VERSION 5.8 ;
BUSBITCHARS "[]" ;
DIVIDERCHAR "/" ;
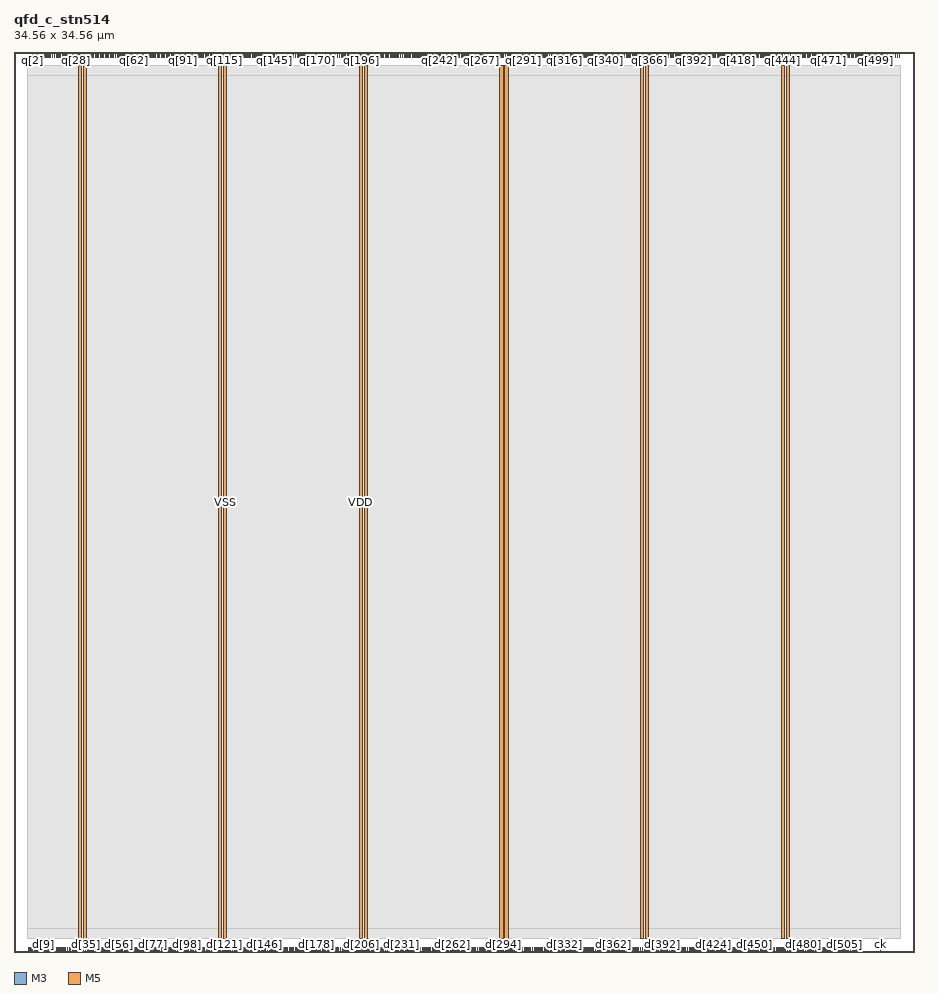
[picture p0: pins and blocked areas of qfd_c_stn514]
MACRO qfd_c_stn514
  CLASS BLOCK ;
  ORIGIN 0 0 ;
  FOREIGN qfd_c_stn514 0 0 ;
  SIZE 34.56 BY 34.56 ;
  SYMMETRY X Y ;
  PIN d[0]
    DIRECTION INPUT ;
    USE SIGNAL ;
    PORT
      LAYER M3 ;
        RECT 0.573 0.000 0.597 0.192 ;
    END
  END d[0]
  PIN d[1]
    DIRECTION INPUT ;
    USE SIGNAL ;
    PORT
      LAYER M5 ;
        RECT 0.624 0.000 0.648 0.192 ;
    END
  END d[1]
  PIN d[2]
    DIRECTION INPUT ;
    USE SIGNAL ;
    PORT
      LAYER M3 ;
        RECT 0.681 0.000 0.705 0.192 ;
    END
  END d[2]
  PIN d[3]
    DIRECTION INPUT ;
    USE SIGNAL ;
    PORT
      LAYER M5 ;
        RECT 0.768 0.000 0.792 0.192 ;
    END
  END d[3]
  PIN d[4]
    DIRECTION INPUT ;
    USE SIGNAL ;
    PORT
      LAYER M3 ;
        RECT 0.789 0.000 0.813 0.192 ;
    END
  END d[4]
  PIN d[5]
    DIRECTION INPUT ;
    USE SIGNAL ;
    PORT
      LAYER M5 ;
        RECT 0.864 0.000 0.888 0.192 ;
    END
  END d[5]
  PIN d[6]
    DIRECTION INPUT ;
    USE SIGNAL ;
    PORT
      LAYER M3 ;
        RECT 0.933 0.000 0.957 0.192 ;
    END
  END d[6]
  PIN d[7]
    DIRECTION INPUT ;
    USE SIGNAL ;
    PORT
      LAYER M5 ;
        RECT 1.008 0.000 1.032 0.192 ;
    END
  END d[7]
  PIN d[8]
    DIRECTION INPUT ;
    USE SIGNAL ;
    PORT
      LAYER M3 ;
        RECT 1.041 0.000 1.065 0.192 ;
    END
  END d[8]
  PIN d[9]
    DIRECTION INPUT ;
    USE SIGNAL ;
    PORT
      LAYER M5 ;
        RECT 1.104 0.000 1.128 0.192 ;
    END
  END d[9]
  PIN d[10]
    DIRECTION INPUT ;
    USE SIGNAL ;
    PORT
      LAYER M3 ;
        RECT 1.185 0.000 1.209 0.192 ;
    END
  END d[10]
  PIN d[11]
    DIRECTION INPUT ;
    USE SIGNAL ;
    PORT
      LAYER M5 ;
        RECT 1.248 0.000 1.272 0.192 ;
    END
  END d[11]
  PIN d[12]
    DIRECTION INPUT ;
    USE SIGNAL ;
    PORT
      LAYER M3 ;
        RECT 1.293 0.000 1.317 0.192 ;
    END
  END d[12]
  PIN d[13]
    DIRECTION INPUT ;
    USE SIGNAL ;
    PORT
      LAYER M5 ;
        RECT 1.344 0.000 1.368 0.192 ;
    END
  END d[13]
  PIN d[14]
    DIRECTION INPUT ;
    USE SIGNAL ;
    PORT
      LAYER M3 ;
        RECT 1.437 0.000 1.461 0.192 ;
    END
  END d[14]
  PIN d[15]
    DIRECTION INPUT ;
    USE SIGNAL ;
    PORT
      LAYER M5 ;
        RECT 1.488 0.000 1.512 0.192 ;
    END
  END d[15]
  PIN d[16]
    DIRECTION INPUT ;
    USE SIGNAL ;
    PORT
      LAYER M3 ;
        RECT 1.545 0.000 1.569 0.192 ;
    END
  END d[16]
  PIN d[17]
    DIRECTION INPUT ;
    USE SIGNAL ;
    PORT
      LAYER M5 ;
        RECT 1.632 0.000 1.656 0.192 ;
    END
  END d[17]
  PIN d[18]
    DIRECTION INPUT ;
    USE SIGNAL ;
    PORT
      LAYER M3 ;
        RECT 1.689 0.000 1.713 0.192 ;
    END
  END d[18]
  PIN d[19]
    DIRECTION INPUT ;
    USE SIGNAL ;
    PORT
      LAYER M5 ;
        RECT 1.728 0.000 1.752 0.192 ;
    END
  END d[19]
  PIN d[20]
    DIRECTION INPUT ;
    USE SIGNAL ;
    PORT
      LAYER M3 ;
        RECT 1.797 0.000 1.821 0.192 ;
    END
  END d[20]
  PIN d[21]
    DIRECTION INPUT ;
    USE SIGNAL ;
    PORT
      LAYER M5 ;
        RECT 1.872 0.000 1.896 0.192 ;
    END
  END d[21]
  PIN d[22]
    DIRECTION INPUT ;
    USE SIGNAL ;
    PORT
      LAYER M3 ;
        RECT 1.905 0.000 1.929 0.192 ;
    END
  END d[22]
  PIN d[23]
    DIRECTION INPUT ;
    USE SIGNAL ;
    PORT
      LAYER M5 ;
        RECT 1.968 0.000 1.992 0.192 ;
    END
  END d[23]
  PIN d[24]
    DIRECTION INPUT ;
    USE SIGNAL ;
    PORT
      LAYER M3 ;
        RECT 2.049 0.000 2.073 0.192 ;
    END
  END d[24]
  PIN d[25]
    DIRECTION INPUT ;
    USE SIGNAL ;
    PORT
      LAYER M5 ;
        RECT 2.112 0.000 2.136 0.192 ;
    END
  END d[25]
  PIN d[26]
    DIRECTION INPUT ;
    USE SIGNAL ;
    PORT
      LAYER M3 ;
        RECT 2.157 0.000 2.181 0.192 ;
    END
  END d[26]
  PIN d[27]
    DIRECTION INPUT ;
    USE SIGNAL ;
    PORT
      LAYER M5 ;
        RECT 2.256 0.000 2.280 0.192 ;
    END
  END d[27]
  PIN d[28]
    DIRECTION INPUT ;
    USE SIGNAL ;
    PORT
      LAYER M3 ;
        RECT 2.301 0.000 2.325 0.192 ;
    END
  END d[28]
  PIN d[29]
    DIRECTION INPUT ;
    USE SIGNAL ;
    PORT
      LAYER M5 ;
        RECT 2.352 0.000 2.376 0.192 ;
    END
  END d[29]
  PIN d[30]
    DIRECTION INPUT ;
    USE SIGNAL ;
    PORT
      LAYER M3 ;
        RECT 2.409 0.000 2.433 0.192 ;
    END
  END d[30]
  PIN d[31]
    DIRECTION INPUT ;
    USE SIGNAL ;
    PORT
      LAYER M5 ;
        RECT 2.496 0.000 2.520 0.192 ;
    END
  END d[31]
  PIN d[32]
    DIRECTION INPUT ;
    USE SIGNAL ;
    PORT
      LAYER M3 ;
        RECT 2.553 0.000 2.577 0.192 ;
    END
  END d[32]
  PIN d[33]
    DIRECTION INPUT ;
    USE SIGNAL ;
    PORT
      LAYER M5 ;
        RECT 2.592 0.000 2.616 0.192 ;
    END
  END d[33]
  PIN d[34]
    DIRECTION INPUT ;
    USE SIGNAL ;
    PORT
      LAYER M3 ;
        RECT 2.661 0.000 2.685 0.192 ;
    END
  END d[34]
  PIN d[35]
    DIRECTION INPUT ;
    USE SIGNAL ;
    PORT
      LAYER M5 ;
        RECT 2.736 0.000 2.760 0.192 ;
    END
  END d[35]
  PIN d[36]
    DIRECTION INPUT ;
    USE SIGNAL ;
    PORT
      LAYER M3 ;
        RECT 2.805 0.000 2.829 0.192 ;
    END
  END d[36]
  PIN d[37]
    DIRECTION INPUT ;
    USE SIGNAL ;
    PORT
      LAYER M5 ;
        RECT 2.832 0.000 2.856 0.192 ;
    END
  END d[37]
  PIN d[38]
    DIRECTION INPUT ;
    USE SIGNAL ;
    PORT
      LAYER M3 ;
        RECT 2.913 0.000 2.937 0.192 ;
    END
  END d[38]
  PIN d[39]
    DIRECTION INPUT ;
    USE SIGNAL ;
    PORT
      LAYER M5 ;
        RECT 2.976 0.000 3.000 0.192 ;
    END
  END d[39]
  PIN d[40]
    DIRECTION INPUT ;
    USE SIGNAL ;
    PORT
      LAYER M3 ;
        RECT 3.021 0.000 3.045 0.192 ;
    END
  END d[40]
  PIN d[41]
    DIRECTION INPUT ;
    USE SIGNAL ;
    PORT
      LAYER M5 ;
        RECT 3.120 0.000 3.144 0.192 ;
    END
  END d[41]
  PIN d[42]
    DIRECTION INPUT ;
    USE SIGNAL ;
    PORT
      LAYER M3 ;
        RECT 3.165 0.000 3.189 0.192 ;
    END
  END d[42]
  PIN d[43]
    DIRECTION INPUT ;
    USE SIGNAL ;
    PORT
      LAYER M5 ;
        RECT 3.216 0.000 3.240 0.192 ;
    END
  END d[43]
  PIN d[44]
    DIRECTION INPUT ;
    USE SIGNAL ;
    PORT
      LAYER M3 ;
        RECT 3.273 0.000 3.297 0.192 ;
    END
  END d[44]
  PIN d[45]
    DIRECTION INPUT ;
    USE SIGNAL ;
    PORT
      LAYER M5 ;
        RECT 3.360 0.000 3.384 0.192 ;
    END
  END d[45]
  PIN d[46]
    DIRECTION INPUT ;
    USE SIGNAL ;
    PORT
      LAYER M3 ;
        RECT 3.417 0.000 3.441 0.192 ;
    END
  END d[46]
  PIN d[47]
    DIRECTION INPUT ;
    USE SIGNAL ;
    PORT
      LAYER M5 ;
        RECT 3.456 0.000 3.480 0.192 ;
    END
  END d[47]
  PIN d[48]
    DIRECTION INPUT ;
    USE SIGNAL ;
    PORT
      LAYER M3 ;
        RECT 3.525 0.000 3.549 0.192 ;
    END
  END d[48]
  PIN d[49]
    DIRECTION INPUT ;
    USE SIGNAL ;
    PORT
      LAYER M5 ;
        RECT 3.600 0.000 3.624 0.192 ;
    END
  END d[49]
  PIN d[50]
    DIRECTION INPUT ;
    USE SIGNAL ;
    PORT
      LAYER M3 ;
        RECT 3.669 0.000 3.693 0.192 ;
    END
  END d[50]
  PIN d[51]
    DIRECTION INPUT ;
    USE SIGNAL ;
    PORT
      LAYER M5 ;
        RECT 3.744 0.000 3.768 0.192 ;
    END
  END d[51]
  PIN d[52]
    DIRECTION INPUT ;
    USE SIGNAL ;
    PORT
      LAYER M3 ;
        RECT 3.777 0.000 3.801 0.192 ;
    END
  END d[52]
  PIN d[53]
    DIRECTION INPUT ;
    USE SIGNAL ;
    PORT
      LAYER M5 ;
        RECT 3.840 0.000 3.864 0.192 ;
    END
  END d[53]
  PIN d[54]
    DIRECTION INPUT ;
    USE SIGNAL ;
    PORT
      LAYER M3 ;
        RECT 3.921 0.000 3.945 0.192 ;
    END
  END d[54]
  PIN d[55]
    DIRECTION INPUT ;
    USE SIGNAL ;
    PORT
      LAYER M5 ;
        RECT 3.984 0.000 4.008 0.192 ;
    END
  END d[55]
  PIN d[56]
    DIRECTION INPUT ;
    USE SIGNAL ;
    PORT
      LAYER M3 ;
        RECT 4.029 0.000 4.053 0.192 ;
    END
  END d[56]
  PIN d[57]
    DIRECTION INPUT ;
    USE SIGNAL ;
    PORT
      LAYER M5 ;
        RECT 4.080 0.000 4.104 0.192 ;
    END
  END d[57]
  PIN d[58]
    DIRECTION INPUT ;
    USE SIGNAL ;
    PORT
      LAYER M3 ;
        RECT 4.137 0.000 4.161 0.192 ;
    END
  END d[58]
  PIN d[59]
    DIRECTION INPUT ;
    USE SIGNAL ;
    PORT
      LAYER M5 ;
        RECT 4.224 0.000 4.248 0.192 ;
    END
  END d[59]
  PIN d[60]
    DIRECTION INPUT ;
    USE SIGNAL ;
    PORT
      LAYER M3 ;
        RECT 4.281 0.000 4.305 0.192 ;
    END
  END d[60]
  PIN d[61]
    DIRECTION INPUT ;
    USE SIGNAL ;
    PORT
      LAYER M5 ;
        RECT 4.320 0.000 4.344 0.192 ;
    END
  END d[61]
  PIN d[62]
    DIRECTION INPUT ;
    USE SIGNAL ;
    PORT
      LAYER M3 ;
        RECT 4.389 0.000 4.413 0.192 ;
    END
  END d[62]
  PIN d[63]
    DIRECTION INPUT ;
    USE SIGNAL ;
    PORT
      LAYER M5 ;
        RECT 4.464 0.000 4.488 0.192 ;
    END
  END d[63]
  PIN d[64]
    DIRECTION INPUT ;
    USE SIGNAL ;
    PORT
      LAYER M3 ;
        RECT 4.533 0.000 4.557 0.192 ;
    END
  END d[64]
  PIN d[65]
    DIRECTION INPUT ;
    USE SIGNAL ;
    PORT
      LAYER M5 ;
        RECT 4.608 0.000 4.632 0.192 ;
    END
  END d[65]
  PIN d[66]
    DIRECTION INPUT ;
    USE SIGNAL ;
    PORT
      LAYER M3 ;
        RECT 4.641 0.000 4.665 0.192 ;
    END
  END d[66]
  PIN d[67]
    DIRECTION INPUT ;
    USE SIGNAL ;
    PORT
      LAYER M5 ;
        RECT 4.704 0.000 4.728 0.192 ;
    END
  END d[67]
  PIN d[68]
    DIRECTION INPUT ;
    USE SIGNAL ;
    PORT
      LAYER M3 ;
        RECT 4.785 0.000 4.809 0.192 ;
    END
  END d[68]
  PIN d[69]
    DIRECTION INPUT ;
    USE SIGNAL ;
    PORT
      LAYER M5 ;
        RECT 4.848 0.000 4.872 0.192 ;
    END
  END d[69]
  PIN d[70]
    DIRECTION INPUT ;
    USE SIGNAL ;
    PORT
      LAYER M3 ;
        RECT 4.893 0.000 4.917 0.192 ;
    END
  END d[70]
  PIN d[71]
    DIRECTION INPUT ;
    USE SIGNAL ;
    PORT
      LAYER M5 ;
        RECT 4.944 0.000 4.968 0.192 ;
    END
  END d[71]
  PIN d[72]
    DIRECTION INPUT ;
    USE SIGNAL ;
    PORT
      LAYER M3 ;
        RECT 5.037 0.000 5.061 0.192 ;
    END
  END d[72]
  PIN d[73]
    DIRECTION INPUT ;
    USE SIGNAL ;
    PORT
      LAYER M5 ;
        RECT 5.088 0.000 5.112 0.192 ;
    END
  END d[73]
  PIN d[74]
    DIRECTION INPUT ;
    USE SIGNAL ;
    PORT
      LAYER M3 ;
        RECT 5.145 0.000 5.169 0.192 ;
    END
  END d[74]
  PIN d[75]
    DIRECTION INPUT ;
    USE SIGNAL ;
    PORT
      LAYER M5 ;
        RECT 5.184 0.000 5.208 0.192 ;
    END
  END d[75]
  PIN d[76]
    DIRECTION INPUT ;
    USE SIGNAL ;
    PORT
      LAYER M3 ;
        RECT 5.253 0.000 5.277 0.192 ;
    END
  END d[76]
  PIN d[77]
    DIRECTION INPUT ;
    USE SIGNAL ;
    PORT
      LAYER M5 ;
        RECT 5.328 0.000 5.352 0.192 ;
    END
  END d[77]
  PIN d[78]
    DIRECTION INPUT ;
    USE SIGNAL ;
    PORT
      LAYER M3 ;
        RECT 5.397 0.000 5.421 0.192 ;
    END
  END d[78]
  PIN d[79]
    DIRECTION INPUT ;
    USE SIGNAL ;
    PORT
      LAYER M5 ;
        RECT 5.472 0.000 5.496 0.192 ;
    END
  END d[79]
  PIN d[80]
    DIRECTION INPUT ;
    USE SIGNAL ;
    PORT
      LAYER M3 ;
        RECT 5.505 0.000 5.529 0.192 ;
    END
  END d[80]
  PIN d[81]
    DIRECTION INPUT ;
    USE SIGNAL ;
    PORT
      LAYER M5 ;
        RECT 5.568 0.000 5.592 0.192 ;
    END
  END d[81]
  PIN d[82]
    DIRECTION INPUT ;
    USE SIGNAL ;
    PORT
      LAYER M3 ;
        RECT 5.649 0.000 5.673 0.192 ;
    END
  END d[82]
  PIN d[83]
    DIRECTION INPUT ;
    USE SIGNAL ;
    PORT
      LAYER M5 ;
        RECT 5.712 0.000 5.736 0.192 ;
    END
  END d[83]
  PIN d[84]
    DIRECTION INPUT ;
    USE SIGNAL ;
    PORT
      LAYER M3 ;
        RECT 5.757 0.000 5.781 0.192 ;
    END
  END d[84]
  PIN d[85]
    DIRECTION INPUT ;
    USE SIGNAL ;
    PORT
      LAYER M5 ;
        RECT 5.808 0.000 5.832 0.192 ;
    END
  END d[85]
  PIN d[86]
    DIRECTION INPUT ;
    USE SIGNAL ;
    PORT
      LAYER M3 ;
        RECT 5.901 0.000 5.925 0.192 ;
    END
  END d[86]
  PIN d[87]
    DIRECTION INPUT ;
    USE SIGNAL ;
    PORT
      LAYER M5 ;
        RECT 5.952 0.000 5.976 0.192 ;
    END
  END d[87]
  PIN d[88]
    DIRECTION INPUT ;
    USE SIGNAL ;
    PORT
      LAYER M3 ;
        RECT 6.009 0.000 6.033 0.192 ;
    END
  END d[88]
  PIN d[89]
    DIRECTION INPUT ;
    USE SIGNAL ;
    PORT
      LAYER M5 ;
        RECT 6.096 0.000 6.120 0.192 ;
    END
  END d[89]
  PIN d[90]
    DIRECTION INPUT ;
    USE SIGNAL ;
    PORT
      LAYER M3 ;
        RECT 6.153 0.000 6.177 0.192 ;
    END
  END d[90]
  PIN d[91]
    DIRECTION INPUT ;
    USE SIGNAL ;
    PORT
      LAYER M5 ;
        RECT 6.192 0.000 6.216 0.192 ;
    END
  END d[91]
  PIN d[92]
    DIRECTION INPUT ;
    USE SIGNAL ;
    PORT
      LAYER M3 ;
        RECT 6.261 0.000 6.285 0.192 ;
    END
  END d[92]
  PIN d[93]
    DIRECTION INPUT ;
    USE SIGNAL ;
    PORT
      LAYER M5 ;
        RECT 6.336 0.000 6.360 0.192 ;
    END
  END d[93]
  PIN d[94]
    DIRECTION INPUT ;
    USE SIGNAL ;
    PORT
      LAYER M3 ;
        RECT 6.369 0.000 6.393 0.192 ;
    END
  END d[94]
  PIN d[95]
    DIRECTION INPUT ;
    USE SIGNAL ;
    PORT
      LAYER M5 ;
        RECT 6.432 0.000 6.456 0.192 ;
    END
  END d[95]
  PIN d[96]
    DIRECTION INPUT ;
    USE SIGNAL ;
    PORT
      LAYER M3 ;
        RECT 6.513 0.000 6.537 0.192 ;
    END
  END d[96]
  PIN d[97]
    DIRECTION INPUT ;
    USE SIGNAL ;
    PORT
      LAYER M5 ;
        RECT 6.576 0.000 6.600 0.192 ;
    END
  END d[97]
  PIN d[98]
    DIRECTION INPUT ;
    USE SIGNAL ;
    PORT
      LAYER M3 ;
        RECT 6.621 0.000 6.645 0.192 ;
    END
  END d[98]
  PIN d[99]
    DIRECTION INPUT ;
    USE SIGNAL ;
    PORT
      LAYER M5 ;
        RECT 6.672 0.000 6.696 0.192 ;
    END
  END d[99]
  PIN d[100]
    DIRECTION INPUT ;
    USE SIGNAL ;
    PORT
      LAYER M3 ;
        RECT 6.765 0.000 6.789 0.192 ;
    END
  END d[100]
  PIN d[101]
    DIRECTION INPUT ;
    USE SIGNAL ;
    PORT
      LAYER M5 ;
        RECT 6.816 0.000 6.840 0.192 ;
    END
  END d[101]
  PIN d[102]
    DIRECTION INPUT ;
    USE SIGNAL ;
    PORT
      LAYER M3 ;
        RECT 6.873 0.000 6.897 0.192 ;
    END
  END d[102]
  PIN d[103]
    DIRECTION INPUT ;
    USE SIGNAL ;
    PORT
      LAYER M5 ;
        RECT 6.960 0.000 6.984 0.192 ;
    END
  END d[103]
  PIN d[104]
    DIRECTION INPUT ;
    USE SIGNAL ;
    PORT
      LAYER M3 ;
        RECT 7.017 0.000 7.041 0.192 ;
    END
  END d[104]
  PIN d[105]
    DIRECTION INPUT ;
    USE SIGNAL ;
    PORT
      LAYER M5 ;
        RECT 7.056 0.000 7.080 0.192 ;
    END
  END d[105]
  PIN d[106]
    DIRECTION INPUT ;
    USE SIGNAL ;
    PORT
      LAYER M3 ;
        RECT 7.125 0.000 7.149 0.192 ;
    END
  END d[106]
  PIN d[107]
    DIRECTION INPUT ;
    USE SIGNAL ;
    PORT
      LAYER M5 ;
        RECT 7.200 0.000 7.224 0.192 ;
    END
  END d[107]
  PIN d[108]
    DIRECTION INPUT ;
    USE SIGNAL ;
    PORT
      LAYER M3 ;
        RECT 7.269 0.000 7.293 0.192 ;
    END
  END d[108]
  PIN d[109]
    DIRECTION INPUT ;
    USE SIGNAL ;
    PORT
      LAYER M5 ;
        RECT 7.296 0.000 7.320 0.192 ;
    END
  END d[109]
  PIN d[110]
    DIRECTION INPUT ;
    USE SIGNAL ;
    PORT
      LAYER M3 ;
        RECT 7.377 0.000 7.401 0.192 ;
    END
  END d[110]
  PIN d[111]
    DIRECTION INPUT ;
    USE SIGNAL ;
    PORT
      LAYER M5 ;
        RECT 7.440 0.000 7.464 0.192 ;
    END
  END d[111]
  PIN d[112]
    DIRECTION INPUT ;
    USE SIGNAL ;
    PORT
      LAYER M3 ;
        RECT 7.485 0.000 7.509 0.192 ;
    END
  END d[112]
  PIN d[113]
    DIRECTION INPUT ;
    USE SIGNAL ;
    PORT
      LAYER M5 ;
        RECT 7.584 0.000 7.608 0.192 ;
    END
  END d[113]
  PIN d[114]
    DIRECTION INPUT ;
    USE SIGNAL ;
    PORT
      LAYER M3 ;
        RECT 7.629 0.000 7.653 0.192 ;
    END
  END d[114]
  PIN d[115]
    DIRECTION INPUT ;
    USE SIGNAL ;
    PORT
      LAYER M5 ;
        RECT 7.680 0.000 7.704 0.192 ;
    END
  END d[115]
  PIN d[116]
    DIRECTION INPUT ;
    USE SIGNAL ;
    PORT
      LAYER M3 ;
        RECT 7.737 0.000 7.761 0.192 ;
    END
  END d[116]
  PIN d[117]
    DIRECTION INPUT ;
    USE SIGNAL ;
    PORT
      LAYER M5 ;
        RECT 7.824 0.000 7.848 0.192 ;
    END
  END d[117]
  PIN d[118]
    DIRECTION INPUT ;
    USE SIGNAL ;
    PORT
      LAYER M3 ;
        RECT 7.881 0.000 7.905 0.192 ;
    END
  END d[118]
  PIN d[119]
    DIRECTION INPUT ;
    USE SIGNAL ;
    PORT
      LAYER M5 ;
        RECT 7.920 0.000 7.944 0.192 ;
    END
  END d[119]
  PIN d[120]
    DIRECTION INPUT ;
    USE SIGNAL ;
    PORT
      LAYER M3 ;
        RECT 7.989 0.000 8.013 0.192 ;
    END
  END d[120]
  PIN d[121]
    DIRECTION INPUT ;
    USE SIGNAL ;
    PORT
      LAYER M5 ;
        RECT 8.064 0.000 8.088 0.192 ;
    END
  END d[121]
  PIN d[122]
    DIRECTION INPUT ;
    USE SIGNAL ;
    PORT
      LAYER M3 ;
        RECT 8.133 0.000 8.157 0.192 ;
    END
  END d[122]
  PIN d[123]
    DIRECTION INPUT ;
    USE SIGNAL ;
    PORT
      LAYER M5 ;
        RECT 8.160 0.000 8.184 0.192 ;
    END
  END d[123]
  PIN d[124]
    DIRECTION INPUT ;
    USE SIGNAL ;
    PORT
      LAYER M3 ;
        RECT 8.241 0.000 8.265 0.192 ;
    END
  END d[124]
  PIN d[125]
    DIRECTION INPUT ;
    USE SIGNAL ;
    PORT
      LAYER M5 ;
        RECT 8.304 0.000 8.328 0.192 ;
    END
  END d[125]
  PIN d[126]
    DIRECTION INPUT ;
    USE SIGNAL ;
    PORT
      LAYER M3 ;
        RECT 8.385 0.000 8.409 0.192 ;
    END
  END d[126]
  PIN d[127]
    DIRECTION INPUT ;
    USE SIGNAL ;
    PORT
      LAYER M5 ;
        RECT 8.448 0.000 8.472 0.192 ;
    END
  END d[127]
  PIN d[128]
    DIRECTION INPUT ;
    USE SIGNAL ;
    PORT
      LAYER M3 ;
        RECT 8.493 0.000 8.517 0.192 ;
    END
  END d[128]
  PIN d[129]
    DIRECTION INPUT ;
    USE SIGNAL ;
    PORT
      LAYER M5 ;
        RECT 8.544 0.000 8.568 0.192 ;
    END
  END d[129]
  PIN d[130]
    DIRECTION INPUT ;
    USE SIGNAL ;
    PORT
      LAYER M3 ;
        RECT 8.601 0.000 8.625 0.192 ;
    END
  END d[130]
  PIN d[131]
    DIRECTION INPUT ;
    USE SIGNAL ;
    PORT
      LAYER M5 ;
        RECT 8.688 0.000 8.712 0.192 ;
    END
  END d[131]
  PIN d[132]
    DIRECTION INPUT ;
    USE SIGNAL ;
    PORT
      LAYER M3 ;
        RECT 8.745 0.000 8.769 0.192 ;
    END
  END d[132]
  PIN d[133]
    DIRECTION INPUT ;
    USE SIGNAL ;
    PORT
      LAYER M5 ;
        RECT 8.784 0.000 8.808 0.192 ;
    END
  END d[133]
  PIN d[134]
    DIRECTION INPUT ;
    USE SIGNAL ;
    PORT
      LAYER M3 ;
        RECT 8.853 0.000 8.877 0.192 ;
    END
  END d[134]
  PIN d[135]
    DIRECTION INPUT ;
    USE SIGNAL ;
    PORT
      LAYER M5 ;
        RECT 8.928 0.000 8.952 0.192 ;
    END
  END d[135]
  PIN d[136]
    DIRECTION INPUT ;
    USE SIGNAL ;
    PORT
      LAYER M3 ;
        RECT 8.997 0.000 9.021 0.192 ;
    END
  END d[136]
  PIN d[137]
    DIRECTION INPUT ;
    USE SIGNAL ;
    PORT
      LAYER M5 ;
        RECT 9.072 0.000 9.096 0.192 ;
    END
  END d[137]
  PIN d[138]
    DIRECTION INPUT ;
    USE SIGNAL ;
    PORT
      LAYER M3 ;
        RECT 9.105 0.000 9.129 0.192 ;
    END
  END d[138]
  PIN d[139]
    DIRECTION INPUT ;
    USE SIGNAL ;
    PORT
      LAYER M5 ;
        RECT 9.168 0.000 9.192 0.192 ;
    END
  END d[139]
  PIN d[140]
    DIRECTION INPUT ;
    USE SIGNAL ;
    PORT
      LAYER M3 ;
        RECT 9.249 0.000 9.273 0.192 ;
    END
  END d[140]
  PIN d[141]
    DIRECTION INPUT ;
    USE SIGNAL ;
    PORT
      LAYER M5 ;
        RECT 9.312 0.000 9.336 0.192 ;
    END
  END d[141]
  PIN d[142]
    DIRECTION INPUT ;
    USE SIGNAL ;
    PORT
      LAYER M3 ;
        RECT 9.357 0.000 9.381 0.192 ;
    END
  END d[142]
  PIN d[143]
    DIRECTION INPUT ;
    USE SIGNAL ;
    PORT
      LAYER M5 ;
        RECT 9.408 0.000 9.432 0.192 ;
    END
  END d[143]
  PIN d[144]
    DIRECTION INPUT ;
    USE SIGNAL ;
    PORT
      LAYER M3 ;
        RECT 9.501 0.000 9.525 0.192 ;
    END
  END d[144]
  PIN d[145]
    DIRECTION INPUT ;
    USE SIGNAL ;
    PORT
      LAYER M5 ;
        RECT 9.552 0.000 9.576 0.192 ;
    END
  END d[145]
  PIN d[146]
    DIRECTION INPUT ;
    USE SIGNAL ;
    PORT
      LAYER M3 ;
        RECT 9.609 0.000 9.633 0.192 ;
    END
  END d[146]
  PIN d[147]
    DIRECTION INPUT ;
    USE SIGNAL ;
    PORT
      LAYER M5 ;
        RECT 9.648 0.000 9.672 0.192 ;
    END
  END d[147]
  PIN d[148]
    DIRECTION INPUT ;
    USE SIGNAL ;
    PORT
      LAYER M3 ;
        RECT 9.717 0.000 9.741 0.192 ;
    END
  END d[148]
  PIN d[149]
    DIRECTION INPUT ;
    USE SIGNAL ;
    PORT
      LAYER M5 ;
        RECT 9.792 0.000 9.816 0.192 ;
    END
  END d[149]
  PIN d[150]
    DIRECTION INPUT ;
    USE SIGNAL ;
    PORT
      LAYER M3 ;
        RECT 9.861 0.000 9.885 0.192 ;
    END
  END d[150]
  PIN d[151]
    DIRECTION INPUT ;
    USE SIGNAL ;
    PORT
      LAYER M5 ;
        RECT 9.936 0.000 9.960 0.192 ;
    END
  END d[151]
  PIN d[152]
    DIRECTION INPUT ;
    USE SIGNAL ;
    PORT
      LAYER M3 ;
        RECT 9.969 0.000 9.993 0.192 ;
    END
  END d[152]
  PIN d[153]
    DIRECTION INPUT ;
    USE SIGNAL ;
    PORT
      LAYER M5 ;
        RECT 10.032 0.000 10.056 0.192 ;
    END
  END d[153]
  PIN d[154]
    DIRECTION INPUT ;
    USE SIGNAL ;
    PORT
      LAYER M3 ;
        RECT 10.113 0.000 10.137 0.192 ;
    END
  END d[154]
  PIN d[155]
    DIRECTION INPUT ;
    USE SIGNAL ;
    PORT
      LAYER M5 ;
        RECT 10.176 0.000 10.200 0.192 ;
    END
  END d[155]
  PIN d[156]
    DIRECTION INPUT ;
    USE SIGNAL ;
    PORT
      LAYER M3 ;
        RECT 10.221 0.000 10.245 0.192 ;
    END
  END d[156]
  PIN d[157]
    DIRECTION INPUT ;
    USE SIGNAL ;
    PORT
      LAYER M5 ;
        RECT 10.272 0.000 10.296 0.192 ;
    END
  END d[157]
  PIN d[158]
    DIRECTION INPUT ;
    USE SIGNAL ;
    PORT
      LAYER M3 ;
        RECT 10.365 0.000 10.389 0.192 ;
    END
  END d[158]
  PIN d[159]
    DIRECTION INPUT ;
    USE SIGNAL ;
    PORT
      LAYER M5 ;
        RECT 10.416 0.000 10.440 0.192 ;
    END
  END d[159]
  PIN d[160]
    DIRECTION INPUT ;
    USE SIGNAL ;
    PORT
      LAYER M3 ;
        RECT 10.473 0.000 10.497 0.192 ;
    END
  END d[160]
  PIN d[161]
    DIRECTION INPUT ;
    USE SIGNAL ;
    PORT
      LAYER M5 ;
        RECT 10.560 0.000 10.584 0.192 ;
    END
  END d[161]
  PIN d[162]
    DIRECTION INPUT ;
    USE SIGNAL ;
    PORT
      LAYER M3 ;
        RECT 10.617 0.000 10.641 0.192 ;
    END
  END d[162]
  PIN d[163]
    DIRECTION INPUT ;
    USE SIGNAL ;
    PORT
      LAYER M5 ;
        RECT 10.656 0.000 10.680 0.192 ;
    END
  END d[163]
  PIN d[164]
    DIRECTION INPUT ;
    USE SIGNAL ;
    PORT
      LAYER M3 ;
        RECT 10.725 0.000 10.749 0.192 ;
    END
  END d[164]
  PIN d[165]
    DIRECTION INPUT ;
    USE SIGNAL ;
    PORT
      LAYER M5 ;
        RECT 10.800 0.000 10.824 0.192 ;
    END
  END d[165]
  PIN d[166]
    DIRECTION INPUT ;
    USE SIGNAL ;
    PORT
      LAYER M3 ;
        RECT 10.833 0.000 10.857 0.192 ;
    END
  END d[166]
  PIN d[167]
    DIRECTION INPUT ;
    USE SIGNAL ;
    PORT
      LAYER M5 ;
        RECT 10.896 0.000 10.920 0.192 ;
    END
  END d[167]
  PIN d[168]
    DIRECTION INPUT ;
    USE SIGNAL ;
    PORT
      LAYER M3 ;
        RECT 10.977 0.000 11.001 0.192 ;
    END
  END d[168]
  PIN d[169]
    DIRECTION INPUT ;
    USE SIGNAL ;
    PORT
      LAYER M5 ;
        RECT 11.040 0.000 11.064 0.192 ;
    END
  END d[169]
  PIN d[170]
    DIRECTION INPUT ;
    USE SIGNAL ;
    PORT
      LAYER M3 ;
        RECT 11.085 0.000 11.109 0.192 ;
    END
  END d[170]
  PIN d[171]
    DIRECTION INPUT ;
    USE SIGNAL ;
    PORT
      LAYER M5 ;
        RECT 11.136 0.000 11.160 0.192 ;
    END
  END d[171]
  PIN d[172]
    DIRECTION INPUT ;
    USE SIGNAL ;
    PORT
      LAYER M3 ;
        RECT 11.229 0.000 11.253 0.192 ;
    END
  END d[172]
  PIN d[173]
    DIRECTION INPUT ;
    USE SIGNAL ;
    PORT
      LAYER M5 ;
        RECT 11.280 0.000 11.304 0.192 ;
    END
  END d[173]
  PIN d[174]
    DIRECTION INPUT ;
    USE SIGNAL ;
    PORT
      LAYER M3 ;
        RECT 11.337 0.000 11.361 0.192 ;
    END
  END d[174]
  PIN d[175]
    DIRECTION INPUT ;
    USE SIGNAL ;
    PORT
      LAYER M5 ;
        RECT 11.424 0.000 11.448 0.192 ;
    END
  END d[175]
  PIN d[176]
    DIRECTION INPUT ;
    USE SIGNAL ;
    PORT
      LAYER M3 ;
        RECT 11.481 0.000 11.505 0.192 ;
    END
  END d[176]
  PIN d[177]
    DIRECTION INPUT ;
    USE SIGNAL ;
    PORT
      LAYER M5 ;
        RECT 11.520 0.000 11.544 0.192 ;
    END
  END d[177]
  PIN d[178]
    DIRECTION INPUT ;
    USE SIGNAL ;
    PORT
      LAYER M3 ;
        RECT 11.589 0.000 11.613 0.192 ;
    END
  END d[178]
  PIN d[179]
    DIRECTION INPUT ;
    USE SIGNAL ;
    PORT
      LAYER M5 ;
        RECT 11.664 0.000 11.688 0.192 ;
    END
  END d[179]
  PIN d[180]
    DIRECTION INPUT ;
    USE SIGNAL ;
    PORT
      LAYER M3 ;
        RECT 11.733 0.000 11.757 0.192 ;
    END
  END d[180]
  PIN d[181]
    DIRECTION INPUT ;
    USE SIGNAL ;
    PORT
      LAYER M5 ;
        RECT 11.760 0.000 11.784 0.192 ;
    END
  END d[181]
  PIN d[182]
    DIRECTION INPUT ;
    USE SIGNAL ;
    PORT
      LAYER M3 ;
        RECT 11.841 0.000 11.865 0.192 ;
    END
  END d[182]
  PIN d[183]
    DIRECTION INPUT ;
    USE SIGNAL ;
    PORT
      LAYER M5 ;
        RECT 11.904 0.000 11.928 0.192 ;
    END
  END d[183]
  PIN d[184]
    DIRECTION INPUT ;
    USE SIGNAL ;
    PORT
      LAYER M3 ;
        RECT 11.949 0.000 11.973 0.192 ;
    END
  END d[184]
  PIN d[185]
    DIRECTION INPUT ;
    USE SIGNAL ;
    PORT
      LAYER M5 ;
        RECT 12.048 0.000 12.072 0.192 ;
    END
  END d[185]
  PIN d[186]
    DIRECTION INPUT ;
    USE SIGNAL ;
    PORT
      LAYER M3 ;
        RECT 12.093 0.000 12.117 0.192 ;
    END
  END d[186]
  PIN d[187]
    DIRECTION INPUT ;
    USE SIGNAL ;
    PORT
      LAYER M5 ;
        RECT 12.144 0.000 12.168 0.192 ;
    END
  END d[187]
  PIN d[188]
    DIRECTION INPUT ;
    USE SIGNAL ;
    PORT
      LAYER M3 ;
        RECT 12.201 0.000 12.225 0.192 ;
    END
  END d[188]
  PIN d[189]
    DIRECTION INPUT ;
    USE SIGNAL ;
    PORT
      LAYER M5 ;
        RECT 12.288 0.000 12.312 0.192 ;
    END
  END d[189]
  PIN d[190]
    DIRECTION INPUT ;
    USE SIGNAL ;
    PORT
      LAYER M3 ;
        RECT 12.345 0.000 12.369 0.192 ;
    END
  END d[190]
  PIN d[191]
    DIRECTION INPUT ;
    USE SIGNAL ;
    PORT
      LAYER M5 ;
        RECT 12.384 0.000 12.408 0.192 ;
    END
  END d[191]
  PIN d[192]
    DIRECTION INPUT ;
    USE SIGNAL ;
    PORT
      LAYER M3 ;
        RECT 12.453 0.000 12.477 0.192 ;
    END
  END d[192]
  PIN d[193]
    DIRECTION INPUT ;
    USE SIGNAL ;
    PORT
      LAYER M5 ;
        RECT 12.528 0.000 12.552 0.192 ;
    END
  END d[193]
  PIN d[194]
    DIRECTION INPUT ;
    USE SIGNAL ;
    PORT
      LAYER M3 ;
        RECT 12.597 0.000 12.621 0.192 ;
    END
  END d[194]
  PIN d[195]
    DIRECTION INPUT ;
    USE SIGNAL ;
    PORT
      LAYER M5 ;
        RECT 12.624 0.000 12.648 0.192 ;
    END
  END d[195]
  PIN d[196]
    DIRECTION INPUT ;
    USE SIGNAL ;
    PORT
      LAYER M3 ;
        RECT 12.705 0.000 12.729 0.192 ;
    END
  END d[196]
  PIN d[197]
    DIRECTION INPUT ;
    USE SIGNAL ;
    PORT
      LAYER M5 ;
        RECT 12.768 0.000 12.792 0.192 ;
    END
  END d[197]
  PIN d[198]
    DIRECTION INPUT ;
    USE SIGNAL ;
    PORT
      LAYER M3 ;
        RECT 12.849 0.000 12.873 0.192 ;
    END
  END d[198]
  PIN d[199]
    DIRECTION INPUT ;
    USE SIGNAL ;
    PORT
      LAYER M5 ;
        RECT 12.912 0.000 12.936 0.192 ;
    END
  END d[199]
  PIN d[200]
    DIRECTION INPUT ;
    USE SIGNAL ;
    PORT
      LAYER M3 ;
        RECT 12.957 0.000 12.981 0.192 ;
    END
  END d[200]
  PIN d[201]
    DIRECTION INPUT ;
    USE SIGNAL ;
    PORT
      LAYER M5 ;
        RECT 13.008 0.000 13.032 0.192 ;
    END
  END d[201]
  PIN d[202]
    DIRECTION INPUT ;
    USE SIGNAL ;
    PORT
      LAYER M3 ;
        RECT 13.065 0.000 13.089 0.192 ;
    END
  END d[202]
  PIN d[203]
    DIRECTION INPUT ;
    USE SIGNAL ;
    PORT
      LAYER M5 ;
        RECT 13.152 0.000 13.176 0.192 ;
    END
  END d[203]
  PIN d[204]
    DIRECTION INPUT ;
    USE SIGNAL ;
    PORT
      LAYER M3 ;
        RECT 13.209 0.000 13.233 0.192 ;
    END
  END d[204]
  PIN d[205]
    DIRECTION INPUT ;
    USE SIGNAL ;
    PORT
      LAYER M5 ;
        RECT 13.248 0.000 13.272 0.192 ;
    END
  END d[205]
  PIN d[206]
    DIRECTION INPUT ;
    USE SIGNAL ;
    PORT
      LAYER M3 ;
        RECT 13.317 0.000 13.341 0.192 ;
    END
  END d[206]
  PIN d[207]
    DIRECTION INPUT ;
    USE SIGNAL ;
    PORT
      LAYER M5 ;
        RECT 13.392 0.000 13.416 0.192 ;
    END
  END d[207]
  PIN d[208]
    DIRECTION INPUT ;
    USE SIGNAL ;
    PORT
      LAYER M3 ;
        RECT 13.461 0.000 13.485 0.192 ;
    END
  END d[208]
  PIN d[209]
    DIRECTION INPUT ;
    USE SIGNAL ;
    PORT
      LAYER M5 ;
        RECT 13.536 0.000 13.560 0.192 ;
    END
  END d[209]
  PIN d[210]
    DIRECTION INPUT ;
    USE SIGNAL ;
    PORT
      LAYER M3 ;
        RECT 13.569 0.000 13.593 0.192 ;
    END
  END d[210]
  PIN d[211]
    DIRECTION INPUT ;
    USE SIGNAL ;
    PORT
      LAYER M5 ;
        RECT 13.632 0.000 13.656 0.192 ;
    END
  END d[211]
  PIN d[212]
    DIRECTION INPUT ;
    USE SIGNAL ;
    PORT
      LAYER M3 ;
        RECT 13.713 0.000 13.737 0.192 ;
    END
  END d[212]
  PIN d[213]
    DIRECTION INPUT ;
    USE SIGNAL ;
    PORT
      LAYER M5 ;
        RECT 13.776 0.000 13.800 0.192 ;
    END
  END d[213]
  PIN d[214]
    DIRECTION INPUT ;
    USE SIGNAL ;
    PORT
      LAYER M3 ;
        RECT 13.821 0.000 13.845 0.192 ;
    END
  END d[214]
  PIN d[215]
    DIRECTION INPUT ;
    USE SIGNAL ;
    PORT
      LAYER M5 ;
        RECT 13.872 0.000 13.896 0.192 ;
    END
  END d[215]
  PIN d[216]
    DIRECTION INPUT ;
    USE SIGNAL ;
    PORT
      LAYER M3 ;
        RECT 13.965 0.000 13.989 0.192 ;
    END
  END d[216]
  PIN d[217]
    DIRECTION INPUT ;
    USE SIGNAL ;
    PORT
      LAYER M5 ;
        RECT 14.016 0.000 14.040 0.192 ;
    END
  END d[217]
  PIN d[218]
    DIRECTION INPUT ;
    USE SIGNAL ;
    PORT
      LAYER M3 ;
        RECT 14.073 0.000 14.097 0.192 ;
    END
  END d[218]
  PIN d[219]
    DIRECTION INPUT ;
    USE SIGNAL ;
    PORT
      LAYER M5 ;
        RECT 14.112 0.000 14.136 0.192 ;
    END
  END d[219]
  PIN d[220]
    DIRECTION INPUT ;
    USE SIGNAL ;
    PORT
      LAYER M3 ;
        RECT 14.181 0.000 14.205 0.192 ;
    END
  END d[220]
  PIN d[221]
    DIRECTION INPUT ;
    USE SIGNAL ;
    PORT
      LAYER M5 ;
        RECT 14.256 0.000 14.280 0.192 ;
    END
  END d[221]
  PIN d[222]
    DIRECTION INPUT ;
    USE SIGNAL ;
    PORT
      LAYER M3 ;
        RECT 14.325 0.000 14.349 0.192 ;
    END
  END d[222]
  PIN d[223]
    DIRECTION INPUT ;
    USE SIGNAL ;
    PORT
      LAYER M5 ;
        RECT 14.400 0.000 14.424 0.192 ;
    END
  END d[223]
  PIN d[224]
    DIRECTION INPUT ;
    USE SIGNAL ;
    PORT
      LAYER M3 ;
        RECT 14.433 0.000 14.457 0.192 ;
    END
  END d[224]
  PIN d[225]
    DIRECTION INPUT ;
    USE SIGNAL ;
    PORT
      LAYER M5 ;
        RECT 14.496 0.000 14.520 0.192 ;
    END
  END d[225]
  PIN d[226]
    DIRECTION INPUT ;
    USE SIGNAL ;
    PORT
      LAYER M3 ;
        RECT 14.577 0.000 14.601 0.192 ;
    END
  END d[226]
  PIN d[227]
    DIRECTION INPUT ;
    USE SIGNAL ;
    PORT
      LAYER M5 ;
        RECT 14.640 0.000 14.664 0.192 ;
    END
  END d[227]
  PIN d[228]
    DIRECTION INPUT ;
    USE SIGNAL ;
    PORT
      LAYER M3 ;
        RECT 14.685 0.000 14.709 0.192 ;
    END
  END d[228]
  PIN d[229]
    DIRECTION INPUT ;
    USE SIGNAL ;
    PORT
      LAYER M5 ;
        RECT 14.736 0.000 14.760 0.192 ;
    END
  END d[229]
  PIN d[230]
    DIRECTION INPUT ;
    USE SIGNAL ;
    PORT
      LAYER M3 ;
        RECT 14.829 0.000 14.853 0.192 ;
    END
  END d[230]
  PIN d[231]
    DIRECTION INPUT ;
    USE SIGNAL ;
    PORT
      LAYER M5 ;
        RECT 14.880 0.000 14.904 0.192 ;
    END
  END d[231]
  PIN d[232]
    DIRECTION INPUT ;
    USE SIGNAL ;
    PORT
      LAYER M3 ;
        RECT 14.937 0.000 14.961 0.192 ;
    END
  END d[232]
  PIN d[233]
    DIRECTION INPUT ;
    USE SIGNAL ;
    PORT
      LAYER M5 ;
        RECT 15.024 0.000 15.048 0.192 ;
    END
  END d[233]
  PIN d[234]
    DIRECTION INPUT ;
    USE SIGNAL ;
    PORT
      LAYER M3 ;
        RECT 15.081 0.000 15.105 0.192 ;
    END
  END d[234]
  PIN d[235]
    DIRECTION INPUT ;
    USE SIGNAL ;
    PORT
      LAYER M5 ;
        RECT 15.120 0.000 15.144 0.192 ;
    END
  END d[235]
  PIN d[236]
    DIRECTION INPUT ;
    USE SIGNAL ;
    PORT
      LAYER M3 ;
        RECT 15.189 0.000 15.213 0.192 ;
    END
  END d[236]
  PIN d[237]
    DIRECTION INPUT ;
    USE SIGNAL ;
    PORT
      LAYER M5 ;
        RECT 15.264 0.000 15.288 0.192 ;
    END
  END d[237]
  PIN d[238]
    DIRECTION INPUT ;
    USE SIGNAL ;
    PORT
      LAYER M3 ;
        RECT 15.297 0.000 15.321 0.192 ;
    END
  END d[238]
  PIN d[239]
    DIRECTION INPUT ;
    USE SIGNAL ;
    PORT
      LAYER M5 ;
        RECT 15.360 0.000 15.384 0.192 ;
    END
  END d[239]
  PIN d[240]
    DIRECTION INPUT ;
    USE SIGNAL ;
    PORT
      LAYER M3 ;
        RECT 15.441 0.000 15.465 0.192 ;
    END
  END d[240]
  PIN d[241]
    DIRECTION INPUT ;
    USE SIGNAL ;
    PORT
      LAYER M5 ;
        RECT 15.504 0.000 15.528 0.192 ;
    END
  END d[241]
  PIN d[242]
    DIRECTION INPUT ;
    USE SIGNAL ;
    PORT
      LAYER M3 ;
        RECT 15.549 0.000 15.573 0.192 ;
    END
  END d[242]
  PIN d[243]
    DIRECTION INPUT ;
    USE SIGNAL ;
    PORT
      LAYER M5 ;
        RECT 15.600 0.000 15.624 0.192 ;
    END
  END d[243]
  PIN d[244]
    DIRECTION INPUT ;
    USE SIGNAL ;
    PORT
      LAYER M3 ;
        RECT 15.693 0.000 15.717 0.192 ;
    END
  END d[244]
  PIN d[245]
    DIRECTION INPUT ;
    USE SIGNAL ;
    PORT
      LAYER M5 ;
        RECT 15.744 0.000 15.768 0.192 ;
    END
  END d[245]
  PIN d[246]
    DIRECTION INPUT ;
    USE SIGNAL ;
    PORT
      LAYER M3 ;
        RECT 15.801 0.000 15.825 0.192 ;
    END
  END d[246]
  PIN d[247]
    DIRECTION INPUT ;
    USE SIGNAL ;
    PORT
      LAYER M5 ;
        RECT 15.888 0.000 15.912 0.192 ;
    END
  END d[247]
  PIN d[248]
    DIRECTION INPUT ;
    USE SIGNAL ;
    PORT
      LAYER M3 ;
        RECT 15.945 0.000 15.969 0.192 ;
    END
  END d[248]
  PIN d[249]
    DIRECTION INPUT ;
    USE SIGNAL ;
    PORT
      LAYER M5 ;
        RECT 15.984 0.000 16.008 0.192 ;
    END
  END d[249]
  PIN d[250]
    DIRECTION INPUT ;
    USE SIGNAL ;
    PORT
      LAYER M3 ;
        RECT 16.053 0.000 16.077 0.192 ;
    END
  END d[250]
  PIN d[251]
    DIRECTION INPUT ;
    USE SIGNAL ;
    PORT
      LAYER M5 ;
        RECT 16.128 0.000 16.152 0.192 ;
    END
  END d[251]
  PIN d[252]
    DIRECTION INPUT ;
    USE SIGNAL ;
    PORT
      LAYER M3 ;
        RECT 16.197 0.000 16.221 0.192 ;
    END
  END d[252]
  PIN d[253]
    DIRECTION INPUT ;
    USE SIGNAL ;
    PORT
      LAYER M5 ;
        RECT 16.224 0.000 16.248 0.192 ;
    END
  END d[253]
  PIN d[254]
    DIRECTION INPUT ;
    USE SIGNAL ;
    PORT
      LAYER M3 ;
        RECT 16.305 0.000 16.329 0.192 ;
    END
  END d[254]
  PIN d[255]
    DIRECTION INPUT ;
    USE SIGNAL ;
    PORT
      LAYER M5 ;
        RECT 16.368 0.000 16.392 0.192 ;
    END
  END d[255]
  PIN d[256]
    DIRECTION INPUT ;
    USE SIGNAL ;
    PORT
      LAYER M3 ;
        RECT 16.413 0.000 16.437 0.192 ;
    END
  END d[256]
  PIN d[257]
    DIRECTION INPUT ;
    USE SIGNAL ;
    PORT
      LAYER M5 ;
        RECT 16.512 0.000 16.536 0.192 ;
    END
  END d[257]
  PIN d[258]
    DIRECTION INPUT ;
    USE SIGNAL ;
    PORT
      LAYER M3 ;
        RECT 16.557 0.000 16.581 0.192 ;
    END
  END d[258]
  PIN d[259]
    DIRECTION INPUT ;
    USE SIGNAL ;
    PORT
      LAYER M5 ;
        RECT 16.608 0.000 16.632 0.192 ;
    END
  END d[259]
  PIN d[260]
    DIRECTION INPUT ;
    USE SIGNAL ;
    PORT
      LAYER M3 ;
        RECT 16.665 0.000 16.689 0.192 ;
    END
  END d[260]
  PIN d[261]
    DIRECTION INPUT ;
    USE SIGNAL ;
    PORT
      LAYER M5 ;
        RECT 16.752 0.000 16.776 0.192 ;
    END
  END d[261]
  PIN d[262]
    DIRECTION INPUT ;
    USE SIGNAL ;
    PORT
      LAYER M3 ;
        RECT 16.809 0.000 16.833 0.192 ;
    END
  END d[262]
  PIN d[263]
    DIRECTION INPUT ;
    USE SIGNAL ;
    PORT
      LAYER M5 ;
        RECT 16.848 0.000 16.872 0.192 ;
    END
  END d[263]
  PIN d[264]
    DIRECTION INPUT ;
    USE SIGNAL ;
    PORT
      LAYER M3 ;
        RECT 16.917 0.000 16.941 0.192 ;
    END
  END d[264]
  PIN d[265]
    DIRECTION INPUT ;
    USE SIGNAL ;
    PORT
      LAYER M5 ;
        RECT 16.992 0.000 17.016 0.192 ;
    END
  END d[265]
  PIN d[266]
    DIRECTION INPUT ;
    USE SIGNAL ;
    PORT
      LAYER M3 ;
        RECT 17.061 0.000 17.085 0.192 ;
    END
  END d[266]
  PIN d[267]
    DIRECTION INPUT ;
    USE SIGNAL ;
    PORT
      LAYER M5 ;
        RECT 17.088 0.000 17.112 0.192 ;
    END
  END d[267]
  PIN d[268]
    DIRECTION INPUT ;
    USE SIGNAL ;
    PORT
      LAYER M3 ;
        RECT 17.169 0.000 17.193 0.192 ;
    END
  END d[268]
  PIN d[269]
    DIRECTION INPUT ;
    USE SIGNAL ;
    PORT
      LAYER M5 ;
        RECT 17.232 0.000 17.256 0.192 ;
    END
  END d[269]
  PIN d[270]
    DIRECTION INPUT ;
    USE SIGNAL ;
    PORT
      LAYER M3 ;
        RECT 17.277 0.000 17.301 0.192 ;
    END
  END d[270]
  PIN d[271]
    DIRECTION INPUT ;
    USE SIGNAL ;
    PORT
      LAYER M5 ;
        RECT 17.376 0.000 17.400 0.192 ;
    END
  END d[271]
  PIN d[272]
    DIRECTION INPUT ;
    USE SIGNAL ;
    PORT
      LAYER M3 ;
        RECT 17.421 0.000 17.445 0.192 ;
    END
  END d[272]
  PIN d[273]
    DIRECTION INPUT ;
    USE SIGNAL ;
    PORT
      LAYER M5 ;
        RECT 17.472 0.000 17.496 0.192 ;
    END
  END d[273]
  PIN d[274]
    DIRECTION INPUT ;
    USE SIGNAL ;
    PORT
      LAYER M3 ;
        RECT 17.529 0.000 17.553 0.192 ;
    END
  END d[274]
  PIN d[275]
    DIRECTION INPUT ;
    USE SIGNAL ;
    PORT
      LAYER M5 ;
        RECT 17.616 0.000 17.640 0.192 ;
    END
  END d[275]
  PIN d[276]
    DIRECTION INPUT ;
    USE SIGNAL ;
    PORT
      LAYER M3 ;
        RECT 17.673 0.000 17.697 0.192 ;
    END
  END d[276]
  PIN d[277]
    DIRECTION INPUT ;
    USE SIGNAL ;
    PORT
      LAYER M5 ;
        RECT 17.712 0.000 17.736 0.192 ;
    END
  END d[277]
  PIN d[278]
    DIRECTION INPUT ;
    USE SIGNAL ;
    PORT
      LAYER M3 ;
        RECT 17.781 0.000 17.805 0.192 ;
    END
  END d[278]
  PIN d[279]
    DIRECTION INPUT ;
    USE SIGNAL ;
    PORT
      LAYER M5 ;
        RECT 17.856 0.000 17.880 0.192 ;
    END
  END d[279]
  PIN d[280]
    DIRECTION INPUT ;
    USE SIGNAL ;
    PORT
      LAYER M3 ;
        RECT 17.925 0.000 17.949 0.192 ;
    END
  END d[280]
  PIN d[281]
    DIRECTION INPUT ;
    USE SIGNAL ;
    PORT
      LAYER M5 ;
        RECT 18.000 0.000 18.024 0.192 ;
    END
  END d[281]
  PIN d[282]
    DIRECTION INPUT ;
    USE SIGNAL ;
    PORT
      LAYER M3 ;
        RECT 18.033 0.000 18.057 0.192 ;
    END
  END d[282]
  PIN d[283]
    DIRECTION INPUT ;
    USE SIGNAL ;
    PORT
      LAYER M5 ;
        RECT 18.096 0.000 18.120 0.192 ;
    END
  END d[283]
  PIN d[284]
    DIRECTION INPUT ;
    USE SIGNAL ;
    PORT
      LAYER M3 ;
        RECT 18.177 0.000 18.201 0.192 ;
    END
  END d[284]
  PIN d[285]
    DIRECTION INPUT ;
    USE SIGNAL ;
    PORT
      LAYER M5 ;
        RECT 18.240 0.000 18.264 0.192 ;
    END
  END d[285]
  PIN d[286]
    DIRECTION INPUT ;
    USE SIGNAL ;
    PORT
      LAYER M3 ;
        RECT 18.285 0.000 18.309 0.192 ;
    END
  END d[286]
  PIN d[287]
    DIRECTION INPUT ;
    USE SIGNAL ;
    PORT
      LAYER M5 ;
        RECT 18.336 0.000 18.360 0.192 ;
    END
  END d[287]
  PIN d[288]
    DIRECTION INPUT ;
    USE SIGNAL ;
    PORT
      LAYER M3 ;
        RECT 18.393 0.000 18.417 0.192 ;
    END
  END d[288]
  PIN d[289]
    DIRECTION INPUT ;
    USE SIGNAL ;
    PORT
      LAYER M5 ;
        RECT 18.480 0.000 18.504 0.192 ;
    END
  END d[289]
  PIN d[290]
    DIRECTION INPUT ;
    USE SIGNAL ;
    PORT
      LAYER M3 ;
        RECT 18.537 0.000 18.561 0.192 ;
    END
  END d[290]
  PIN d[291]
    DIRECTION INPUT ;
    USE SIGNAL ;
    PORT
      LAYER M5 ;
        RECT 18.576 0.000 18.600 0.192 ;
    END
  END d[291]
  PIN d[292]
    DIRECTION INPUT ;
    USE SIGNAL ;
    PORT
      LAYER M3 ;
        RECT 18.645 0.000 18.669 0.192 ;
    END
  END d[292]
  PIN d[293]
    DIRECTION INPUT ;
    USE SIGNAL ;
    PORT
      LAYER M5 ;
        RECT 18.720 0.000 18.744 0.192 ;
    END
  END d[293]
  PIN d[294]
    DIRECTION INPUT ;
    USE SIGNAL ;
    PORT
      LAYER M3 ;
        RECT 18.789 0.000 18.813 0.192 ;
    END
  END d[294]
  PIN d[295]
    DIRECTION INPUT ;
    USE SIGNAL ;
    PORT
      LAYER M5 ;
        RECT 18.864 0.000 18.888 0.192 ;
    END
  END d[295]
  PIN d[296]
    DIRECTION INPUT ;
    USE SIGNAL ;
    PORT
      LAYER M3 ;
        RECT 18.897 0.000 18.921 0.192 ;
    END
  END d[296]
  PIN d[297]
    DIRECTION INPUT ;
    USE SIGNAL ;
    PORT
      LAYER M5 ;
        RECT 18.960 0.000 18.984 0.192 ;
    END
  END d[297]
  PIN d[298]
    DIRECTION INPUT ;
    USE SIGNAL ;
    PORT
      LAYER M3 ;
        RECT 19.041 0.000 19.065 0.192 ;
    END
  END d[298]
  PIN d[299]
    DIRECTION INPUT ;
    USE SIGNAL ;
    PORT
      LAYER M5 ;
        RECT 19.104 0.000 19.128 0.192 ;
    END
  END d[299]
  PIN d[300]
    DIRECTION INPUT ;
    USE SIGNAL ;
    PORT
      LAYER M3 ;
        RECT 19.149 0.000 19.173 0.192 ;
    END
  END d[300]
  PIN d[301]
    DIRECTION INPUT ;
    USE SIGNAL ;
    PORT
      LAYER M5 ;
        RECT 19.200 0.000 19.224 0.192 ;
    END
  END d[301]
  PIN d[302]
    DIRECTION INPUT ;
    USE SIGNAL ;
    PORT
      LAYER M3 ;
        RECT 19.293 0.000 19.317 0.192 ;
    END
  END d[302]
  PIN d[303]
    DIRECTION INPUT ;
    USE SIGNAL ;
    PORT
      LAYER M5 ;
        RECT 19.344 0.000 19.368 0.192 ;
    END
  END d[303]
  PIN d[304]
    DIRECTION INPUT ;
    USE SIGNAL ;
    PORT
      LAYER M3 ;
        RECT 19.401 0.000 19.425 0.192 ;
    END
  END d[304]
  PIN d[305]
    DIRECTION INPUT ;
    USE SIGNAL ;
    PORT
      LAYER M5 ;
        RECT 19.488 0.000 19.512 0.192 ;
    END
  END d[305]
  PIN d[306]
    DIRECTION INPUT ;
    USE SIGNAL ;
    PORT
      LAYER M3 ;
        RECT 19.509 0.000 19.533 0.192 ;
    END
  END d[306]
  PIN d[307]
    DIRECTION INPUT ;
    USE SIGNAL ;
    PORT
      LAYER M5 ;
        RECT 19.584 0.000 19.608 0.192 ;
    END
  END d[307]
  PIN d[308]
    DIRECTION INPUT ;
    USE SIGNAL ;
    PORT
      LAYER M3 ;
        RECT 19.653 0.000 19.677 0.192 ;
    END
  END d[308]
  PIN d[309]
    DIRECTION INPUT ;
    USE SIGNAL ;
    PORT
      LAYER M5 ;
        RECT 19.728 0.000 19.752 0.192 ;
    END
  END d[309]
  PIN d[310]
    DIRECTION INPUT ;
    USE SIGNAL ;
    PORT
      LAYER M3 ;
        RECT 19.761 0.000 19.785 0.192 ;
    END
  END d[310]
  PIN d[311]
    DIRECTION INPUT ;
    USE SIGNAL ;
    PORT
      LAYER M5 ;
        RECT 19.824 0.000 19.848 0.192 ;
    END
  END d[311]
  PIN d[312]
    DIRECTION INPUT ;
    USE SIGNAL ;
    PORT
      LAYER M3 ;
        RECT 19.905 0.000 19.929 0.192 ;
    END
  END d[312]
  PIN d[313]
    DIRECTION INPUT ;
    USE SIGNAL ;
    PORT
      LAYER M5 ;
        RECT 19.968 0.000 19.992 0.192 ;
    END
  END d[313]
  PIN d[314]
    DIRECTION INPUT ;
    USE SIGNAL ;
    PORT
      LAYER M3 ;
        RECT 20.013 0.000 20.037 0.192 ;
    END
  END d[314]
  PIN d[315]
    DIRECTION INPUT ;
    USE SIGNAL ;
    PORT
      LAYER M5 ;
        RECT 20.064 0.000 20.088 0.192 ;
    END
  END d[315]
  PIN d[316]
    DIRECTION INPUT ;
    USE SIGNAL ;
    PORT
      LAYER M3 ;
        RECT 20.157 0.000 20.181 0.192 ;
    END
  END d[316]
  PIN d[317]
    DIRECTION INPUT ;
    USE SIGNAL ;
    PORT
      LAYER M5 ;
        RECT 20.208 0.000 20.232 0.192 ;
    END
  END d[317]
  PIN d[318]
    DIRECTION INPUT ;
    USE SIGNAL ;
    PORT
      LAYER M3 ;
        RECT 20.265 0.000 20.289 0.192 ;
    END
  END d[318]
  PIN d[319]
    DIRECTION INPUT ;
    USE SIGNAL ;
    PORT
      LAYER M5 ;
        RECT 20.352 0.000 20.376 0.192 ;
    END
  END d[319]
  PIN d[320]
    DIRECTION INPUT ;
    USE SIGNAL ;
    PORT
      LAYER M3 ;
        RECT 20.409 0.000 20.433 0.192 ;
    END
  END d[320]
  PIN d[321]
    DIRECTION INPUT ;
    USE SIGNAL ;
    PORT
      LAYER M5 ;
        RECT 20.448 0.000 20.472 0.192 ;
    END
  END d[321]
  PIN d[322]
    DIRECTION INPUT ;
    USE SIGNAL ;
    PORT
      LAYER M3 ;
        RECT 20.517 0.000 20.541 0.192 ;
    END
  END d[322]
  PIN d[323]
    DIRECTION INPUT ;
    USE SIGNAL ;
    PORT
      LAYER M5 ;
        RECT 20.592 0.000 20.616 0.192 ;
    END
  END d[323]
  PIN d[324]
    DIRECTION INPUT ;
    USE SIGNAL ;
    PORT
      LAYER M3 ;
        RECT 20.625 0.000 20.649 0.192 ;
    END
  END d[324]
  PIN d[325]
    DIRECTION INPUT ;
    USE SIGNAL ;
    PORT
      LAYER M5 ;
        RECT 20.688 0.000 20.712 0.192 ;
    END
  END d[325]
  PIN d[326]
    DIRECTION INPUT ;
    USE SIGNAL ;
    PORT
      LAYER M3 ;
        RECT 20.769 0.000 20.793 0.192 ;
    END
  END d[326]
  PIN d[327]
    DIRECTION INPUT ;
    USE SIGNAL ;
    PORT
      LAYER M5 ;
        RECT 20.832 0.000 20.856 0.192 ;
    END
  END d[327]
  PIN d[328]
    DIRECTION INPUT ;
    USE SIGNAL ;
    PORT
      LAYER M3 ;
        RECT 20.877 0.000 20.901 0.192 ;
    END
  END d[328]
  PIN d[329]
    DIRECTION INPUT ;
    USE SIGNAL ;
    PORT
      LAYER M5 ;
        RECT 20.928 0.000 20.952 0.192 ;
    END
  END d[329]
  PIN d[330]
    DIRECTION INPUT ;
    USE SIGNAL ;
    PORT
      LAYER M3 ;
        RECT 21.021 0.000 21.045 0.192 ;
    END
  END d[330]
  PIN d[331]
    DIRECTION INPUT ;
    USE SIGNAL ;
    PORT
      LAYER M5 ;
        RECT 21.072 0.000 21.096 0.192 ;
    END
  END d[331]
  PIN d[332]
    DIRECTION INPUT ;
    USE SIGNAL ;
    PORT
      LAYER M3 ;
        RECT 21.129 0.000 21.153 0.192 ;
    END
  END d[332]
  PIN d[333]
    DIRECTION INPUT ;
    USE SIGNAL ;
    PORT
      LAYER M5 ;
        RECT 21.216 0.000 21.240 0.192 ;
    END
  END d[333]
  PIN d[334]
    DIRECTION INPUT ;
    USE SIGNAL ;
    PORT
      LAYER M3 ;
        RECT 21.273 0.000 21.297 0.192 ;
    END
  END d[334]
  PIN d[335]
    DIRECTION INPUT ;
    USE SIGNAL ;
    PORT
      LAYER M5 ;
        RECT 21.312 0.000 21.336 0.192 ;
    END
  END d[335]
  PIN d[336]
    DIRECTION INPUT ;
    USE SIGNAL ;
    PORT
      LAYER M3 ;
        RECT 21.381 0.000 21.405 0.192 ;
    END
  END d[336]
  PIN d[337]
    DIRECTION INPUT ;
    USE SIGNAL ;
    PORT
      LAYER M5 ;
        RECT 21.456 0.000 21.480 0.192 ;
    END
  END d[337]
  PIN d[338]
    DIRECTION INPUT ;
    USE SIGNAL ;
    PORT
      LAYER M3 ;
        RECT 21.525 0.000 21.549 0.192 ;
    END
  END d[338]
  PIN d[339]
    DIRECTION INPUT ;
    USE SIGNAL ;
    PORT
      LAYER M5 ;
        RECT 21.552 0.000 21.576 0.192 ;
    END
  END d[339]
  PIN d[340]
    DIRECTION INPUT ;
    USE SIGNAL ;
    PORT
      LAYER M3 ;
        RECT 21.633 0.000 21.657 0.192 ;
    END
  END d[340]
  PIN d[341]
    DIRECTION INPUT ;
    USE SIGNAL ;
    PORT
      LAYER M5 ;
        RECT 21.696 0.000 21.720 0.192 ;
    END
  END d[341]
  PIN d[342]
    DIRECTION INPUT ;
    USE SIGNAL ;
    PORT
      LAYER M3 ;
        RECT 21.741 0.000 21.765 0.192 ;
    END
  END d[342]
  PIN d[343]
    DIRECTION INPUT ;
    USE SIGNAL ;
    PORT
      LAYER M5 ;
        RECT 21.840 0.000 21.864 0.192 ;
    END
  END d[343]
  PIN d[344]
    DIRECTION INPUT ;
    USE SIGNAL ;
    PORT
      LAYER M3 ;
        RECT 21.885 0.000 21.909 0.192 ;
    END
  END d[344]
  PIN d[345]
    DIRECTION INPUT ;
    USE SIGNAL ;
    PORT
      LAYER M5 ;
        RECT 21.936 0.000 21.960 0.192 ;
    END
  END d[345]
  PIN d[346]
    DIRECTION INPUT ;
    USE SIGNAL ;
    PORT
      LAYER M3 ;
        RECT 21.993 0.000 22.017 0.192 ;
    END
  END d[346]
  PIN d[347]
    DIRECTION INPUT ;
    USE SIGNAL ;
    PORT
      LAYER M5 ;
        RECT 22.080 0.000 22.104 0.192 ;
    END
  END d[347]
  PIN d[348]
    DIRECTION INPUT ;
    USE SIGNAL ;
    PORT
      LAYER M3 ;
        RECT 22.137 0.000 22.161 0.192 ;
    END
  END d[348]
  PIN d[349]
    DIRECTION INPUT ;
    USE SIGNAL ;
    PORT
      LAYER M5 ;
        RECT 22.176 0.000 22.200 0.192 ;
    END
  END d[349]
  PIN d[350]
    DIRECTION INPUT ;
    USE SIGNAL ;
    PORT
      LAYER M3 ;
        RECT 22.245 0.000 22.269 0.192 ;
    END
  END d[350]
  PIN d[351]
    DIRECTION INPUT ;
    USE SIGNAL ;
    PORT
      LAYER M5 ;
        RECT 22.320 0.000 22.344 0.192 ;
    END
  END d[351]
  PIN d[352]
    DIRECTION INPUT ;
    USE SIGNAL ;
    PORT
      LAYER M3 ;
        RECT 22.389 0.000 22.413 0.192 ;
    END
  END d[352]
  PIN d[353]
    DIRECTION INPUT ;
    USE SIGNAL ;
    PORT
      LAYER M5 ;
        RECT 22.416 0.000 22.440 0.192 ;
    END
  END d[353]
  PIN d[354]
    DIRECTION INPUT ;
    USE SIGNAL ;
    PORT
      LAYER M3 ;
        RECT 22.497 0.000 22.521 0.192 ;
    END
  END d[354]
  PIN d[355]
    DIRECTION INPUT ;
    USE SIGNAL ;
    PORT
      LAYER M5 ;
        RECT 22.560 0.000 22.584 0.192 ;
    END
  END d[355]
  PIN d[356]
    DIRECTION INPUT ;
    USE SIGNAL ;
    PORT
      LAYER M3 ;
        RECT 22.641 0.000 22.665 0.192 ;
    END
  END d[356]
  PIN d[357]
    DIRECTION INPUT ;
    USE SIGNAL ;
    PORT
      LAYER M5 ;
        RECT 22.704 0.000 22.728 0.192 ;
    END
  END d[357]
  PIN d[358]
    DIRECTION INPUT ;
    USE SIGNAL ;
    PORT
      LAYER M3 ;
        RECT 22.749 0.000 22.773 0.192 ;
    END
  END d[358]
  PIN d[359]
    DIRECTION INPUT ;
    USE SIGNAL ;
    PORT
      LAYER M5 ;
        RECT 22.800 0.000 22.824 0.192 ;
    END
  END d[359]
  PIN d[360]
    DIRECTION INPUT ;
    USE SIGNAL ;
    PORT
      LAYER M3 ;
        RECT 22.857 0.000 22.881 0.192 ;
    END
  END d[360]
  PIN d[361]
    DIRECTION INPUT ;
    USE SIGNAL ;
    PORT
      LAYER M5 ;
        RECT 22.944 0.000 22.968 0.192 ;
    END
  END d[361]
  PIN d[362]
    DIRECTION INPUT ;
    USE SIGNAL ;
    PORT
      LAYER M3 ;
        RECT 23.001 0.000 23.025 0.192 ;
    END
  END d[362]
  PIN d[363]
    DIRECTION INPUT ;
    USE SIGNAL ;
    PORT
      LAYER M5 ;
        RECT 23.040 0.000 23.064 0.192 ;
    END
  END d[363]
  PIN d[364]
    DIRECTION INPUT ;
    USE SIGNAL ;
    PORT
      LAYER M3 ;
        RECT 23.109 0.000 23.133 0.192 ;
    END
  END d[364]
  PIN d[365]
    DIRECTION INPUT ;
    USE SIGNAL ;
    PORT
      LAYER M5 ;
        RECT 23.184 0.000 23.208 0.192 ;
    END
  END d[365]
  PIN d[366]
    DIRECTION INPUT ;
    USE SIGNAL ;
    PORT
      LAYER M3 ;
        RECT 23.253 0.000 23.277 0.192 ;
    END
  END d[366]
  PIN d[367]
    DIRECTION INPUT ;
    USE SIGNAL ;
    PORT
      LAYER M5 ;
        RECT 23.328 0.000 23.352 0.192 ;
    END
  END d[367]
  PIN d[368]
    DIRECTION INPUT ;
    USE SIGNAL ;
    PORT
      LAYER M3 ;
        RECT 23.361 0.000 23.385 0.192 ;
    END
  END d[368]
  PIN d[369]
    DIRECTION INPUT ;
    USE SIGNAL ;
    PORT
      LAYER M5 ;
        RECT 23.424 0.000 23.448 0.192 ;
    END
  END d[369]
  PIN d[370]
    DIRECTION INPUT ;
    USE SIGNAL ;
    PORT
      LAYER M3 ;
        RECT 23.505 0.000 23.529 0.192 ;
    END
  END d[370]
  PIN d[371]
    DIRECTION INPUT ;
    USE SIGNAL ;
    PORT
      LAYER M5 ;
        RECT 23.568 0.000 23.592 0.192 ;
    END
  END d[371]
  PIN d[372]
    DIRECTION INPUT ;
    USE SIGNAL ;
    PORT
      LAYER M3 ;
        RECT 23.613 0.000 23.637 0.192 ;
    END
  END d[372]
  PIN d[373]
    DIRECTION INPUT ;
    USE SIGNAL ;
    PORT
      LAYER M5 ;
        RECT 23.664 0.000 23.688 0.192 ;
    END
  END d[373]
  PIN d[374]
    DIRECTION INPUT ;
    USE SIGNAL ;
    PORT
      LAYER M3 ;
        RECT 23.757 0.000 23.781 0.192 ;
    END
  END d[374]
  PIN d[375]
    DIRECTION INPUT ;
    USE SIGNAL ;
    PORT
      LAYER M5 ;
        RECT 23.808 0.000 23.832 0.192 ;
    END
  END d[375]
  PIN d[376]
    DIRECTION INPUT ;
    USE SIGNAL ;
    PORT
      LAYER M3 ;
        RECT 23.865 0.000 23.889 0.192 ;
    END
  END d[376]
  PIN d[377]
    DIRECTION INPUT ;
    USE SIGNAL ;
    PORT
      LAYER M5 ;
        RECT 23.904 0.000 23.928 0.192 ;
    END
  END d[377]
  PIN d[378]
    DIRECTION INPUT ;
    USE SIGNAL ;
    PORT
      LAYER M3 ;
        RECT 23.973 0.000 23.997 0.192 ;
    END
  END d[378]
  PIN d[379]
    DIRECTION INPUT ;
    USE SIGNAL ;
    PORT
      LAYER M5 ;
        RECT 24.048 0.000 24.072 0.192 ;
    END
  END d[379]
  PIN d[380]
    DIRECTION INPUT ;
    USE SIGNAL ;
    PORT
      LAYER M3 ;
        RECT 24.117 0.000 24.141 0.192 ;
    END
  END d[380]
  PIN d[381]
    DIRECTION INPUT ;
    USE SIGNAL ;
    PORT
      LAYER M5 ;
        RECT 24.192 0.000 24.216 0.192 ;
    END
  END d[381]
  PIN d[382]
    DIRECTION INPUT ;
    USE SIGNAL ;
    PORT
      LAYER M3 ;
        RECT 24.225 0.000 24.249 0.192 ;
    END
  END d[382]
  PIN d[383]
    DIRECTION INPUT ;
    USE SIGNAL ;
    PORT
      LAYER M5 ;
        RECT 24.288 0.000 24.312 0.192 ;
    END
  END d[383]
  PIN d[384]
    DIRECTION INPUT ;
    USE SIGNAL ;
    PORT
      LAYER M3 ;
        RECT 24.369 0.000 24.393 0.192 ;
    END
  END d[384]
  PIN d[385]
    DIRECTION INPUT ;
    USE SIGNAL ;
    PORT
      LAYER M5 ;
        RECT 24.432 0.000 24.456 0.192 ;
    END
  END d[385]
  PIN d[386]
    DIRECTION INPUT ;
    USE SIGNAL ;
    PORT
      LAYER M3 ;
        RECT 24.477 0.000 24.501 0.192 ;
    END
  END d[386]
  PIN d[387]
    DIRECTION INPUT ;
    USE SIGNAL ;
    PORT
      LAYER M5 ;
        RECT 24.528 0.000 24.552 0.192 ;
    END
  END d[387]
  PIN d[388]
    DIRECTION INPUT ;
    USE SIGNAL ;
    PORT
      LAYER M3 ;
        RECT 24.621 0.000 24.645 0.192 ;
    END
  END d[388]
  PIN d[389]
    DIRECTION INPUT ;
    USE SIGNAL ;
    PORT
      LAYER M5 ;
        RECT 24.672 0.000 24.696 0.192 ;
    END
  END d[389]
  PIN d[390]
    DIRECTION INPUT ;
    USE SIGNAL ;
    PORT
      LAYER M3 ;
        RECT 24.729 0.000 24.753 0.192 ;
    END
  END d[390]
  PIN d[391]
    DIRECTION INPUT ;
    USE SIGNAL ;
    PORT
      LAYER M5 ;
        RECT 24.816 0.000 24.840 0.192 ;
    END
  END d[391]
  PIN d[392]
    DIRECTION INPUT ;
    USE SIGNAL ;
    PORT
      LAYER M3 ;
        RECT 24.873 0.000 24.897 0.192 ;
    END
  END d[392]
  PIN d[393]
    DIRECTION INPUT ;
    USE SIGNAL ;
    PORT
      LAYER M5 ;
        RECT 24.912 0.000 24.936 0.192 ;
    END
  END d[393]
  PIN d[394]
    DIRECTION INPUT ;
    USE SIGNAL ;
    PORT
      LAYER M3 ;
        RECT 24.981 0.000 25.005 0.192 ;
    END
  END d[394]
  PIN d[395]
    DIRECTION INPUT ;
    USE SIGNAL ;
    PORT
      LAYER M5 ;
        RECT 25.056 0.000 25.080 0.192 ;
    END
  END d[395]
  PIN d[396]
    DIRECTION INPUT ;
    USE SIGNAL ;
    PORT
      LAYER M3 ;
        RECT 25.089 0.000 25.113 0.192 ;
    END
  END d[396]
  PIN d[397]
    DIRECTION INPUT ;
    USE SIGNAL ;
    PORT
      LAYER M5 ;
        RECT 25.152 0.000 25.176 0.192 ;
    END
  END d[397]
  PIN d[398]
    DIRECTION INPUT ;
    USE SIGNAL ;
    PORT
      LAYER M3 ;
        RECT 25.233 0.000 25.257 0.192 ;
    END
  END d[398]
  PIN d[399]
    DIRECTION INPUT ;
    USE SIGNAL ;
    PORT
      LAYER M5 ;
        RECT 25.296 0.000 25.320 0.192 ;
    END
  END d[399]
  PIN d[400]
    DIRECTION INPUT ;
    USE SIGNAL ;
    PORT
      LAYER M3 ;
        RECT 25.341 0.000 25.365 0.192 ;
    END
  END d[400]
  PIN d[401]
    DIRECTION INPUT ;
    USE SIGNAL ;
    PORT
      LAYER M5 ;
        RECT 25.392 0.000 25.416 0.192 ;
    END
  END d[401]
  PIN d[402]
    DIRECTION INPUT ;
    USE SIGNAL ;
    PORT
      LAYER M3 ;
        RECT 25.485 0.000 25.509 0.192 ;
    END
  END d[402]
  PIN d[403]
    DIRECTION INPUT ;
    USE SIGNAL ;
    PORT
      LAYER M5 ;
        RECT 25.536 0.000 25.560 0.192 ;
    END
  END d[403]
  PIN d[404]
    DIRECTION INPUT ;
    USE SIGNAL ;
    PORT
      LAYER M3 ;
        RECT 25.593 0.000 25.617 0.192 ;
    END
  END d[404]
  PIN d[405]
    DIRECTION INPUT ;
    USE SIGNAL ;
    PORT
      LAYER M5 ;
        RECT 25.680 0.000 25.704 0.192 ;
    END
  END d[405]
  PIN d[406]
    DIRECTION INPUT ;
    USE SIGNAL ;
    PORT
      LAYER M3 ;
        RECT 25.737 0.000 25.761 0.192 ;
    END
  END d[406]
  PIN d[407]
    DIRECTION INPUT ;
    USE SIGNAL ;
    PORT
      LAYER M5 ;
        RECT 25.776 0.000 25.800 0.192 ;
    END
  END d[407]
  PIN d[408]
    DIRECTION INPUT ;
    USE SIGNAL ;
    PORT
      LAYER M3 ;
        RECT 25.845 0.000 25.869 0.192 ;
    END
  END d[408]
  PIN d[409]
    DIRECTION INPUT ;
    USE SIGNAL ;
    PORT
      LAYER M5 ;
        RECT 25.920 0.000 25.944 0.192 ;
    END
  END d[409]
  PIN d[410]
    DIRECTION INPUT ;
    USE SIGNAL ;
    PORT
      LAYER M3 ;
        RECT 25.989 0.000 26.013 0.192 ;
    END
  END d[410]
  PIN d[411]
    DIRECTION INPUT ;
    USE SIGNAL ;
    PORT
      LAYER M5 ;
        RECT 26.016 0.000 26.040 0.192 ;
    END
  END d[411]
  PIN d[412]
    DIRECTION INPUT ;
    USE SIGNAL ;
    PORT
      LAYER M3 ;
        RECT 26.097 0.000 26.121 0.192 ;
    END
  END d[412]
  PIN d[413]
    DIRECTION INPUT ;
    USE SIGNAL ;
    PORT
      LAYER M5 ;
        RECT 26.160 0.000 26.184 0.192 ;
    END
  END d[413]
  PIN d[414]
    DIRECTION INPUT ;
    USE SIGNAL ;
    PORT
      LAYER M3 ;
        RECT 26.205 0.000 26.229 0.192 ;
    END
  END d[414]
  PIN d[415]
    DIRECTION INPUT ;
    USE SIGNAL ;
    PORT
      LAYER M5 ;
        RECT 26.304 0.000 26.328 0.192 ;
    END
  END d[415]
  PIN d[416]
    DIRECTION INPUT ;
    USE SIGNAL ;
    PORT
      LAYER M3 ;
        RECT 26.349 0.000 26.373 0.192 ;
    END
  END d[416]
  PIN d[417]
    DIRECTION INPUT ;
    USE SIGNAL ;
    PORT
      LAYER M5 ;
        RECT 26.400 0.000 26.424 0.192 ;
    END
  END d[417]
  PIN d[418]
    DIRECTION INPUT ;
    USE SIGNAL ;
    PORT
      LAYER M3 ;
        RECT 26.457 0.000 26.481 0.192 ;
    END
  END d[418]
  PIN d[419]
    DIRECTION INPUT ;
    USE SIGNAL ;
    PORT
      LAYER M5 ;
        RECT 26.544 0.000 26.568 0.192 ;
    END
  END d[419]
  PIN d[420]
    DIRECTION INPUT ;
    USE SIGNAL ;
    PORT
      LAYER M3 ;
        RECT 26.601 0.000 26.625 0.192 ;
    END
  END d[420]
  PIN d[421]
    DIRECTION INPUT ;
    USE SIGNAL ;
    PORT
      LAYER M5 ;
        RECT 26.640 0.000 26.664 0.192 ;
    END
  END d[421]
  PIN d[422]
    DIRECTION INPUT ;
    USE SIGNAL ;
    PORT
      LAYER M3 ;
        RECT 26.709 0.000 26.733 0.192 ;
    END
  END d[422]
  PIN d[423]
    DIRECTION INPUT ;
    USE SIGNAL ;
    PORT
      LAYER M5 ;
        RECT 26.784 0.000 26.808 0.192 ;
    END
  END d[423]
  PIN d[424]
    DIRECTION INPUT ;
    USE SIGNAL ;
    PORT
      LAYER M3 ;
        RECT 26.853 0.000 26.877 0.192 ;
    END
  END d[424]
  PIN d[425]
    DIRECTION INPUT ;
    USE SIGNAL ;
    PORT
      LAYER M5 ;
        RECT 26.880 0.000 26.904 0.192 ;
    END
  END d[425]
  PIN d[426]
    DIRECTION INPUT ;
    USE SIGNAL ;
    PORT
      LAYER M3 ;
        RECT 26.961 0.000 26.985 0.192 ;
    END
  END d[426]
  PIN d[427]
    DIRECTION INPUT ;
    USE SIGNAL ;
    PORT
      LAYER M5 ;
        RECT 27.024 0.000 27.048 0.192 ;
    END
  END d[427]
  PIN d[428]
    DIRECTION INPUT ;
    USE SIGNAL ;
    PORT
      LAYER M3 ;
        RECT 27.105 0.000 27.129 0.192 ;
    END
  END d[428]
  PIN d[429]
    DIRECTION INPUT ;
    USE SIGNAL ;
    PORT
      LAYER M5 ;
        RECT 27.168 0.000 27.192 0.192 ;
    END
  END d[429]
  PIN d[430]
    DIRECTION INPUT ;
    USE SIGNAL ;
    PORT
      LAYER M3 ;
        RECT 27.213 0.000 27.237 0.192 ;
    END
  END d[430]
  PIN d[431]
    DIRECTION INPUT ;
    USE SIGNAL ;
    PORT
      LAYER M5 ;
        RECT 27.264 0.000 27.288 0.192 ;
    END
  END d[431]
  PIN d[432]
    DIRECTION INPUT ;
    USE SIGNAL ;
    PORT
      LAYER M3 ;
        RECT 27.321 0.000 27.345 0.192 ;
    END
  END d[432]
  PIN d[433]
    DIRECTION INPUT ;
    USE SIGNAL ;
    PORT
      LAYER M5 ;
        RECT 27.408 0.000 27.432 0.192 ;
    END
  END d[433]
  PIN d[434]
    DIRECTION INPUT ;
    USE SIGNAL ;
    PORT
      LAYER M3 ;
        RECT 27.465 0.000 27.489 0.192 ;
    END
  END d[434]
  PIN d[435]
    DIRECTION INPUT ;
    USE SIGNAL ;
    PORT
      LAYER M5 ;
        RECT 27.504 0.000 27.528 0.192 ;
    END
  END d[435]
  PIN d[436]
    DIRECTION INPUT ;
    USE SIGNAL ;
    PORT
      LAYER M3 ;
        RECT 27.573 0.000 27.597 0.192 ;
    END
  END d[436]
  PIN d[437]
    DIRECTION INPUT ;
    USE SIGNAL ;
    PORT
      LAYER M5 ;
        RECT 27.648 0.000 27.672 0.192 ;
    END
  END d[437]
  PIN d[438]
    DIRECTION INPUT ;
    USE SIGNAL ;
    PORT
      LAYER M3 ;
        RECT 27.717 0.000 27.741 0.192 ;
    END
  END d[438]
  PIN d[439]
    DIRECTION INPUT ;
    USE SIGNAL ;
    PORT
      LAYER M5 ;
        RECT 27.792 0.000 27.816 0.192 ;
    END
  END d[439]
  PIN d[440]
    DIRECTION INPUT ;
    USE SIGNAL ;
    PORT
      LAYER M3 ;
        RECT 27.825 0.000 27.849 0.192 ;
    END
  END d[440]
  PIN d[441]
    DIRECTION INPUT ;
    USE SIGNAL ;
    PORT
      LAYER M5 ;
        RECT 27.888 0.000 27.912 0.192 ;
    END
  END d[441]
  PIN d[442]
    DIRECTION INPUT ;
    USE SIGNAL ;
    PORT
      LAYER M3 ;
        RECT 27.969 0.000 27.993 0.192 ;
    END
  END d[442]
  PIN d[443]
    DIRECTION INPUT ;
    USE SIGNAL ;
    PORT
      LAYER M5 ;
        RECT 28.032 0.000 28.056 0.192 ;
    END
  END d[443]
  PIN d[444]
    DIRECTION INPUT ;
    USE SIGNAL ;
    PORT
      LAYER M3 ;
        RECT 28.077 0.000 28.101 0.192 ;
    END
  END d[444]
  PIN d[445]
    DIRECTION INPUT ;
    USE SIGNAL ;
    PORT
      LAYER M5 ;
        RECT 28.128 0.000 28.152 0.192 ;
    END
  END d[445]
  PIN d[446]
    DIRECTION INPUT ;
    USE SIGNAL ;
    PORT
      LAYER M3 ;
        RECT 28.221 0.000 28.245 0.192 ;
    END
  END d[446]
  PIN d[447]
    DIRECTION INPUT ;
    USE SIGNAL ;
    PORT
      LAYER M5 ;
        RECT 28.272 0.000 28.296 0.192 ;
    END
  END d[447]
  PIN d[448]
    DIRECTION INPUT ;
    USE SIGNAL ;
    PORT
      LAYER M3 ;
        RECT 28.329 0.000 28.353 0.192 ;
    END
  END d[448]
  PIN d[449]
    DIRECTION INPUT ;
    USE SIGNAL ;
    PORT
      LAYER M5 ;
        RECT 28.368 0.000 28.392 0.192 ;
    END
  END d[449]
  PIN d[450]
    DIRECTION INPUT ;
    USE SIGNAL ;
    PORT
      LAYER M3 ;
        RECT 28.437 0.000 28.461 0.192 ;
    END
  END d[450]
  PIN d[451]
    DIRECTION INPUT ;
    USE SIGNAL ;
    PORT
      LAYER M5 ;
        RECT 28.512 0.000 28.536 0.192 ;
    END
  END d[451]
  PIN d[452]
    DIRECTION INPUT ;
    USE SIGNAL ;
    PORT
      LAYER M3 ;
        RECT 28.581 0.000 28.605 0.192 ;
    END
  END d[452]
  PIN d[453]
    DIRECTION INPUT ;
    USE SIGNAL ;
    PORT
      LAYER M5 ;
        RECT 28.656 0.000 28.680 0.192 ;
    END
  END d[453]
  PIN d[454]
    DIRECTION INPUT ;
    USE SIGNAL ;
    PORT
      LAYER M3 ;
        RECT 28.689 0.000 28.713 0.192 ;
    END
  END d[454]
  PIN d[455]
    DIRECTION INPUT ;
    USE SIGNAL ;
    PORT
      LAYER M5 ;
        RECT 28.752 0.000 28.776 0.192 ;
    END
  END d[455]
  PIN d[456]
    DIRECTION INPUT ;
    USE SIGNAL ;
    PORT
      LAYER M3 ;
        RECT 28.833 0.000 28.857 0.192 ;
    END
  END d[456]
  PIN d[457]
    DIRECTION INPUT ;
    USE SIGNAL ;
    PORT
      LAYER M5 ;
        RECT 28.896 0.000 28.920 0.192 ;
    END
  END d[457]
  PIN d[458]
    DIRECTION INPUT ;
    USE SIGNAL ;
    PORT
      LAYER M3 ;
        RECT 28.941 0.000 28.965 0.192 ;
    END
  END d[458]
  PIN d[459]
    DIRECTION INPUT ;
    USE SIGNAL ;
    PORT
      LAYER M5 ;
        RECT 28.992 0.000 29.016 0.192 ;
    END
  END d[459]
  PIN d[460]
    DIRECTION INPUT ;
    USE SIGNAL ;
    PORT
      LAYER M3 ;
        RECT 29.085 0.000 29.109 0.192 ;
    END
  END d[460]
  PIN d[461]
    DIRECTION INPUT ;
    USE SIGNAL ;
    PORT
      LAYER M5 ;
        RECT 29.136 0.000 29.160 0.192 ;
    END
  END d[461]
  PIN d[462]
    DIRECTION INPUT ;
    USE SIGNAL ;
    PORT
      LAYER M3 ;
        RECT 29.193 0.000 29.217 0.192 ;
    END
  END d[462]
  PIN d[463]
    DIRECTION INPUT ;
    USE SIGNAL ;
    PORT
      LAYER M5 ;
        RECT 29.280 0.000 29.304 0.192 ;
    END
  END d[463]
  PIN d[464]
    DIRECTION INPUT ;
    USE SIGNAL ;
    PORT
      LAYER M3 ;
        RECT 29.337 0.000 29.361 0.192 ;
    END
  END d[464]
  PIN d[465]
    DIRECTION INPUT ;
    USE SIGNAL ;
    PORT
      LAYER M5 ;
        RECT 29.376 0.000 29.400 0.192 ;
    END
  END d[465]
  PIN d[466]
    DIRECTION INPUT ;
    USE SIGNAL ;
    PORT
      LAYER M3 ;
        RECT 29.445 0.000 29.469 0.192 ;
    END
  END d[466]
  PIN d[467]
    DIRECTION INPUT ;
    USE SIGNAL ;
    PORT
      LAYER M5 ;
        RECT 29.520 0.000 29.544 0.192 ;
    END
  END d[467]
  PIN d[468]
    DIRECTION INPUT ;
    USE SIGNAL ;
    PORT
      LAYER M3 ;
        RECT 29.553 0.000 29.577 0.192 ;
    END
  END d[468]
  PIN d[469]
    DIRECTION INPUT ;
    USE SIGNAL ;
    PORT
      LAYER M5 ;
        RECT 29.616 0.000 29.640 0.192 ;
    END
  END d[469]
  PIN d[470]
    DIRECTION INPUT ;
    USE SIGNAL ;
    PORT
      LAYER M3 ;
        RECT 29.697 0.000 29.721 0.192 ;
    END
  END d[470]
  PIN d[471]
    DIRECTION INPUT ;
    USE SIGNAL ;
    PORT
      LAYER M5 ;
        RECT 29.760 0.000 29.784 0.192 ;
    END
  END d[471]
  PIN d[472]
    DIRECTION INPUT ;
    USE SIGNAL ;
    PORT
      LAYER M3 ;
        RECT 29.805 0.000 29.829 0.192 ;
    END
  END d[472]
  PIN d[473]
    DIRECTION INPUT ;
    USE SIGNAL ;
    PORT
      LAYER M5 ;
        RECT 29.856 0.000 29.880 0.192 ;
    END
  END d[473]
  PIN d[474]
    DIRECTION INPUT ;
    USE SIGNAL ;
    PORT
      LAYER M3 ;
        RECT 29.949 0.000 29.973 0.192 ;
    END
  END d[474]
  PIN d[475]
    DIRECTION INPUT ;
    USE SIGNAL ;
    PORT
      LAYER M5 ;
        RECT 30.000 0.000 30.024 0.192 ;
    END
  END d[475]
  PIN d[476]
    DIRECTION INPUT ;
    USE SIGNAL ;
    PORT
      LAYER M3 ;
        RECT 30.057 0.000 30.081 0.192 ;
    END
  END d[476]
  PIN d[477]
    DIRECTION INPUT ;
    USE SIGNAL ;
    PORT
      LAYER M5 ;
        RECT 30.144 0.000 30.168 0.192 ;
    END
  END d[477]
  PIN d[478]
    DIRECTION INPUT ;
    USE SIGNAL ;
    PORT
      LAYER M3 ;
        RECT 30.201 0.000 30.225 0.192 ;
    END
  END d[478]
  PIN d[479]
    DIRECTION INPUT ;
    USE SIGNAL ;
    PORT
      LAYER M5 ;
        RECT 30.240 0.000 30.264 0.192 ;
    END
  END d[479]
  PIN d[480]
    DIRECTION INPUT ;
    USE SIGNAL ;
    PORT
      LAYER M3 ;
        RECT 30.309 0.000 30.333 0.192 ;
    END
  END d[480]
  PIN d[481]
    DIRECTION INPUT ;
    USE SIGNAL ;
    PORT
      LAYER M5 ;
        RECT 30.384 0.000 30.408 0.192 ;
    END
  END d[481]
  PIN d[482]
    DIRECTION INPUT ;
    USE SIGNAL ;
    PORT
      LAYER M3 ;
        RECT 30.453 0.000 30.477 0.192 ;
    END
  END d[482]
  PIN d[483]
    DIRECTION INPUT ;
    USE SIGNAL ;
    PORT
      LAYER M5 ;
        RECT 30.480 0.000 30.504 0.192 ;
    END
  END d[483]
  PIN d[484]
    DIRECTION INPUT ;
    USE SIGNAL ;
    PORT
      LAYER M3 ;
        RECT 30.561 0.000 30.585 0.192 ;
    END
  END d[484]
  PIN d[485]
    DIRECTION INPUT ;
    USE SIGNAL ;
    PORT
      LAYER M5 ;
        RECT 30.624 0.000 30.648 0.192 ;
    END
  END d[485]
  PIN d[486]
    DIRECTION INPUT ;
    USE SIGNAL ;
    PORT
      LAYER M3 ;
        RECT 30.669 0.000 30.693 0.192 ;
    END
  END d[486]
  PIN d[487]
    DIRECTION INPUT ;
    USE SIGNAL ;
    PORT
      LAYER M5 ;
        RECT 30.768 0.000 30.792 0.192 ;
    END
  END d[487]
  PIN d[488]
    DIRECTION INPUT ;
    USE SIGNAL ;
    PORT
      LAYER M3 ;
        RECT 30.813 0.000 30.837 0.192 ;
    END
  END d[488]
  PIN d[489]
    DIRECTION INPUT ;
    USE SIGNAL ;
    PORT
      LAYER M5 ;
        RECT 30.864 0.000 30.888 0.192 ;
    END
  END d[489]
  PIN d[490]
    DIRECTION INPUT ;
    USE SIGNAL ;
    PORT
      LAYER M3 ;
        RECT 30.921 0.000 30.945 0.192 ;
    END
  END d[490]
  PIN d[491]
    DIRECTION INPUT ;
    USE SIGNAL ;
    PORT
      LAYER M5 ;
        RECT 31.008 0.000 31.032 0.192 ;
    END
  END d[491]
  PIN d[492]
    DIRECTION INPUT ;
    USE SIGNAL ;
    PORT
      LAYER M3 ;
        RECT 31.065 0.000 31.089 0.192 ;
    END
  END d[492]
  PIN d[493]
    DIRECTION INPUT ;
    USE SIGNAL ;
    PORT
      LAYER M5 ;
        RECT 31.104 0.000 31.128 0.192 ;
    END
  END d[493]
  PIN d[494]
    DIRECTION INPUT ;
    USE SIGNAL ;
    PORT
      LAYER M3 ;
        RECT 31.173 0.000 31.197 0.192 ;
    END
  END d[494]
  PIN d[495]
    DIRECTION INPUT ;
    USE SIGNAL ;
    PORT
      LAYER M5 ;
        RECT 31.248 0.000 31.272 0.192 ;
    END
  END d[495]
  PIN d[496]
    DIRECTION INPUT ;
    USE SIGNAL ;
    PORT
      LAYER M3 ;
        RECT 31.317 0.000 31.341 0.192 ;
    END
  END d[496]
  PIN d[497]
    DIRECTION INPUT ;
    USE SIGNAL ;
    PORT
      LAYER M5 ;
        RECT 31.344 0.000 31.368 0.192 ;
    END
  END d[497]
  PIN d[498]
    DIRECTION INPUT ;
    USE SIGNAL ;
    PORT
      LAYER M3 ;
        RECT 31.425 0.000 31.449 0.192 ;
    END
  END d[498]
  PIN d[499]
    DIRECTION INPUT ;
    USE SIGNAL ;
    PORT
      LAYER M5 ;
        RECT 31.488 0.000 31.512 0.192 ;
    END
  END d[499]
  PIN d[500]
    DIRECTION INPUT ;
    USE SIGNAL ;
    PORT
      LAYER M3 ;
        RECT 31.569 0.000 31.593 0.192 ;
    END
  END d[500]
  PIN d[501]
    DIRECTION INPUT ;
    USE SIGNAL ;
    PORT
      LAYER M5 ;
        RECT 31.632 0.000 31.656 0.192 ;
    END
  END d[501]
  PIN d[502]
    DIRECTION INPUT ;
    USE SIGNAL ;
    PORT
      LAYER M3 ;
        RECT 31.677 0.000 31.701 0.192 ;
    END
  END d[502]
  PIN d[503]
    DIRECTION INPUT ;
    USE SIGNAL ;
    PORT
      LAYER M5 ;
        RECT 31.728 0.000 31.752 0.192 ;
    END
  END d[503]
  PIN d[504]
    DIRECTION INPUT ;
    USE SIGNAL ;
    PORT
      LAYER M3 ;
        RECT 31.785 0.000 31.809 0.192 ;
    END
  END d[504]
  PIN d[505]
    DIRECTION INPUT ;
    USE SIGNAL ;
    PORT
      LAYER M5 ;
        RECT 31.872 0.000 31.896 0.192 ;
    END
  END d[505]
  PIN d[506]
    DIRECTION INPUT ;
    USE SIGNAL ;
    PORT
      LAYER M3 ;
        RECT 31.929 0.000 31.953 0.192 ;
    END
  END d[506]
  PIN d[507]
    DIRECTION INPUT ;
    USE SIGNAL ;
    PORT
      LAYER M5 ;
        RECT 31.968 0.000 31.992 0.192 ;
    END
  END d[507]
  PIN d[508]
    DIRECTION INPUT ;
    USE SIGNAL ;
    PORT
      LAYER M3 ;
        RECT 32.037 0.000 32.061 0.192 ;
    END
  END d[508]
  PIN d[509]
    DIRECTION INPUT ;
    USE SIGNAL ;
    PORT
      LAYER M5 ;
        RECT 32.112 0.000 32.136 0.192 ;
    END
  END d[509]
  PIN d[510]
    DIRECTION INPUT ;
    USE SIGNAL ;
    PORT
      LAYER M3 ;
        RECT 32.181 0.000 32.205 0.192 ;
    END
  END d[510]
  PIN d[511]
    DIRECTION INPUT ;
    USE SIGNAL ;
    PORT
      LAYER M5 ;
        RECT 32.256 0.000 32.280 0.192 ;
    END
  END d[511]
  PIN d[512]
    DIRECTION INPUT ;
    USE SIGNAL ;
    PORT
      LAYER M3 ;
        RECT 32.289 0.000 32.313 0.192 ;
    END
  END d[512]
  PIN d[513]
    DIRECTION INPUT ;
    USE SIGNAL ;
    PORT
      LAYER M5 ;
        RECT 32.352 0.000 32.376 0.192 ;
    END
  END d[513]
  PIN ck
    DIRECTION INPUT ;
    USE CLOCK ;
    PORT
      LAYER M5 ;
        RECT 33.264 0.000 33.288 0.192 ;
    END
  END ck
  PIN q[0]
    DIRECTION OUTPUT ;
    USE SIGNAL ;
    PORT
      LAYER M3 ;
        RECT 0.573 34.368 0.597 34.560 ;
    END
  END q[0]
  PIN q[1]
    DIRECTION OUTPUT ;
    USE SIGNAL ;
    PORT
      LAYER M5 ;
        RECT 0.624 34.368 0.648 34.560 ;
    END
  END q[1]
  PIN q[2]
    DIRECTION OUTPUT ;
    USE SIGNAL ;
    PORT
      LAYER M3 ;
        RECT 0.681 34.368 0.705 34.560 ;
    END
  END q[2]
  PIN q[3]
    DIRECTION OUTPUT ;
    USE SIGNAL ;
    PORT
      LAYER M5 ;
        RECT 0.768 34.368 0.792 34.560 ;
    END
  END q[3]
  PIN q[4]
    DIRECTION OUTPUT ;
    USE SIGNAL ;
    PORT
      LAYER M3 ;
        RECT 0.825 34.368 0.849 34.560 ;
    END
  END q[4]
  PIN q[5]
    DIRECTION OUTPUT ;
    USE SIGNAL ;
    PORT
      LAYER M5 ;
        RECT 0.864 34.368 0.888 34.560 ;
    END
  END q[5]
  PIN q[6]
    DIRECTION OUTPUT ;
    USE SIGNAL ;
    PORT
      LAYER M3 ;
        RECT 0.969 34.368 0.993 34.560 ;
    END
  END q[6]
  PIN q[7]
    DIRECTION OUTPUT ;
    USE SIGNAL ;
    PORT
      LAYER M5 ;
        RECT 1.008 34.368 1.032 34.560 ;
    END
  END q[7]
  PIN q[8]
    DIRECTION OUTPUT ;
    USE SIGNAL ;
    PORT
      LAYER M3 ;
        RECT 1.077 34.368 1.101 34.560 ;
    END
  END q[8]
  PIN q[9]
    DIRECTION OUTPUT ;
    USE SIGNAL ;
    PORT
      LAYER M5 ;
        RECT 1.152 34.368 1.176 34.560 ;
    END
  END q[9]
  PIN q[10]
    DIRECTION OUTPUT ;
    USE SIGNAL ;
    PORT
      LAYER M3 ;
        RECT 1.221 34.368 1.245 34.560 ;
    END
  END q[10]
  PIN q[11]
    DIRECTION OUTPUT ;
    USE SIGNAL ;
    PORT
      LAYER M5 ;
        RECT 1.296 34.368 1.320 34.560 ;
    END
  END q[11]
  PIN q[12]
    DIRECTION OUTPUT ;
    USE SIGNAL ;
    PORT
      LAYER M3 ;
        RECT 1.329 34.368 1.353 34.560 ;
    END
  END q[12]
  PIN q[13]
    DIRECTION OUTPUT ;
    USE SIGNAL ;
    PORT
      LAYER M5 ;
        RECT 1.392 34.368 1.416 34.560 ;
    END
  END q[13]
  PIN q[14]
    DIRECTION OUTPUT ;
    USE SIGNAL ;
    PORT
      LAYER M3 ;
        RECT 1.473 34.368 1.497 34.560 ;
    END
  END q[14]
  PIN q[15]
    DIRECTION OUTPUT ;
    USE SIGNAL ;
    PORT
      LAYER M5 ;
        RECT 1.536 34.368 1.560 34.560 ;
    END
  END q[15]
  PIN q[16]
    DIRECTION OUTPUT ;
    USE SIGNAL ;
    PORT
      LAYER M3 ;
        RECT 1.617 34.368 1.641 34.560 ;
    END
  END q[16]
  PIN q[17]
    DIRECTION OUTPUT ;
    USE SIGNAL ;
    PORT
      LAYER M5 ;
        RECT 1.680 34.368 1.704 34.560 ;
    END
  END q[17]
  PIN q[18]
    DIRECTION OUTPUT ;
    USE SIGNAL ;
    PORT
      LAYER M3 ;
        RECT 1.725 34.368 1.749 34.560 ;
    END
  END q[18]
  PIN q[19]
    DIRECTION OUTPUT ;
    USE SIGNAL ;
    PORT
      LAYER M5 ;
        RECT 1.776 34.368 1.800 34.560 ;
    END
  END q[19]
  PIN q[20]
    DIRECTION OUTPUT ;
    USE SIGNAL ;
    PORT
      LAYER M3 ;
        RECT 1.869 34.368 1.893 34.560 ;
    END
  END q[20]
  PIN q[21]
    DIRECTION OUTPUT ;
    USE SIGNAL ;
    PORT
      LAYER M5 ;
        RECT 1.920 34.368 1.944 34.560 ;
    END
  END q[21]
  PIN q[22]
    DIRECTION OUTPUT ;
    USE SIGNAL ;
    PORT
      LAYER M3 ;
        RECT 1.977 34.368 2.001 34.560 ;
    END
  END q[22]
  PIN q[23]
    DIRECTION OUTPUT ;
    USE SIGNAL ;
    PORT
      LAYER M5 ;
        RECT 2.064 34.368 2.088 34.560 ;
    END
  END q[23]
  PIN q[24]
    DIRECTION OUTPUT ;
    USE SIGNAL ;
    PORT
      LAYER M3 ;
        RECT 2.121 34.368 2.145 34.560 ;
    END
  END q[24]
  PIN q[25]
    DIRECTION OUTPUT ;
    USE SIGNAL ;
    PORT
      LAYER M5 ;
        RECT 2.208 34.368 2.232 34.560 ;
    END
  END q[25]
  PIN q[26]
    DIRECTION OUTPUT ;
    USE SIGNAL ;
    PORT
      LAYER M3 ;
        RECT 2.265 34.368 2.289 34.560 ;
    END
  END q[26]
  PIN q[27]
    DIRECTION OUTPUT ;
    USE SIGNAL ;
    PORT
      LAYER M5 ;
        RECT 2.304 34.368 2.328 34.560 ;
    END
  END q[27]
  PIN q[28]
    DIRECTION OUTPUT ;
    USE SIGNAL ;
    PORT
      LAYER M3 ;
        RECT 2.373 34.368 2.397 34.560 ;
    END
  END q[28]
  PIN q[29]
    DIRECTION OUTPUT ;
    USE SIGNAL ;
    PORT
      LAYER M5 ;
        RECT 2.448 34.368 2.472 34.560 ;
    END
  END q[29]
  PIN q[30]
    DIRECTION OUTPUT ;
    USE SIGNAL ;
    PORT
      LAYER M3 ;
        RECT 2.517 34.368 2.541 34.560 ;
    END
  END q[30]
  PIN q[31]
    DIRECTION OUTPUT ;
    USE SIGNAL ;
    PORT
      LAYER M5 ;
        RECT 2.592 34.368 2.616 34.560 ;
    END
  END q[31]
  PIN q[32]
    DIRECTION OUTPUT ;
    USE SIGNAL ;
    PORT
      LAYER M3 ;
        RECT 2.661 34.368 2.685 34.560 ;
    END
  END q[32]
  PIN q[33]
    DIRECTION OUTPUT ;
    USE SIGNAL ;
    PORT
      LAYER M5 ;
        RECT 2.688 34.368 2.712 34.560 ;
    END
  END q[33]
  PIN q[34]
    DIRECTION OUTPUT ;
    USE SIGNAL ;
    PORT
      LAYER M3 ;
        RECT 2.769 34.368 2.793 34.560 ;
    END
  END q[34]
  PIN q[35]
    DIRECTION OUTPUT ;
    USE SIGNAL ;
    PORT
      LAYER M5 ;
        RECT 2.832 34.368 2.856 34.560 ;
    END
  END q[35]
  PIN q[36]
    DIRECTION OUTPUT ;
    USE SIGNAL ;
    PORT
      LAYER M3 ;
        RECT 2.913 34.368 2.937 34.560 ;
    END
  END q[36]
  PIN q[37]
    DIRECTION OUTPUT ;
    USE SIGNAL ;
    PORT
      LAYER M5 ;
        RECT 2.976 34.368 3.000 34.560 ;
    END
  END q[37]
  PIN q[38]
    DIRECTION OUTPUT ;
    USE SIGNAL ;
    PORT
      LAYER M3 ;
        RECT 3.021 34.368 3.045 34.560 ;
    END
  END q[38]
  PIN q[39]
    DIRECTION OUTPUT ;
    USE SIGNAL ;
    PORT
      LAYER M5 ;
        RECT 3.120 34.368 3.144 34.560 ;
    END
  END q[39]
  PIN q[40]
    DIRECTION OUTPUT ;
    USE SIGNAL ;
    PORT
      LAYER M3 ;
        RECT 3.165 34.368 3.189 34.560 ;
    END
  END q[40]
  PIN q[41]
    DIRECTION OUTPUT ;
    USE SIGNAL ;
    PORT
      LAYER M5 ;
        RECT 3.216 34.368 3.240 34.560 ;
    END
  END q[41]
  PIN q[42]
    DIRECTION OUTPUT ;
    USE SIGNAL ;
    PORT
      LAYER M3 ;
        RECT 3.309 34.368 3.333 34.560 ;
    END
  END q[42]
  PIN q[43]
    DIRECTION OUTPUT ;
    USE SIGNAL ;
    PORT
      LAYER M5 ;
        RECT 3.360 34.368 3.384 34.560 ;
    END
  END q[43]
  PIN q[44]
    DIRECTION OUTPUT ;
    USE SIGNAL ;
    PORT
      LAYER M3 ;
        RECT 3.417 34.368 3.441 34.560 ;
    END
  END q[44]
  PIN q[45]
    DIRECTION OUTPUT ;
    USE SIGNAL ;
    PORT
      LAYER M5 ;
        RECT 3.504 34.368 3.528 34.560 ;
    END
  END q[45]
  PIN q[46]
    DIRECTION OUTPUT ;
    USE SIGNAL ;
    PORT
      LAYER M3 ;
        RECT 3.561 34.368 3.585 34.560 ;
    END
  END q[46]
  PIN q[47]
    DIRECTION OUTPUT ;
    USE SIGNAL ;
    PORT
      LAYER M5 ;
        RECT 3.600 34.368 3.624 34.560 ;
    END
  END q[47]
  PIN q[48]
    DIRECTION OUTPUT ;
    USE SIGNAL ;
    PORT
      LAYER M3 ;
        RECT 3.705 34.368 3.729 34.560 ;
    END
  END q[48]
  PIN q[49]
    DIRECTION OUTPUT ;
    USE SIGNAL ;
    PORT
      LAYER M5 ;
        RECT 3.744 34.368 3.768 34.560 ;
    END
  END q[49]
  PIN q[50]
    DIRECTION OUTPUT ;
    USE SIGNAL ;
    PORT
      LAYER M3 ;
        RECT 3.813 34.368 3.837 34.560 ;
    END
  END q[50]
  PIN q[51]
    DIRECTION OUTPUT ;
    USE SIGNAL ;
    PORT
      LAYER M5 ;
        RECT 3.888 34.368 3.912 34.560 ;
    END
  END q[51]
  PIN q[52]
    DIRECTION OUTPUT ;
    USE SIGNAL ;
    PORT
      LAYER M3 ;
        RECT 3.957 34.368 3.981 34.560 ;
    END
  END q[52]
  PIN q[53]
    DIRECTION OUTPUT ;
    USE SIGNAL ;
    PORT
      LAYER M5 ;
        RECT 4.032 34.368 4.056 34.560 ;
    END
  END q[53]
  PIN q[54]
    DIRECTION OUTPUT ;
    USE SIGNAL ;
    PORT
      LAYER M3 ;
        RECT 4.065 34.368 4.089 34.560 ;
    END
  END q[54]
  PIN q[55]
    DIRECTION OUTPUT ;
    USE SIGNAL ;
    PORT
      LAYER M5 ;
        RECT 4.128 34.368 4.152 34.560 ;
    END
  END q[55]
  PIN q[56]
    DIRECTION OUTPUT ;
    USE SIGNAL ;
    PORT
      LAYER M3 ;
        RECT 4.209 34.368 4.233 34.560 ;
    END
  END q[56]
  PIN q[57]
    DIRECTION OUTPUT ;
    USE SIGNAL ;
    PORT
      LAYER M5 ;
        RECT 4.272 34.368 4.296 34.560 ;
    END
  END q[57]
  PIN q[58]
    DIRECTION OUTPUT ;
    USE SIGNAL ;
    PORT
      LAYER M3 ;
        RECT 4.353 34.368 4.377 34.560 ;
    END
  END q[58]
  PIN q[59]
    DIRECTION OUTPUT ;
    USE SIGNAL ;
    PORT
      LAYER M5 ;
        RECT 4.416 34.368 4.440 34.560 ;
    END
  END q[59]
  PIN q[60]
    DIRECTION OUTPUT ;
    USE SIGNAL ;
    PORT
      LAYER M3 ;
        RECT 4.461 34.368 4.485 34.560 ;
    END
  END q[60]
  PIN q[61]
    DIRECTION OUTPUT ;
    USE SIGNAL ;
    PORT
      LAYER M5 ;
        RECT 4.512 34.368 4.536 34.560 ;
    END
  END q[61]
  PIN q[62]
    DIRECTION OUTPUT ;
    USE SIGNAL ;
    PORT
      LAYER M3 ;
        RECT 4.605 34.368 4.629 34.560 ;
    END
  END q[62]
  PIN q[63]
    DIRECTION OUTPUT ;
    USE SIGNAL ;
    PORT
      LAYER M5 ;
        RECT 4.656 34.368 4.680 34.560 ;
    END
  END q[63]
  PIN q[64]
    DIRECTION OUTPUT ;
    USE SIGNAL ;
    PORT
      LAYER M3 ;
        RECT 4.713 34.368 4.737 34.560 ;
    END
  END q[64]
  PIN q[65]
    DIRECTION OUTPUT ;
    USE SIGNAL ;
    PORT
      LAYER M5 ;
        RECT 4.800 34.368 4.824 34.560 ;
    END
  END q[65]
  PIN q[66]
    DIRECTION OUTPUT ;
    USE SIGNAL ;
    PORT
      LAYER M3 ;
        RECT 4.857 34.368 4.881 34.560 ;
    END
  END q[66]
  PIN q[67]
    DIRECTION OUTPUT ;
    USE SIGNAL ;
    PORT
      LAYER M5 ;
        RECT 4.944 34.368 4.968 34.560 ;
    END
  END q[67]
  PIN q[68]
    DIRECTION OUTPUT ;
    USE SIGNAL ;
    PORT
      LAYER M3 ;
        RECT 5.001 34.368 5.025 34.560 ;
    END
  END q[68]
  PIN q[69]
    DIRECTION OUTPUT ;
    USE SIGNAL ;
    PORT
      LAYER M5 ;
        RECT 5.040 34.368 5.064 34.560 ;
    END
  END q[69]
  PIN q[70]
    DIRECTION OUTPUT ;
    USE SIGNAL ;
    PORT
      LAYER M3 ;
        RECT 5.109 34.368 5.133 34.560 ;
    END
  END q[70]
  PIN q[71]
    DIRECTION OUTPUT ;
    USE SIGNAL ;
    PORT
      LAYER M5 ;
        RECT 5.184 34.368 5.208 34.560 ;
    END
  END q[71]
  PIN q[72]
    DIRECTION OUTPUT ;
    USE SIGNAL ;
    PORT
      LAYER M3 ;
        RECT 5.253 34.368 5.277 34.560 ;
    END
  END q[72]
  PIN q[73]
    DIRECTION OUTPUT ;
    USE SIGNAL ;
    PORT
      LAYER M5 ;
        RECT 5.328 34.368 5.352 34.560 ;
    END
  END q[73]
  PIN q[74]
    DIRECTION OUTPUT ;
    USE SIGNAL ;
    PORT
      LAYER M3 ;
        RECT 5.397 34.368 5.421 34.560 ;
    END
  END q[74]
  PIN q[75]
    DIRECTION OUTPUT ;
    USE SIGNAL ;
    PORT
      LAYER M5 ;
        RECT 5.424 34.368 5.448 34.560 ;
    END
  END q[75]
  PIN q[76]
    DIRECTION OUTPUT ;
    USE SIGNAL ;
    PORT
      LAYER M3 ;
        RECT 5.505 34.368 5.529 34.560 ;
    END
  END q[76]
  PIN q[77]
    DIRECTION OUTPUT ;
    USE SIGNAL ;
    PORT
      LAYER M5 ;
        RECT 5.568 34.368 5.592 34.560 ;
    END
  END q[77]
  PIN q[78]
    DIRECTION OUTPUT ;
    USE SIGNAL ;
    PORT
      LAYER M3 ;
        RECT 5.649 34.368 5.673 34.560 ;
    END
  END q[78]
  PIN q[79]
    DIRECTION OUTPUT ;
    USE SIGNAL ;
    PORT
      LAYER M5 ;
        RECT 5.712 34.368 5.736 34.560 ;
    END
  END q[79]
  PIN q[80]
    DIRECTION OUTPUT ;
    USE SIGNAL ;
    PORT
      LAYER M3 ;
        RECT 5.757 34.368 5.781 34.560 ;
    END
  END q[80]
  PIN q[81]
    DIRECTION OUTPUT ;
    USE SIGNAL ;
    PORT
      LAYER M5 ;
        RECT 5.856 34.368 5.880 34.560 ;
    END
  END q[81]
  PIN q[82]
    DIRECTION OUTPUT ;
    USE SIGNAL ;
    PORT
      LAYER M3 ;
        RECT 5.901 34.368 5.925 34.560 ;
    END
  END q[82]
  PIN q[83]
    DIRECTION OUTPUT ;
    USE SIGNAL ;
    PORT
      LAYER M5 ;
        RECT 5.952 34.368 5.976 34.560 ;
    END
  END q[83]
  PIN q[84]
    DIRECTION OUTPUT ;
    USE SIGNAL ;
    PORT
      LAYER M3 ;
        RECT 6.045 34.368 6.069 34.560 ;
    END
  END q[84]
  PIN q[85]
    DIRECTION OUTPUT ;
    USE SIGNAL ;
    PORT
      LAYER M5 ;
        RECT 6.096 34.368 6.120 34.560 ;
    END
  END q[85]
  PIN q[86]
    DIRECTION OUTPUT ;
    USE SIGNAL ;
    PORT
      LAYER M3 ;
        RECT 6.153 34.368 6.177 34.560 ;
    END
  END q[86]
  PIN q[87]
    DIRECTION OUTPUT ;
    USE SIGNAL ;
    PORT
      LAYER M5 ;
        RECT 6.240 34.368 6.264 34.560 ;
    END
  END q[87]
  PIN q[88]
    DIRECTION OUTPUT ;
    USE SIGNAL ;
    PORT
      LAYER M3 ;
        RECT 6.297 34.368 6.321 34.560 ;
    END
  END q[88]
  PIN q[89]
    DIRECTION OUTPUT ;
    USE SIGNAL ;
    PORT
      LAYER M5 ;
        RECT 6.336 34.368 6.360 34.560 ;
    END
  END q[89]
  PIN q[90]
    DIRECTION OUTPUT ;
    USE SIGNAL ;
    PORT
      LAYER M3 ;
        RECT 6.405 34.368 6.429 34.560 ;
    END
  END q[90]
  PIN q[91]
    DIRECTION OUTPUT ;
    USE SIGNAL ;
    PORT
      LAYER M5 ;
        RECT 6.480 34.368 6.504 34.560 ;
    END
  END q[91]
  PIN q[92]
    DIRECTION OUTPUT ;
    USE SIGNAL ;
    PORT
      LAYER M3 ;
        RECT 6.549 34.368 6.573 34.560 ;
    END
  END q[92]
  PIN q[93]
    DIRECTION OUTPUT ;
    USE SIGNAL ;
    PORT
      LAYER M5 ;
        RECT 6.624 34.368 6.648 34.560 ;
    END
  END q[93]
  PIN q[94]
    DIRECTION OUTPUT ;
    USE SIGNAL ;
    PORT
      LAYER M3 ;
        RECT 6.693 34.368 6.717 34.560 ;
    END
  END q[94]
  PIN q[95]
    DIRECTION OUTPUT ;
    USE SIGNAL ;
    PORT
      LAYER M5 ;
        RECT 6.768 34.368 6.792 34.560 ;
    END
  END q[95]
  PIN q[96]
    DIRECTION OUTPUT ;
    USE SIGNAL ;
    PORT
      LAYER M3 ;
        RECT 6.801 34.368 6.825 34.560 ;
    END
  END q[96]
  PIN q[97]
    DIRECTION OUTPUT ;
    USE SIGNAL ;
    PORT
      LAYER M5 ;
        RECT 6.864 34.368 6.888 34.560 ;
    END
  END q[97]
  PIN q[98]
    DIRECTION OUTPUT ;
    USE SIGNAL ;
    PORT
      LAYER M3 ;
        RECT 6.945 34.368 6.969 34.560 ;
    END
  END q[98]
  PIN q[99]
    DIRECTION OUTPUT ;
    USE SIGNAL ;
    PORT
      LAYER M5 ;
        RECT 7.008 34.368 7.032 34.560 ;
    END
  END q[99]
  PIN q[100]
    DIRECTION OUTPUT ;
    USE SIGNAL ;
    PORT
      LAYER M3 ;
        RECT 7.089 34.368 7.113 34.560 ;
    END
  END q[100]
  PIN q[101]
    DIRECTION OUTPUT ;
    USE SIGNAL ;
    PORT
      LAYER M5 ;
        RECT 7.152 34.368 7.176 34.560 ;
    END
  END q[101]
  PIN q[102]
    DIRECTION OUTPUT ;
    USE SIGNAL ;
    PORT
      LAYER M3 ;
        RECT 7.197 34.368 7.221 34.560 ;
    END
  END q[102]
  PIN q[103]
    DIRECTION OUTPUT ;
    USE SIGNAL ;
    PORT
      LAYER M5 ;
        RECT 7.248 34.368 7.272 34.560 ;
    END
  END q[103]
  PIN q[104]
    DIRECTION OUTPUT ;
    USE SIGNAL ;
    PORT
      LAYER M3 ;
        RECT 7.341 34.368 7.365 34.560 ;
    END
  END q[104]
  PIN q[105]
    DIRECTION OUTPUT ;
    USE SIGNAL ;
    PORT
      LAYER M5 ;
        RECT 7.392 34.368 7.416 34.560 ;
    END
  END q[105]
  PIN q[106]
    DIRECTION OUTPUT ;
    USE SIGNAL ;
    PORT
      LAYER M3 ;
        RECT 7.449 34.368 7.473 34.560 ;
    END
  END q[106]
  PIN q[107]
    DIRECTION OUTPUT ;
    USE SIGNAL ;
    PORT
      LAYER M5 ;
        RECT 7.536 34.368 7.560 34.560 ;
    END
  END q[107]
  PIN q[108]
    DIRECTION OUTPUT ;
    USE SIGNAL ;
    PORT
      LAYER M3 ;
        RECT 7.593 34.368 7.617 34.560 ;
    END
  END q[108]
  PIN q[109]
    DIRECTION OUTPUT ;
    USE SIGNAL ;
    PORT
      LAYER M5 ;
        RECT 7.680 34.368 7.704 34.560 ;
    END
  END q[109]
  PIN q[110]
    DIRECTION OUTPUT ;
    USE SIGNAL ;
    PORT
      LAYER M3 ;
        RECT 7.737 34.368 7.761 34.560 ;
    END
  END q[110]
  PIN q[111]
    DIRECTION OUTPUT ;
    USE SIGNAL ;
    PORT
      LAYER M5 ;
        RECT 7.776 34.368 7.800 34.560 ;
    END
  END q[111]
  PIN q[112]
    DIRECTION OUTPUT ;
    USE SIGNAL ;
    PORT
      LAYER M3 ;
        RECT 7.845 34.368 7.869 34.560 ;
    END
  END q[112]
  PIN q[113]
    DIRECTION OUTPUT ;
    USE SIGNAL ;
    PORT
      LAYER M5 ;
        RECT 7.920 34.368 7.944 34.560 ;
    END
  END q[113]
  PIN q[114]
    DIRECTION OUTPUT ;
    USE SIGNAL ;
    PORT
      LAYER M3 ;
        RECT 7.989 34.368 8.013 34.560 ;
    END
  END q[114]
  PIN q[115]
    DIRECTION OUTPUT ;
    USE SIGNAL ;
    PORT
      LAYER M5 ;
        RECT 8.064 34.368 8.088 34.560 ;
    END
  END q[115]
  PIN q[116]
    DIRECTION OUTPUT ;
    USE SIGNAL ;
    PORT
      LAYER M3 ;
        RECT 8.133 34.368 8.157 34.560 ;
    END
  END q[116]
  PIN q[117]
    DIRECTION OUTPUT ;
    USE SIGNAL ;
    PORT
      LAYER M5 ;
        RECT 8.160 34.368 8.184 34.560 ;
    END
  END q[117]
  PIN q[118]
    DIRECTION OUTPUT ;
    USE SIGNAL ;
    PORT
      LAYER M3 ;
        RECT 8.241 34.368 8.265 34.560 ;
    END
  END q[118]
  PIN q[119]
    DIRECTION OUTPUT ;
    USE SIGNAL ;
    PORT
      LAYER M5 ;
        RECT 8.304 34.368 8.328 34.560 ;
    END
  END q[119]
  PIN q[120]
    DIRECTION OUTPUT ;
    USE SIGNAL ;
    PORT
      LAYER M3 ;
        RECT 8.385 34.368 8.409 34.560 ;
    END
  END q[120]
  PIN q[121]
    DIRECTION OUTPUT ;
    USE SIGNAL ;
    PORT
      LAYER M5 ;
        RECT 8.448 34.368 8.472 34.560 ;
    END
  END q[121]
  PIN q[122]
    DIRECTION OUTPUT ;
    USE SIGNAL ;
    PORT
      LAYER M3 ;
        RECT 8.493 34.368 8.517 34.560 ;
    END
  END q[122]
  PIN q[123]
    DIRECTION OUTPUT ;
    USE SIGNAL ;
    PORT
      LAYER M5 ;
        RECT 8.592 34.368 8.616 34.560 ;
    END
  END q[123]
  PIN q[124]
    DIRECTION OUTPUT ;
    USE SIGNAL ;
    PORT
      LAYER M3 ;
        RECT 8.637 34.368 8.661 34.560 ;
    END
  END q[124]
  PIN q[125]
    DIRECTION OUTPUT ;
    USE SIGNAL ;
    PORT
      LAYER M5 ;
        RECT 8.688 34.368 8.712 34.560 ;
    END
  END q[125]
  PIN q[126]
    DIRECTION OUTPUT ;
    USE SIGNAL ;
    PORT
      LAYER M3 ;
        RECT 8.781 34.368 8.805 34.560 ;
    END
  END q[126]
  PIN q[127]
    DIRECTION OUTPUT ;
    USE SIGNAL ;
    PORT
      LAYER M5 ;
        RECT 8.832 34.368 8.856 34.560 ;
    END
  END q[127]
  PIN q[128]
    DIRECTION OUTPUT ;
    USE SIGNAL ;
    PORT
      LAYER M3 ;
        RECT 8.889 34.368 8.913 34.560 ;
    END
  END q[128]
  PIN q[129]
    DIRECTION OUTPUT ;
    USE SIGNAL ;
    PORT
      LAYER M5 ;
        RECT 8.976 34.368 9.000 34.560 ;
    END
  END q[129]
  PIN q[130]
    DIRECTION OUTPUT ;
    USE SIGNAL ;
    PORT
      LAYER M3 ;
        RECT 9.033 34.368 9.057 34.560 ;
    END
  END q[130]
  PIN q[131]
    DIRECTION OUTPUT ;
    USE SIGNAL ;
    PORT
      LAYER M5 ;
        RECT 9.072 34.368 9.096 34.560 ;
    END
  END q[131]
  PIN q[132]
    DIRECTION OUTPUT ;
    USE SIGNAL ;
    PORT
      LAYER M3 ;
        RECT 9.141 34.368 9.165 34.560 ;
    END
  END q[132]
  PIN q[133]
    DIRECTION OUTPUT ;
    USE SIGNAL ;
    PORT
      LAYER M5 ;
        RECT 9.216 34.368 9.240 34.560 ;
    END
  END q[133]
  PIN q[134]
    DIRECTION OUTPUT ;
    USE SIGNAL ;
    PORT
      LAYER M3 ;
        RECT 9.285 34.368 9.309 34.560 ;
    END
  END q[134]
  PIN q[135]
    DIRECTION OUTPUT ;
    USE SIGNAL ;
    PORT
      LAYER M5 ;
        RECT 9.360 34.368 9.384 34.560 ;
    END
  END q[135]
  PIN q[136]
    DIRECTION OUTPUT ;
    USE SIGNAL ;
    PORT
      LAYER M3 ;
        RECT 9.429 34.368 9.453 34.560 ;
    END
  END q[136]
  PIN q[137]
    DIRECTION OUTPUT ;
    USE SIGNAL ;
    PORT
      LAYER M5 ;
        RECT 9.504 34.368 9.528 34.560 ;
    END
  END q[137]
  PIN q[138]
    DIRECTION OUTPUT ;
    USE SIGNAL ;
    PORT
      LAYER M3 ;
        RECT 9.537 34.368 9.561 34.560 ;
    END
  END q[138]
  PIN q[139]
    DIRECTION OUTPUT ;
    USE SIGNAL ;
    PORT
      LAYER M5 ;
        RECT 9.600 34.368 9.624 34.560 ;
    END
  END q[139]
  PIN q[140]
    DIRECTION OUTPUT ;
    USE SIGNAL ;
    PORT
      LAYER M3 ;
        RECT 9.681 34.368 9.705 34.560 ;
    END
  END q[140]
  PIN q[141]
    DIRECTION OUTPUT ;
    USE SIGNAL ;
    PORT
      LAYER M5 ;
        RECT 9.744 34.368 9.768 34.560 ;
    END
  END q[141]
  PIN q[142]
    DIRECTION OUTPUT ;
    USE SIGNAL ;
    PORT
      LAYER M3 ;
        RECT 9.825 34.368 9.849 34.560 ;
    END
  END q[142]
  PIN q[143]
    DIRECTION OUTPUT ;
    USE SIGNAL ;
    PORT
      LAYER M5 ;
        RECT 9.888 34.368 9.912 34.560 ;
    END
  END q[143]
  PIN q[144]
    DIRECTION OUTPUT ;
    USE SIGNAL ;
    PORT
      LAYER M3 ;
        RECT 9.933 34.368 9.957 34.560 ;
    END
  END q[144]
  PIN q[145]
    DIRECTION OUTPUT ;
    USE SIGNAL ;
    PORT
      LAYER M5 ;
        RECT 9.984 34.368 10.008 34.560 ;
    END
  END q[145]
  PIN q[146]
    DIRECTION OUTPUT ;
    USE SIGNAL ;
    PORT
      LAYER M3 ;
        RECT 10.077 34.368 10.101 34.560 ;
    END
  END q[146]
  PIN q[147]
    DIRECTION OUTPUT ;
    USE SIGNAL ;
    PORT
      LAYER M5 ;
        RECT 10.128 34.368 10.152 34.560 ;
    END
  END q[147]
  PIN q[148]
    DIRECTION OUTPUT ;
    USE SIGNAL ;
    PORT
      LAYER M3 ;
        RECT 10.185 34.368 10.209 34.560 ;
    END
  END q[148]
  PIN q[149]
    DIRECTION OUTPUT ;
    USE SIGNAL ;
    PORT
      LAYER M5 ;
        RECT 10.272 34.368 10.296 34.560 ;
    END
  END q[149]
  PIN q[150]
    DIRECTION OUTPUT ;
    USE SIGNAL ;
    PORT
      LAYER M3 ;
        RECT 10.329 34.368 10.353 34.560 ;
    END
  END q[150]
  PIN q[151]
    DIRECTION OUTPUT ;
    USE SIGNAL ;
    PORT
      LAYER M5 ;
        RECT 10.416 34.368 10.440 34.560 ;
    END
  END q[151]
  PIN q[152]
    DIRECTION OUTPUT ;
    USE SIGNAL ;
    PORT
      LAYER M3 ;
        RECT 10.473 34.368 10.497 34.560 ;
    END
  END q[152]
  PIN q[153]
    DIRECTION OUTPUT ;
    USE SIGNAL ;
    PORT
      LAYER M5 ;
        RECT 10.512 34.368 10.536 34.560 ;
    END
  END q[153]
  PIN q[154]
    DIRECTION OUTPUT ;
    USE SIGNAL ;
    PORT
      LAYER M3 ;
        RECT 10.581 34.368 10.605 34.560 ;
    END
  END q[154]
  PIN q[155]
    DIRECTION OUTPUT ;
    USE SIGNAL ;
    PORT
      LAYER M5 ;
        RECT 10.656 34.368 10.680 34.560 ;
    END
  END q[155]
  PIN q[156]
    DIRECTION OUTPUT ;
    USE SIGNAL ;
    PORT
      LAYER M3 ;
        RECT 10.725 34.368 10.749 34.560 ;
    END
  END q[156]
  PIN q[157]
    DIRECTION OUTPUT ;
    USE SIGNAL ;
    PORT
      LAYER M5 ;
        RECT 10.800 34.368 10.824 34.560 ;
    END
  END q[157]
  PIN q[158]
    DIRECTION OUTPUT ;
    USE SIGNAL ;
    PORT
      LAYER M3 ;
        RECT 10.869 34.368 10.893 34.560 ;
    END
  END q[158]
  PIN q[159]
    DIRECTION OUTPUT ;
    USE SIGNAL ;
    PORT
      LAYER M5 ;
        RECT 10.896 34.368 10.920 34.560 ;
    END
  END q[159]
  PIN q[160]
    DIRECTION OUTPUT ;
    USE SIGNAL ;
    PORT
      LAYER M3 ;
        RECT 10.977 34.368 11.001 34.560 ;
    END
  END q[160]
  PIN q[161]
    DIRECTION OUTPUT ;
    USE SIGNAL ;
    PORT
      LAYER M5 ;
        RECT 11.040 34.368 11.064 34.560 ;
    END
  END q[161]
  PIN q[162]
    DIRECTION OUTPUT ;
    USE SIGNAL ;
    PORT
      LAYER M3 ;
        RECT 11.121 34.368 11.145 34.560 ;
    END
  END q[162]
  PIN q[163]
    DIRECTION OUTPUT ;
    USE SIGNAL ;
    PORT
      LAYER M5 ;
        RECT 11.184 34.368 11.208 34.560 ;
    END
  END q[163]
  PIN q[164]
    DIRECTION OUTPUT ;
    USE SIGNAL ;
    PORT
      LAYER M3 ;
        RECT 11.229 34.368 11.253 34.560 ;
    END
  END q[164]
  PIN q[165]
    DIRECTION OUTPUT ;
    USE SIGNAL ;
    PORT
      LAYER M5 ;
        RECT 11.328 34.368 11.352 34.560 ;
    END
  END q[165]
  PIN q[166]
    DIRECTION OUTPUT ;
    USE SIGNAL ;
    PORT
      LAYER M3 ;
        RECT 11.373 34.368 11.397 34.560 ;
    END
  END q[166]
  PIN q[167]
    DIRECTION OUTPUT ;
    USE SIGNAL ;
    PORT
      LAYER M5 ;
        RECT 11.424 34.368 11.448 34.560 ;
    END
  END q[167]
  PIN q[168]
    DIRECTION OUTPUT ;
    USE SIGNAL ;
    PORT
      LAYER M3 ;
        RECT 11.517 34.368 11.541 34.560 ;
    END
  END q[168]
  PIN q[169]
    DIRECTION OUTPUT ;
    USE SIGNAL ;
    PORT
      LAYER M5 ;
        RECT 11.568 34.368 11.592 34.560 ;
    END
  END q[169]
  PIN q[170]
    DIRECTION OUTPUT ;
    USE SIGNAL ;
    PORT
      LAYER M3 ;
        RECT 11.625 34.368 11.649 34.560 ;
    END
  END q[170]
  PIN q[171]
    DIRECTION OUTPUT ;
    USE SIGNAL ;
    PORT
      LAYER M5 ;
        RECT 11.712 34.368 11.736 34.560 ;
    END
  END q[171]
  PIN q[172]
    DIRECTION OUTPUT ;
    USE SIGNAL ;
    PORT
      LAYER M3 ;
        RECT 11.769 34.368 11.793 34.560 ;
    END
  END q[172]
  PIN q[173]
    DIRECTION OUTPUT ;
    USE SIGNAL ;
    PORT
      LAYER M5 ;
        RECT 11.808 34.368 11.832 34.560 ;
    END
  END q[173]
  PIN q[174]
    DIRECTION OUTPUT ;
    USE SIGNAL ;
    PORT
      LAYER M3 ;
        RECT 11.877 34.368 11.901 34.560 ;
    END
  END q[174]
  PIN q[175]
    DIRECTION OUTPUT ;
    USE SIGNAL ;
    PORT
      LAYER M5 ;
        RECT 11.952 34.368 11.976 34.560 ;
    END
  END q[175]
  PIN q[176]
    DIRECTION OUTPUT ;
    USE SIGNAL ;
    PORT
      LAYER M3 ;
        RECT 12.021 34.368 12.045 34.560 ;
    END
  END q[176]
  PIN q[177]
    DIRECTION OUTPUT ;
    USE SIGNAL ;
    PORT
      LAYER M5 ;
        RECT 12.096 34.368 12.120 34.560 ;
    END
  END q[177]
  PIN q[178]
    DIRECTION OUTPUT ;
    USE SIGNAL ;
    PORT
      LAYER M3 ;
        RECT 12.165 34.368 12.189 34.560 ;
    END
  END q[178]
  PIN q[179]
    DIRECTION OUTPUT ;
    USE SIGNAL ;
    PORT
      LAYER M5 ;
        RECT 12.240 34.368 12.264 34.560 ;
    END
  END q[179]
  PIN q[180]
    DIRECTION OUTPUT ;
    USE SIGNAL ;
    PORT
      LAYER M3 ;
        RECT 12.273 34.368 12.297 34.560 ;
    END
  END q[180]
  PIN q[181]
    DIRECTION OUTPUT ;
    USE SIGNAL ;
    PORT
      LAYER M5 ;
        RECT 12.336 34.368 12.360 34.560 ;
    END
  END q[181]
  PIN q[182]
    DIRECTION OUTPUT ;
    USE SIGNAL ;
    PORT
      LAYER M3 ;
        RECT 12.417 34.368 12.441 34.560 ;
    END
  END q[182]
  PIN q[183]
    DIRECTION OUTPUT ;
    USE SIGNAL ;
    PORT
      LAYER M5 ;
        RECT 12.480 34.368 12.504 34.560 ;
    END
  END q[183]
  PIN q[184]
    DIRECTION OUTPUT ;
    USE SIGNAL ;
    PORT
      LAYER M3 ;
        RECT 12.561 34.368 12.585 34.560 ;
    END
  END q[184]
  PIN q[185]
    DIRECTION OUTPUT ;
    USE SIGNAL ;
    PORT
      LAYER M5 ;
        RECT 12.624 34.368 12.648 34.560 ;
    END
  END q[185]
  PIN q[186]
    DIRECTION OUTPUT ;
    USE SIGNAL ;
    PORT
      LAYER M3 ;
        RECT 12.669 34.368 12.693 34.560 ;
    END
  END q[186]
  PIN q[187]
    DIRECTION OUTPUT ;
    USE SIGNAL ;
    PORT
      LAYER M5 ;
        RECT 12.720 34.368 12.744 34.560 ;
    END
  END q[187]
  PIN q[188]
    DIRECTION OUTPUT ;
    USE SIGNAL ;
    PORT
      LAYER M3 ;
        RECT 12.813 34.368 12.837 34.560 ;
    END
  END q[188]
  PIN q[189]
    DIRECTION OUTPUT ;
    USE SIGNAL ;
    PORT
      LAYER M5 ;
        RECT 12.864 34.368 12.888 34.560 ;
    END
  END q[189]
  PIN q[190]
    DIRECTION OUTPUT ;
    USE SIGNAL ;
    PORT
      LAYER M3 ;
        RECT 12.921 34.368 12.945 34.560 ;
    END
  END q[190]
  PIN q[191]
    DIRECTION OUTPUT ;
    USE SIGNAL ;
    PORT
      LAYER M5 ;
        RECT 13.008 34.368 13.032 34.560 ;
    END
  END q[191]
  PIN q[192]
    DIRECTION OUTPUT ;
    USE SIGNAL ;
    PORT
      LAYER M3 ;
        RECT 13.065 34.368 13.089 34.560 ;
    END
  END q[192]
  PIN q[193]
    DIRECTION OUTPUT ;
    USE SIGNAL ;
    PORT
      LAYER M5 ;
        RECT 13.152 34.368 13.176 34.560 ;
    END
  END q[193]
  PIN q[194]
    DIRECTION OUTPUT ;
    USE SIGNAL ;
    PORT
      LAYER M3 ;
        RECT 13.209 34.368 13.233 34.560 ;
    END
  END q[194]
  PIN q[195]
    DIRECTION OUTPUT ;
    USE SIGNAL ;
    PORT
      LAYER M5 ;
        RECT 13.248 34.368 13.272 34.560 ;
    END
  END q[195]
  PIN q[196]
    DIRECTION OUTPUT ;
    USE SIGNAL ;
    PORT
      LAYER M3 ;
        RECT 13.317 34.368 13.341 34.560 ;
    END
  END q[196]
  PIN q[197]
    DIRECTION OUTPUT ;
    USE SIGNAL ;
    PORT
      LAYER M5 ;
        RECT 13.392 34.368 13.416 34.560 ;
    END
  END q[197]
  PIN q[198]
    DIRECTION OUTPUT ;
    USE SIGNAL ;
    PORT
      LAYER M3 ;
        RECT 13.461 34.368 13.485 34.560 ;
    END
  END q[198]
  PIN q[199]
    DIRECTION OUTPUT ;
    USE SIGNAL ;
    PORT
      LAYER M5 ;
        RECT 13.536 34.368 13.560 34.560 ;
    END
  END q[199]
  PIN q[200]
    DIRECTION OUTPUT ;
    USE SIGNAL ;
    PORT
      LAYER M3 ;
        RECT 13.605 34.368 13.629 34.560 ;
    END
  END q[200]
  PIN q[201]
    DIRECTION OUTPUT ;
    USE SIGNAL ;
    PORT
      LAYER M5 ;
        RECT 13.632 34.368 13.656 34.560 ;
    END
  END q[201]
  PIN q[202]
    DIRECTION OUTPUT ;
    USE SIGNAL ;
    PORT
      LAYER M3 ;
        RECT 13.713 34.368 13.737 34.560 ;
    END
  END q[202]
  PIN q[203]
    DIRECTION OUTPUT ;
    USE SIGNAL ;
    PORT
      LAYER M5 ;
        RECT 13.776 34.368 13.800 34.560 ;
    END
  END q[203]
  PIN q[204]
    DIRECTION OUTPUT ;
    USE SIGNAL ;
    PORT
      LAYER M3 ;
        RECT 13.857 34.368 13.881 34.560 ;
    END
  END q[204]
  PIN q[205]
    DIRECTION OUTPUT ;
    USE SIGNAL ;
    PORT
      LAYER M5 ;
        RECT 13.920 34.368 13.944 34.560 ;
    END
  END q[205]
  PIN q[206]
    DIRECTION OUTPUT ;
    USE SIGNAL ;
    PORT
      LAYER M3 ;
        RECT 13.965 34.368 13.989 34.560 ;
    END
  END q[206]
  PIN q[207]
    DIRECTION OUTPUT ;
    USE SIGNAL ;
    PORT
      LAYER M5 ;
        RECT 14.064 34.368 14.088 34.560 ;
    END
  END q[207]
  PIN q[208]
    DIRECTION OUTPUT ;
    USE SIGNAL ;
    PORT
      LAYER M3 ;
        RECT 14.109 34.368 14.133 34.560 ;
    END
  END q[208]
  PIN q[209]
    DIRECTION OUTPUT ;
    USE SIGNAL ;
    PORT
      LAYER M5 ;
        RECT 14.160 34.368 14.184 34.560 ;
    END
  END q[209]
  PIN q[210]
    DIRECTION OUTPUT ;
    USE SIGNAL ;
    PORT
      LAYER M3 ;
        RECT 14.253 34.368 14.277 34.560 ;
    END
  END q[210]
  PIN q[211]
    DIRECTION OUTPUT ;
    USE SIGNAL ;
    PORT
      LAYER M5 ;
        RECT 14.304 34.368 14.328 34.560 ;
    END
  END q[211]
  PIN q[212]
    DIRECTION OUTPUT ;
    USE SIGNAL ;
    PORT
      LAYER M3 ;
        RECT 14.361 34.368 14.385 34.560 ;
    END
  END q[212]
  PIN q[213]
    DIRECTION OUTPUT ;
    USE SIGNAL ;
    PORT
      LAYER M5 ;
        RECT 14.448 34.368 14.472 34.560 ;
    END
  END q[213]
  PIN q[214]
    DIRECTION OUTPUT ;
    USE SIGNAL ;
    PORT
      LAYER M3 ;
        RECT 14.505 34.368 14.529 34.560 ;
    END
  END q[214]
  PIN q[215]
    DIRECTION OUTPUT ;
    USE SIGNAL ;
    PORT
      LAYER M5 ;
        RECT 14.544 34.368 14.568 34.560 ;
    END
  END q[215]
  PIN q[216]
    DIRECTION OUTPUT ;
    USE SIGNAL ;
    PORT
      LAYER M3 ;
        RECT 14.613 34.368 14.637 34.560 ;
    END
  END q[216]
  PIN q[217]
    DIRECTION OUTPUT ;
    USE SIGNAL ;
    PORT
      LAYER M5 ;
        RECT 14.688 34.368 14.712 34.560 ;
    END
  END q[217]
  PIN q[218]
    DIRECTION OUTPUT ;
    USE SIGNAL ;
    PORT
      LAYER M3 ;
        RECT 14.757 34.368 14.781 34.560 ;
    END
  END q[218]
  PIN q[219]
    DIRECTION OUTPUT ;
    USE SIGNAL ;
    PORT
      LAYER M5 ;
        RECT 14.832 34.368 14.856 34.560 ;
    END
  END q[219]
  PIN q[220]
    DIRECTION OUTPUT ;
    USE SIGNAL ;
    PORT
      LAYER M3 ;
        RECT 14.901 34.368 14.925 34.560 ;
    END
  END q[220]
  PIN q[221]
    DIRECTION OUTPUT ;
    USE SIGNAL ;
    PORT
      LAYER M5 ;
        RECT 14.976 34.368 15.000 34.560 ;
    END
  END q[221]
  PIN q[222]
    DIRECTION OUTPUT ;
    USE SIGNAL ;
    PORT
      LAYER M3 ;
        RECT 15.009 34.368 15.033 34.560 ;
    END
  END q[222]
  PIN q[223]
    DIRECTION OUTPUT ;
    USE SIGNAL ;
    PORT
      LAYER M5 ;
        RECT 15.072 34.368 15.096 34.560 ;
    END
  END q[223]
  PIN q[224]
    DIRECTION OUTPUT ;
    USE SIGNAL ;
    PORT
      LAYER M3 ;
        RECT 15.153 34.368 15.177 34.560 ;
    END
  END q[224]
  PIN q[225]
    DIRECTION OUTPUT ;
    USE SIGNAL ;
    PORT
      LAYER M5 ;
        RECT 15.216 34.368 15.240 34.560 ;
    END
  END q[225]
  PIN q[226]
    DIRECTION OUTPUT ;
    USE SIGNAL ;
    PORT
      LAYER M3 ;
        RECT 15.297 34.368 15.321 34.560 ;
    END
  END q[226]
  PIN q[227]
    DIRECTION OUTPUT ;
    USE SIGNAL ;
    PORT
      LAYER M5 ;
        RECT 15.360 34.368 15.384 34.560 ;
    END
  END q[227]
  PIN q[228]
    DIRECTION OUTPUT ;
    USE SIGNAL ;
    PORT
      LAYER M3 ;
        RECT 15.405 34.368 15.429 34.560 ;
    END
  END q[228]
  PIN q[229]
    DIRECTION OUTPUT ;
    USE SIGNAL ;
    PORT
      LAYER M5 ;
        RECT 15.456 34.368 15.480 34.560 ;
    END
  END q[229]
  PIN q[230]
    DIRECTION OUTPUT ;
    USE SIGNAL ;
    PORT
      LAYER M3 ;
        RECT 15.549 34.368 15.573 34.560 ;
    END
  END q[230]
  PIN q[231]
    DIRECTION OUTPUT ;
    USE SIGNAL ;
    PORT
      LAYER M5 ;
        RECT 15.600 34.368 15.624 34.560 ;
    END
  END q[231]
  PIN q[232]
    DIRECTION OUTPUT ;
    USE SIGNAL ;
    PORT
      LAYER M3 ;
        RECT 15.657 34.368 15.681 34.560 ;
    END
  END q[232]
  PIN q[233]
    DIRECTION OUTPUT ;
    USE SIGNAL ;
    PORT
      LAYER M5 ;
        RECT 15.744 34.368 15.768 34.560 ;
    END
  END q[233]
  PIN q[234]
    DIRECTION OUTPUT ;
    USE SIGNAL ;
    PORT
      LAYER M3 ;
        RECT 15.801 34.368 15.825 34.560 ;
    END
  END q[234]
  PIN q[235]
    DIRECTION OUTPUT ;
    USE SIGNAL ;
    PORT
      LAYER M5 ;
        RECT 15.888 34.368 15.912 34.560 ;
    END
  END q[235]
  PIN q[236]
    DIRECTION OUTPUT ;
    USE SIGNAL ;
    PORT
      LAYER M3 ;
        RECT 15.945 34.368 15.969 34.560 ;
    END
  END q[236]
  PIN q[237]
    DIRECTION OUTPUT ;
    USE SIGNAL ;
    PORT
      LAYER M5 ;
        RECT 15.984 34.368 16.008 34.560 ;
    END
  END q[237]
  PIN q[238]
    DIRECTION OUTPUT ;
    USE SIGNAL ;
    PORT
      LAYER M3 ;
        RECT 16.053 34.368 16.077 34.560 ;
    END
  END q[238]
  PIN q[239]
    DIRECTION OUTPUT ;
    USE SIGNAL ;
    PORT
      LAYER M5 ;
        RECT 16.128 34.368 16.152 34.560 ;
    END
  END q[239]
  PIN q[240]
    DIRECTION OUTPUT ;
    USE SIGNAL ;
    PORT
      LAYER M3 ;
        RECT 16.197 34.368 16.221 34.560 ;
    END
  END q[240]
  PIN q[241]
    DIRECTION OUTPUT ;
    USE SIGNAL ;
    PORT
      LAYER M5 ;
        RECT 16.272 34.368 16.296 34.560 ;
    END
  END q[241]
  PIN q[242]
    DIRECTION OUTPUT ;
    USE SIGNAL ;
    PORT
      LAYER M3 ;
        RECT 16.341 34.368 16.365 34.560 ;
    END
  END q[242]
  PIN q[243]
    DIRECTION OUTPUT ;
    USE SIGNAL ;
    PORT
      LAYER M5 ;
        RECT 16.368 34.368 16.392 34.560 ;
    END
  END q[243]
  PIN q[244]
    DIRECTION OUTPUT ;
    USE SIGNAL ;
    PORT
      LAYER M3 ;
        RECT 16.449 34.368 16.473 34.560 ;
    END
  END q[244]
  PIN q[245]
    DIRECTION OUTPUT ;
    USE SIGNAL ;
    PORT
      LAYER M5 ;
        RECT 16.512 34.368 16.536 34.560 ;
    END
  END q[245]
  PIN q[246]
    DIRECTION OUTPUT ;
    USE SIGNAL ;
    PORT
      LAYER M3 ;
        RECT 16.593 34.368 16.617 34.560 ;
    END
  END q[246]
  PIN q[247]
    DIRECTION OUTPUT ;
    USE SIGNAL ;
    PORT
      LAYER M5 ;
        RECT 16.656 34.368 16.680 34.560 ;
    END
  END q[247]
  PIN q[248]
    DIRECTION OUTPUT ;
    USE SIGNAL ;
    PORT
      LAYER M3 ;
        RECT 16.701 34.368 16.725 34.560 ;
    END
  END q[248]
  PIN q[249]
    DIRECTION OUTPUT ;
    USE SIGNAL ;
    PORT
      LAYER M5 ;
        RECT 16.800 34.368 16.824 34.560 ;
    END
  END q[249]
  PIN q[250]
    DIRECTION OUTPUT ;
    USE SIGNAL ;
    PORT
      LAYER M3 ;
        RECT 16.845 34.368 16.869 34.560 ;
    END
  END q[250]
  PIN q[251]
    DIRECTION OUTPUT ;
    USE SIGNAL ;
    PORT
      LAYER M5 ;
        RECT 16.896 34.368 16.920 34.560 ;
    END
  END q[251]
  PIN q[252]
    DIRECTION OUTPUT ;
    USE SIGNAL ;
    PORT
      LAYER M3 ;
        RECT 16.989 34.368 17.013 34.560 ;
    END
  END q[252]
  PIN q[253]
    DIRECTION OUTPUT ;
    USE SIGNAL ;
    PORT
      LAYER M5 ;
        RECT 17.040 34.368 17.064 34.560 ;
    END
  END q[253]
  PIN q[254]
    DIRECTION OUTPUT ;
    USE SIGNAL ;
    PORT
      LAYER M3 ;
        RECT 17.097 34.368 17.121 34.560 ;
    END
  END q[254]
  PIN q[255]
    DIRECTION OUTPUT ;
    USE SIGNAL ;
    PORT
      LAYER M5 ;
        RECT 17.184 34.368 17.208 34.560 ;
    END
  END q[255]
  PIN q[256]
    DIRECTION OUTPUT ;
    USE SIGNAL ;
    PORT
      LAYER M3 ;
        RECT 17.241 34.368 17.265 34.560 ;
    END
  END q[256]
  PIN q[257]
    DIRECTION OUTPUT ;
    USE SIGNAL ;
    PORT
      LAYER M5 ;
        RECT 17.280 34.368 17.304 34.560 ;
    END
  END q[257]
  PIN q[258]
    DIRECTION OUTPUT ;
    USE SIGNAL ;
    PORT
      LAYER M3 ;
        RECT 17.349 34.368 17.373 34.560 ;
    END
  END q[258]
  PIN q[259]
    DIRECTION OUTPUT ;
    USE SIGNAL ;
    PORT
      LAYER M5 ;
        RECT 17.424 34.368 17.448 34.560 ;
    END
  END q[259]
  PIN q[260]
    DIRECTION OUTPUT ;
    USE SIGNAL ;
    PORT
      LAYER M3 ;
        RECT 17.493 34.368 17.517 34.560 ;
    END
  END q[260]
  PIN q[261]
    DIRECTION OUTPUT ;
    USE SIGNAL ;
    PORT
      LAYER M5 ;
        RECT 17.568 34.368 17.592 34.560 ;
    END
  END q[261]
  PIN q[262]
    DIRECTION OUTPUT ;
    USE SIGNAL ;
    PORT
      LAYER M3 ;
        RECT 17.637 34.368 17.661 34.560 ;
    END
  END q[262]
  PIN q[263]
    DIRECTION OUTPUT ;
    USE SIGNAL ;
    PORT
      LAYER M5 ;
        RECT 17.712 34.368 17.736 34.560 ;
    END
  END q[263]
  PIN q[264]
    DIRECTION OUTPUT ;
    USE SIGNAL ;
    PORT
      LAYER M3 ;
        RECT 17.745 34.368 17.769 34.560 ;
    END
  END q[264]
  PIN q[265]
    DIRECTION OUTPUT ;
    USE SIGNAL ;
    PORT
      LAYER M5 ;
        RECT 17.808 34.368 17.832 34.560 ;
    END
  END q[265]
  PIN q[266]
    DIRECTION OUTPUT ;
    USE SIGNAL ;
    PORT
      LAYER M3 ;
        RECT 17.889 34.368 17.913 34.560 ;
    END
  END q[266]
  PIN q[267]
    DIRECTION OUTPUT ;
    USE SIGNAL ;
    PORT
      LAYER M5 ;
        RECT 17.952 34.368 17.976 34.560 ;
    END
  END q[267]
  PIN q[268]
    DIRECTION OUTPUT ;
    USE SIGNAL ;
    PORT
      LAYER M3 ;
        RECT 18.033 34.368 18.057 34.560 ;
    END
  END q[268]
  PIN q[269]
    DIRECTION OUTPUT ;
    USE SIGNAL ;
    PORT
      LAYER M5 ;
        RECT 18.096 34.368 18.120 34.560 ;
    END
  END q[269]
  PIN q[270]
    DIRECTION OUTPUT ;
    USE SIGNAL ;
    PORT
      LAYER M3 ;
        RECT 18.141 34.368 18.165 34.560 ;
    END
  END q[270]
  PIN q[271]
    DIRECTION OUTPUT ;
    USE SIGNAL ;
    PORT
      LAYER M5 ;
        RECT 18.192 34.368 18.216 34.560 ;
    END
  END q[271]
  PIN q[272]
    DIRECTION OUTPUT ;
    USE SIGNAL ;
    PORT
      LAYER M3 ;
        RECT 18.285 34.368 18.309 34.560 ;
    END
  END q[272]
  PIN q[273]
    DIRECTION OUTPUT ;
    USE SIGNAL ;
    PORT
      LAYER M5 ;
        RECT 18.336 34.368 18.360 34.560 ;
    END
  END q[273]
  PIN q[274]
    DIRECTION OUTPUT ;
    USE SIGNAL ;
    PORT
      LAYER M3 ;
        RECT 18.393 34.368 18.417 34.560 ;
    END
  END q[274]
  PIN q[275]
    DIRECTION OUTPUT ;
    USE SIGNAL ;
    PORT
      LAYER M5 ;
        RECT 18.480 34.368 18.504 34.560 ;
    END
  END q[275]
  PIN q[276]
    DIRECTION OUTPUT ;
    USE SIGNAL ;
    PORT
      LAYER M3 ;
        RECT 18.537 34.368 18.561 34.560 ;
    END
  END q[276]
  PIN q[277]
    DIRECTION OUTPUT ;
    USE SIGNAL ;
    PORT
      LAYER M5 ;
        RECT 18.624 34.368 18.648 34.560 ;
    END
  END q[277]
  PIN q[278]
    DIRECTION OUTPUT ;
    USE SIGNAL ;
    PORT
      LAYER M3 ;
        RECT 18.681 34.368 18.705 34.560 ;
    END
  END q[278]
  PIN q[279]
    DIRECTION OUTPUT ;
    USE SIGNAL ;
    PORT
      LAYER M5 ;
        RECT 18.720 34.368 18.744 34.560 ;
    END
  END q[279]
  PIN q[280]
    DIRECTION OUTPUT ;
    USE SIGNAL ;
    PORT
      LAYER M3 ;
        RECT 18.789 34.368 18.813 34.560 ;
    END
  END q[280]
  PIN q[281]
    DIRECTION OUTPUT ;
    USE SIGNAL ;
    PORT
      LAYER M5 ;
        RECT 18.864 34.368 18.888 34.560 ;
    END
  END q[281]
  PIN q[282]
    DIRECTION OUTPUT ;
    USE SIGNAL ;
    PORT
      LAYER M3 ;
        RECT 18.933 34.368 18.957 34.560 ;
    END
  END q[282]
  PIN q[283]
    DIRECTION OUTPUT ;
    USE SIGNAL ;
    PORT
      LAYER M5 ;
        RECT 19.008 34.368 19.032 34.560 ;
    END
  END q[283]
  PIN q[284]
    DIRECTION OUTPUT ;
    USE SIGNAL ;
    PORT
      LAYER M3 ;
        RECT 19.077 34.368 19.101 34.560 ;
    END
  END q[284]
  PIN q[285]
    DIRECTION OUTPUT ;
    USE SIGNAL ;
    PORT
      LAYER M5 ;
        RECT 19.104 34.368 19.128 34.560 ;
    END
  END q[285]
  PIN q[286]
    DIRECTION OUTPUT ;
    USE SIGNAL ;
    PORT
      LAYER M3 ;
        RECT 19.185 34.368 19.209 34.560 ;
    END
  END q[286]
  PIN q[287]
    DIRECTION OUTPUT ;
    USE SIGNAL ;
    PORT
      LAYER M5 ;
        RECT 19.248 34.368 19.272 34.560 ;
    END
  END q[287]
  PIN q[288]
    DIRECTION OUTPUT ;
    USE SIGNAL ;
    PORT
      LAYER M3 ;
        RECT 19.329 34.368 19.353 34.560 ;
    END
  END q[288]
  PIN q[289]
    DIRECTION OUTPUT ;
    USE SIGNAL ;
    PORT
      LAYER M5 ;
        RECT 19.392 34.368 19.416 34.560 ;
    END
  END q[289]
  PIN q[290]
    DIRECTION OUTPUT ;
    USE SIGNAL ;
    PORT
      LAYER M3 ;
        RECT 19.437 34.368 19.461 34.560 ;
    END
  END q[290]
  PIN q[291]
    DIRECTION OUTPUT ;
    USE SIGNAL ;
    PORT
      LAYER M5 ;
        RECT 19.536 34.368 19.560 34.560 ;
    END
  END q[291]
  PIN q[292]
    DIRECTION OUTPUT ;
    USE SIGNAL ;
    PORT
      LAYER M3 ;
        RECT 19.581 34.368 19.605 34.560 ;
    END
  END q[292]
  PIN q[293]
    DIRECTION OUTPUT ;
    USE SIGNAL ;
    PORT
      LAYER M5 ;
        RECT 19.632 34.368 19.656 34.560 ;
    END
  END q[293]
  PIN q[294]
    DIRECTION OUTPUT ;
    USE SIGNAL ;
    PORT
      LAYER M3 ;
        RECT 19.725 34.368 19.749 34.560 ;
    END
  END q[294]
  PIN q[295]
    DIRECTION OUTPUT ;
    USE SIGNAL ;
    PORT
      LAYER M5 ;
        RECT 19.776 34.368 19.800 34.560 ;
    END
  END q[295]
  PIN q[296]
    DIRECTION OUTPUT ;
    USE SIGNAL ;
    PORT
      LAYER M3 ;
        RECT 19.833 34.368 19.857 34.560 ;
    END
  END q[296]
  PIN q[297]
    DIRECTION OUTPUT ;
    USE SIGNAL ;
    PORT
      LAYER M5 ;
        RECT 19.920 34.368 19.944 34.560 ;
    END
  END q[297]
  PIN q[298]
    DIRECTION OUTPUT ;
    USE SIGNAL ;
    PORT
      LAYER M3 ;
        RECT 19.977 34.368 20.001 34.560 ;
    END
  END q[298]
  PIN q[299]
    DIRECTION OUTPUT ;
    USE SIGNAL ;
    PORT
      LAYER M5 ;
        RECT 20.016 34.368 20.040 34.560 ;
    END
  END q[299]
  PIN q[300]
    DIRECTION OUTPUT ;
    USE SIGNAL ;
    PORT
      LAYER M3 ;
        RECT 20.085 34.368 20.109 34.560 ;
    END
  END q[300]
  PIN q[301]
    DIRECTION OUTPUT ;
    USE SIGNAL ;
    PORT
      LAYER M5 ;
        RECT 20.160 34.368 20.184 34.560 ;
    END
  END q[301]
  PIN q[302]
    DIRECTION OUTPUT ;
    USE SIGNAL ;
    PORT
      LAYER M3 ;
        RECT 20.229 34.368 20.253 34.560 ;
    END
  END q[302]
  PIN q[303]
    DIRECTION OUTPUT ;
    USE SIGNAL ;
    PORT
      LAYER M5 ;
        RECT 20.304 34.368 20.328 34.560 ;
    END
  END q[303]
  PIN q[304]
    DIRECTION OUTPUT ;
    USE SIGNAL ;
    PORT
      LAYER M3 ;
        RECT 20.373 34.368 20.397 34.560 ;
    END
  END q[304]
  PIN q[305]
    DIRECTION OUTPUT ;
    USE SIGNAL ;
    PORT
      LAYER M5 ;
        RECT 20.448 34.368 20.472 34.560 ;
    END
  END q[305]
  PIN q[306]
    DIRECTION OUTPUT ;
    USE SIGNAL ;
    PORT
      LAYER M3 ;
        RECT 20.481 34.368 20.505 34.560 ;
    END
  END q[306]
  PIN q[307]
    DIRECTION OUTPUT ;
    USE SIGNAL ;
    PORT
      LAYER M5 ;
        RECT 20.544 34.368 20.568 34.560 ;
    END
  END q[307]
  PIN q[308]
    DIRECTION OUTPUT ;
    USE SIGNAL ;
    PORT
      LAYER M3 ;
        RECT 20.625 34.368 20.649 34.560 ;
    END
  END q[308]
  PIN q[309]
    DIRECTION OUTPUT ;
    USE SIGNAL ;
    PORT
      LAYER M5 ;
        RECT 20.688 34.368 20.712 34.560 ;
    END
  END q[309]
  PIN q[310]
    DIRECTION OUTPUT ;
    USE SIGNAL ;
    PORT
      LAYER M3 ;
        RECT 20.769 34.368 20.793 34.560 ;
    END
  END q[310]
  PIN q[311]
    DIRECTION OUTPUT ;
    USE SIGNAL ;
    PORT
      LAYER M5 ;
        RECT 20.832 34.368 20.856 34.560 ;
    END
  END q[311]
  PIN q[312]
    DIRECTION OUTPUT ;
    USE SIGNAL ;
    PORT
      LAYER M3 ;
        RECT 20.877 34.368 20.901 34.560 ;
    END
  END q[312]
  PIN q[313]
    DIRECTION OUTPUT ;
    USE SIGNAL ;
    PORT
      LAYER M5 ;
        RECT 20.928 34.368 20.952 34.560 ;
    END
  END q[313]
  PIN q[314]
    DIRECTION OUTPUT ;
    USE SIGNAL ;
    PORT
      LAYER M3 ;
        RECT 21.021 34.368 21.045 34.560 ;
    END
  END q[314]
  PIN q[315]
    DIRECTION OUTPUT ;
    USE SIGNAL ;
    PORT
      LAYER M5 ;
        RECT 21.072 34.368 21.096 34.560 ;
    END
  END q[315]
  PIN q[316]
    DIRECTION OUTPUT ;
    USE SIGNAL ;
    PORT
      LAYER M3 ;
        RECT 21.129 34.368 21.153 34.560 ;
    END
  END q[316]
  PIN q[317]
    DIRECTION OUTPUT ;
    USE SIGNAL ;
    PORT
      LAYER M5 ;
        RECT 21.216 34.368 21.240 34.560 ;
    END
  END q[317]
  PIN q[318]
    DIRECTION OUTPUT ;
    USE SIGNAL ;
    PORT
      LAYER M3 ;
        RECT 21.273 34.368 21.297 34.560 ;
    END
  END q[318]
  PIN q[319]
    DIRECTION OUTPUT ;
    USE SIGNAL ;
    PORT
      LAYER M5 ;
        RECT 21.360 34.368 21.384 34.560 ;
    END
  END q[319]
  PIN q[320]
    DIRECTION OUTPUT ;
    USE SIGNAL ;
    PORT
      LAYER M3 ;
        RECT 21.417 34.368 21.441 34.560 ;
    END
  END q[320]
  PIN q[321]
    DIRECTION OUTPUT ;
    USE SIGNAL ;
    PORT
      LAYER M5 ;
        RECT 21.456 34.368 21.480 34.560 ;
    END
  END q[321]
  PIN q[322]
    DIRECTION OUTPUT ;
    USE SIGNAL ;
    PORT
      LAYER M3 ;
        RECT 21.525 34.368 21.549 34.560 ;
    END
  END q[322]
  PIN q[323]
    DIRECTION OUTPUT ;
    USE SIGNAL ;
    PORT
      LAYER M5 ;
        RECT 21.600 34.368 21.624 34.560 ;
    END
  END q[323]
  PIN q[324]
    DIRECTION OUTPUT ;
    USE SIGNAL ;
    PORT
      LAYER M3 ;
        RECT 21.669 34.368 21.693 34.560 ;
    END
  END q[324]
  PIN q[325]
    DIRECTION OUTPUT ;
    USE SIGNAL ;
    PORT
      LAYER M5 ;
        RECT 21.744 34.368 21.768 34.560 ;
    END
  END q[325]
  PIN q[326]
    DIRECTION OUTPUT ;
    USE SIGNAL ;
    PORT
      LAYER M3 ;
        RECT 21.777 34.368 21.801 34.560 ;
    END
  END q[326]
  PIN q[327]
    DIRECTION OUTPUT ;
    USE SIGNAL ;
    PORT
      LAYER M5 ;
        RECT 21.840 34.368 21.864 34.560 ;
    END
  END q[327]
  PIN q[328]
    DIRECTION OUTPUT ;
    USE SIGNAL ;
    PORT
      LAYER M3 ;
        RECT 21.921 34.368 21.945 34.560 ;
    END
  END q[328]
  PIN q[329]
    DIRECTION OUTPUT ;
    USE SIGNAL ;
    PORT
      LAYER M5 ;
        RECT 21.984 34.368 22.008 34.560 ;
    END
  END q[329]
  PIN q[330]
    DIRECTION OUTPUT ;
    USE SIGNAL ;
    PORT
      LAYER M3 ;
        RECT 22.065 34.368 22.089 34.560 ;
    END
  END q[330]
  PIN q[331]
    DIRECTION OUTPUT ;
    USE SIGNAL ;
    PORT
      LAYER M5 ;
        RECT 22.128 34.368 22.152 34.560 ;
    END
  END q[331]
  PIN q[332]
    DIRECTION OUTPUT ;
    USE SIGNAL ;
    PORT
      LAYER M3 ;
        RECT 22.173 34.368 22.197 34.560 ;
    END
  END q[332]
  PIN q[333]
    DIRECTION OUTPUT ;
    USE SIGNAL ;
    PORT
      LAYER M5 ;
        RECT 22.272 34.368 22.296 34.560 ;
    END
  END q[333]
  PIN q[334]
    DIRECTION OUTPUT ;
    USE SIGNAL ;
    PORT
      LAYER M3 ;
        RECT 22.317 34.368 22.341 34.560 ;
    END
  END q[334]
  PIN q[335]
    DIRECTION OUTPUT ;
    USE SIGNAL ;
    PORT
      LAYER M5 ;
        RECT 22.368 34.368 22.392 34.560 ;
    END
  END q[335]
  PIN q[336]
    DIRECTION OUTPUT ;
    USE SIGNAL ;
    PORT
      LAYER M3 ;
        RECT 22.461 34.368 22.485 34.560 ;
    END
  END q[336]
  PIN q[337]
    DIRECTION OUTPUT ;
    USE SIGNAL ;
    PORT
      LAYER M5 ;
        RECT 22.512 34.368 22.536 34.560 ;
    END
  END q[337]
  PIN q[338]
    DIRECTION OUTPUT ;
    USE SIGNAL ;
    PORT
      LAYER M3 ;
        RECT 22.569 34.368 22.593 34.560 ;
    END
  END q[338]
  PIN q[339]
    DIRECTION OUTPUT ;
    USE SIGNAL ;
    PORT
      LAYER M5 ;
        RECT 22.656 34.368 22.680 34.560 ;
    END
  END q[339]
  PIN q[340]
    DIRECTION OUTPUT ;
    USE SIGNAL ;
    PORT
      LAYER M3 ;
        RECT 22.713 34.368 22.737 34.560 ;
    END
  END q[340]
  PIN q[341]
    DIRECTION OUTPUT ;
    USE SIGNAL ;
    PORT
      LAYER M5 ;
        RECT 22.752 34.368 22.776 34.560 ;
    END
  END q[341]
  PIN q[342]
    DIRECTION OUTPUT ;
    USE SIGNAL ;
    PORT
      LAYER M3 ;
        RECT 22.821 34.368 22.845 34.560 ;
    END
  END q[342]
  PIN q[343]
    DIRECTION OUTPUT ;
    USE SIGNAL ;
    PORT
      LAYER M5 ;
        RECT 22.896 34.368 22.920 34.560 ;
    END
  END q[343]
  PIN q[344]
    DIRECTION OUTPUT ;
    USE SIGNAL ;
    PORT
      LAYER M3 ;
        RECT 22.965 34.368 22.989 34.560 ;
    END
  END q[344]
  PIN q[345]
    DIRECTION OUTPUT ;
    USE SIGNAL ;
    PORT
      LAYER M5 ;
        RECT 23.040 34.368 23.064 34.560 ;
    END
  END q[345]
  PIN q[346]
    DIRECTION OUTPUT ;
    USE SIGNAL ;
    PORT
      LAYER M3 ;
        RECT 23.109 34.368 23.133 34.560 ;
    END
  END q[346]
  PIN q[347]
    DIRECTION OUTPUT ;
    USE SIGNAL ;
    PORT
      LAYER M5 ;
        RECT 23.184 34.368 23.208 34.560 ;
    END
  END q[347]
  PIN q[348]
    DIRECTION OUTPUT ;
    USE SIGNAL ;
    PORT
      LAYER M3 ;
        RECT 23.217 34.368 23.241 34.560 ;
    END
  END q[348]
  PIN q[349]
    DIRECTION OUTPUT ;
    USE SIGNAL ;
    PORT
      LAYER M5 ;
        RECT 23.280 34.368 23.304 34.560 ;
    END
  END q[349]
  PIN q[350]
    DIRECTION OUTPUT ;
    USE SIGNAL ;
    PORT
      LAYER M3 ;
        RECT 23.361 34.368 23.385 34.560 ;
    END
  END q[350]
  PIN q[351]
    DIRECTION OUTPUT ;
    USE SIGNAL ;
    PORT
      LAYER M5 ;
        RECT 23.424 34.368 23.448 34.560 ;
    END
  END q[351]
  PIN q[352]
    DIRECTION OUTPUT ;
    USE SIGNAL ;
    PORT
      LAYER M3 ;
        RECT 23.505 34.368 23.529 34.560 ;
    END
  END q[352]
  PIN q[353]
    DIRECTION OUTPUT ;
    USE SIGNAL ;
    PORT
      LAYER M5 ;
        RECT 23.568 34.368 23.592 34.560 ;
    END
  END q[353]
  PIN q[354]
    DIRECTION OUTPUT ;
    USE SIGNAL ;
    PORT
      LAYER M3 ;
        RECT 23.613 34.368 23.637 34.560 ;
    END
  END q[354]
  PIN q[355]
    DIRECTION OUTPUT ;
    USE SIGNAL ;
    PORT
      LAYER M5 ;
        RECT 23.664 34.368 23.688 34.560 ;
    END
  END q[355]
  PIN q[356]
    DIRECTION OUTPUT ;
    USE SIGNAL ;
    PORT
      LAYER M3 ;
        RECT 23.757 34.368 23.781 34.560 ;
    END
  END q[356]
  PIN q[357]
    DIRECTION OUTPUT ;
    USE SIGNAL ;
    PORT
      LAYER M5 ;
        RECT 23.808 34.368 23.832 34.560 ;
    END
  END q[357]
  PIN q[358]
    DIRECTION OUTPUT ;
    USE SIGNAL ;
    PORT
      LAYER M3 ;
        RECT 23.865 34.368 23.889 34.560 ;
    END
  END q[358]
  PIN q[359]
    DIRECTION OUTPUT ;
    USE SIGNAL ;
    PORT
      LAYER M5 ;
        RECT 23.952 34.368 23.976 34.560 ;
    END
  END q[359]
  PIN q[360]
    DIRECTION OUTPUT ;
    USE SIGNAL ;
    PORT
      LAYER M3 ;
        RECT 24.009 34.368 24.033 34.560 ;
    END
  END q[360]
  PIN q[361]
    DIRECTION OUTPUT ;
    USE SIGNAL ;
    PORT
      LAYER M5 ;
        RECT 24.096 34.368 24.120 34.560 ;
    END
  END q[361]
  PIN q[362]
    DIRECTION OUTPUT ;
    USE SIGNAL ;
    PORT
      LAYER M3 ;
        RECT 24.153 34.368 24.177 34.560 ;
    END
  END q[362]
  PIN q[363]
    DIRECTION OUTPUT ;
    USE SIGNAL ;
    PORT
      LAYER M5 ;
        RECT 24.192 34.368 24.216 34.560 ;
    END
  END q[363]
  PIN q[364]
    DIRECTION OUTPUT ;
    USE SIGNAL ;
    PORT
      LAYER M3 ;
        RECT 24.261 34.368 24.285 34.560 ;
    END
  END q[364]
  PIN q[365]
    DIRECTION OUTPUT ;
    USE SIGNAL ;
    PORT
      LAYER M5 ;
        RECT 24.336 34.368 24.360 34.560 ;
    END
  END q[365]
  PIN q[366]
    DIRECTION OUTPUT ;
    USE SIGNAL ;
    PORT
      LAYER M3 ;
        RECT 24.405 34.368 24.429 34.560 ;
    END
  END q[366]
  PIN q[367]
    DIRECTION OUTPUT ;
    USE SIGNAL ;
    PORT
      LAYER M5 ;
        RECT 24.480 34.368 24.504 34.560 ;
    END
  END q[367]
  PIN q[368]
    DIRECTION OUTPUT ;
    USE SIGNAL ;
    PORT
      LAYER M3 ;
        RECT 24.513 34.368 24.537 34.560 ;
    END
  END q[368]
  PIN q[369]
    DIRECTION OUTPUT ;
    USE SIGNAL ;
    PORT
      LAYER M5 ;
        RECT 24.576 34.368 24.600 34.560 ;
    END
  END q[369]
  PIN q[370]
    DIRECTION OUTPUT ;
    USE SIGNAL ;
    PORT
      LAYER M3 ;
        RECT 24.657 34.368 24.681 34.560 ;
    END
  END q[370]
  PIN q[371]
    DIRECTION OUTPUT ;
    USE SIGNAL ;
    PORT
      LAYER M5 ;
        RECT 24.720 34.368 24.744 34.560 ;
    END
  END q[371]
  PIN q[372]
    DIRECTION OUTPUT ;
    USE SIGNAL ;
    PORT
      LAYER M3 ;
        RECT 24.801 34.368 24.825 34.560 ;
    END
  END q[372]
  PIN q[373]
    DIRECTION OUTPUT ;
    USE SIGNAL ;
    PORT
      LAYER M5 ;
        RECT 24.864 34.368 24.888 34.560 ;
    END
  END q[373]
  PIN q[374]
    DIRECTION OUTPUT ;
    USE SIGNAL ;
    PORT
      LAYER M3 ;
        RECT 24.909 34.368 24.933 34.560 ;
    END
  END q[374]
  PIN q[375]
    DIRECTION OUTPUT ;
    USE SIGNAL ;
    PORT
      LAYER M5 ;
        RECT 25.008 34.368 25.032 34.560 ;
    END
  END q[375]
  PIN q[376]
    DIRECTION OUTPUT ;
    USE SIGNAL ;
    PORT
      LAYER M3 ;
        RECT 25.053 34.368 25.077 34.560 ;
    END
  END q[376]
  PIN q[377]
    DIRECTION OUTPUT ;
    USE SIGNAL ;
    PORT
      LAYER M5 ;
        RECT 25.104 34.368 25.128 34.560 ;
    END
  END q[377]
  PIN q[378]
    DIRECTION OUTPUT ;
    USE SIGNAL ;
    PORT
      LAYER M3 ;
        RECT 25.197 34.368 25.221 34.560 ;
    END
  END q[378]
  PIN q[379]
    DIRECTION OUTPUT ;
    USE SIGNAL ;
    PORT
      LAYER M5 ;
        RECT 25.248 34.368 25.272 34.560 ;
    END
  END q[379]
  PIN q[380]
    DIRECTION OUTPUT ;
    USE SIGNAL ;
    PORT
      LAYER M3 ;
        RECT 25.305 34.368 25.329 34.560 ;
    END
  END q[380]
  PIN q[381]
    DIRECTION OUTPUT ;
    USE SIGNAL ;
    PORT
      LAYER M5 ;
        RECT 25.392 34.368 25.416 34.560 ;
    END
  END q[381]
  PIN q[382]
    DIRECTION OUTPUT ;
    USE SIGNAL ;
    PORT
      LAYER M3 ;
        RECT 25.449 34.368 25.473 34.560 ;
    END
  END q[382]
  PIN q[383]
    DIRECTION OUTPUT ;
    USE SIGNAL ;
    PORT
      LAYER M5 ;
        RECT 25.488 34.368 25.512 34.560 ;
    END
  END q[383]
  PIN q[384]
    DIRECTION OUTPUT ;
    USE SIGNAL ;
    PORT
      LAYER M3 ;
        RECT 25.557 34.368 25.581 34.560 ;
    END
  END q[384]
  PIN q[385]
    DIRECTION OUTPUT ;
    USE SIGNAL ;
    PORT
      LAYER M5 ;
        RECT 25.632 34.368 25.656 34.560 ;
    END
  END q[385]
  PIN q[386]
    DIRECTION OUTPUT ;
    USE SIGNAL ;
    PORT
      LAYER M3 ;
        RECT 25.701 34.368 25.725 34.560 ;
    END
  END q[386]
  PIN q[387]
    DIRECTION OUTPUT ;
    USE SIGNAL ;
    PORT
      LAYER M5 ;
        RECT 25.776 34.368 25.800 34.560 ;
    END
  END q[387]
  PIN q[388]
    DIRECTION OUTPUT ;
    USE SIGNAL ;
    PORT
      LAYER M3 ;
        RECT 25.845 34.368 25.869 34.560 ;
    END
  END q[388]
  PIN q[389]
    DIRECTION OUTPUT ;
    USE SIGNAL ;
    PORT
      LAYER M5 ;
        RECT 25.920 34.368 25.944 34.560 ;
    END
  END q[389]
  PIN q[390]
    DIRECTION OUTPUT ;
    USE SIGNAL ;
    PORT
      LAYER M3 ;
        RECT 25.953 34.368 25.977 34.560 ;
    END
  END q[390]
  PIN q[391]
    DIRECTION OUTPUT ;
    USE SIGNAL ;
    PORT
      LAYER M5 ;
        RECT 26.016 34.368 26.040 34.560 ;
    END
  END q[391]
  PIN q[392]
    DIRECTION OUTPUT ;
    USE SIGNAL ;
    PORT
      LAYER M3 ;
        RECT 26.097 34.368 26.121 34.560 ;
    END
  END q[392]
  PIN q[393]
    DIRECTION OUTPUT ;
    USE SIGNAL ;
    PORT
      LAYER M5 ;
        RECT 26.160 34.368 26.184 34.560 ;
    END
  END q[393]
  PIN q[394]
    DIRECTION OUTPUT ;
    USE SIGNAL ;
    PORT
      LAYER M3 ;
        RECT 26.241 34.368 26.265 34.560 ;
    END
  END q[394]
  PIN q[395]
    DIRECTION OUTPUT ;
    USE SIGNAL ;
    PORT
      LAYER M5 ;
        RECT 26.304 34.368 26.328 34.560 ;
    END
  END q[395]
  PIN q[396]
    DIRECTION OUTPUT ;
    USE SIGNAL ;
    PORT
      LAYER M3 ;
        RECT 26.349 34.368 26.373 34.560 ;
    END
  END q[396]
  PIN q[397]
    DIRECTION OUTPUT ;
    USE SIGNAL ;
    PORT
      LAYER M5 ;
        RECT 26.400 34.368 26.424 34.560 ;
    END
  END q[397]
  PIN q[398]
    DIRECTION OUTPUT ;
    USE SIGNAL ;
    PORT
      LAYER M3 ;
        RECT 26.493 34.368 26.517 34.560 ;
    END
  END q[398]
  PIN q[399]
    DIRECTION OUTPUT ;
    USE SIGNAL ;
    PORT
      LAYER M5 ;
        RECT 26.544 34.368 26.568 34.560 ;
    END
  END q[399]
  PIN q[400]
    DIRECTION OUTPUT ;
    USE SIGNAL ;
    PORT
      LAYER M3 ;
        RECT 26.601 34.368 26.625 34.560 ;
    END
  END q[400]
  PIN q[401]
    DIRECTION OUTPUT ;
    USE SIGNAL ;
    PORT
      LAYER M5 ;
        RECT 26.688 34.368 26.712 34.560 ;
    END
  END q[401]
  PIN q[402]
    DIRECTION OUTPUT ;
    USE SIGNAL ;
    PORT
      LAYER M3 ;
        RECT 26.745 34.368 26.769 34.560 ;
    END
  END q[402]
  PIN q[403]
    DIRECTION OUTPUT ;
    USE SIGNAL ;
    PORT
      LAYER M5 ;
        RECT 26.832 34.368 26.856 34.560 ;
    END
  END q[403]
  PIN q[404]
    DIRECTION OUTPUT ;
    USE SIGNAL ;
    PORT
      LAYER M3 ;
        RECT 26.889 34.368 26.913 34.560 ;
    END
  END q[404]
  PIN q[405]
    DIRECTION OUTPUT ;
    USE SIGNAL ;
    PORT
      LAYER M5 ;
        RECT 26.928 34.368 26.952 34.560 ;
    END
  END q[405]
  PIN q[406]
    DIRECTION OUTPUT ;
    USE SIGNAL ;
    PORT
      LAYER M3 ;
        RECT 26.997 34.368 27.021 34.560 ;
    END
  END q[406]
  PIN q[407]
    DIRECTION OUTPUT ;
    USE SIGNAL ;
    PORT
      LAYER M5 ;
        RECT 27.072 34.368 27.096 34.560 ;
    END
  END q[407]
  PIN q[408]
    DIRECTION OUTPUT ;
    USE SIGNAL ;
    PORT
      LAYER M3 ;
        RECT 27.141 34.368 27.165 34.560 ;
    END
  END q[408]
  PIN q[409]
    DIRECTION OUTPUT ;
    USE SIGNAL ;
    PORT
      LAYER M5 ;
        RECT 27.216 34.368 27.240 34.560 ;
    END
  END q[409]
  PIN q[410]
    DIRECTION OUTPUT ;
    USE SIGNAL ;
    PORT
      LAYER M3 ;
        RECT 27.249 34.368 27.273 34.560 ;
    END
  END q[410]
  PIN q[411]
    DIRECTION OUTPUT ;
    USE SIGNAL ;
    PORT
      LAYER M5 ;
        RECT 27.312 34.368 27.336 34.560 ;
    END
  END q[411]
  PIN q[412]
    DIRECTION OUTPUT ;
    USE SIGNAL ;
    PORT
      LAYER M3 ;
        RECT 27.393 34.368 27.417 34.560 ;
    END
  END q[412]
  PIN q[413]
    DIRECTION OUTPUT ;
    USE SIGNAL ;
    PORT
      LAYER M5 ;
        RECT 27.456 34.368 27.480 34.560 ;
    END
  END q[413]
  PIN q[414]
    DIRECTION OUTPUT ;
    USE SIGNAL ;
    PORT
      LAYER M3 ;
        RECT 27.537 34.368 27.561 34.560 ;
    END
  END q[414]
  PIN q[415]
    DIRECTION OUTPUT ;
    USE SIGNAL ;
    PORT
      LAYER M5 ;
        RECT 27.600 34.368 27.624 34.560 ;
    END
  END q[415]
  PIN q[416]
    DIRECTION OUTPUT ;
    USE SIGNAL ;
    PORT
      LAYER M3 ;
        RECT 27.645 34.368 27.669 34.560 ;
    END
  END q[416]
  PIN q[417]
    DIRECTION OUTPUT ;
    USE SIGNAL ;
    PORT
      LAYER M5 ;
        RECT 27.744 34.368 27.768 34.560 ;
    END
  END q[417]
  PIN q[418]
    DIRECTION OUTPUT ;
    USE SIGNAL ;
    PORT
      LAYER M3 ;
        RECT 27.789 34.368 27.813 34.560 ;
    END
  END q[418]
  PIN q[419]
    DIRECTION OUTPUT ;
    USE SIGNAL ;
    PORT
      LAYER M5 ;
        RECT 27.840 34.368 27.864 34.560 ;
    END
  END q[419]
  PIN q[420]
    DIRECTION OUTPUT ;
    USE SIGNAL ;
    PORT
      LAYER M3 ;
        RECT 27.933 34.368 27.957 34.560 ;
    END
  END q[420]
  PIN q[421]
    DIRECTION OUTPUT ;
    USE SIGNAL ;
    PORT
      LAYER M5 ;
        RECT 27.984 34.368 28.008 34.560 ;
    END
  END q[421]
  PIN q[422]
    DIRECTION OUTPUT ;
    USE SIGNAL ;
    PORT
      LAYER M3 ;
        RECT 28.041 34.368 28.065 34.560 ;
    END
  END q[422]
  PIN q[423]
    DIRECTION OUTPUT ;
    USE SIGNAL ;
    PORT
      LAYER M5 ;
        RECT 28.128 34.368 28.152 34.560 ;
    END
  END q[423]
  PIN q[424]
    DIRECTION OUTPUT ;
    USE SIGNAL ;
    PORT
      LAYER M3 ;
        RECT 28.185 34.368 28.209 34.560 ;
    END
  END q[424]
  PIN q[425]
    DIRECTION OUTPUT ;
    USE SIGNAL ;
    PORT
      LAYER M5 ;
        RECT 28.224 34.368 28.248 34.560 ;
    END
  END q[425]
  PIN q[426]
    DIRECTION OUTPUT ;
    USE SIGNAL ;
    PORT
      LAYER M3 ;
        RECT 28.293 34.368 28.317 34.560 ;
    END
  END q[426]
  PIN q[427]
    DIRECTION OUTPUT ;
    USE SIGNAL ;
    PORT
      LAYER M5 ;
        RECT 28.368 34.368 28.392 34.560 ;
    END
  END q[427]
  PIN q[428]
    DIRECTION OUTPUT ;
    USE SIGNAL ;
    PORT
      LAYER M3 ;
        RECT 28.437 34.368 28.461 34.560 ;
    END
  END q[428]
  PIN q[429]
    DIRECTION OUTPUT ;
    USE SIGNAL ;
    PORT
      LAYER M5 ;
        RECT 28.512 34.368 28.536 34.560 ;
    END
  END q[429]
  PIN q[430]
    DIRECTION OUTPUT ;
    USE SIGNAL ;
    PORT
      LAYER M3 ;
        RECT 28.581 34.368 28.605 34.560 ;
    END
  END q[430]
  PIN q[431]
    DIRECTION OUTPUT ;
    USE SIGNAL ;
    PORT
      LAYER M5 ;
        RECT 28.656 34.368 28.680 34.560 ;
    END
  END q[431]
  PIN q[432]
    DIRECTION OUTPUT ;
    USE SIGNAL ;
    PORT
      LAYER M3 ;
        RECT 28.689 34.368 28.713 34.560 ;
    END
  END q[432]
  PIN q[433]
    DIRECTION OUTPUT ;
    USE SIGNAL ;
    PORT
      LAYER M5 ;
        RECT 28.752 34.368 28.776 34.560 ;
    END
  END q[433]
  PIN q[434]
    DIRECTION OUTPUT ;
    USE SIGNAL ;
    PORT
      LAYER M3 ;
        RECT 28.833 34.368 28.857 34.560 ;
    END
  END q[434]
  PIN q[435]
    DIRECTION OUTPUT ;
    USE SIGNAL ;
    PORT
      LAYER M5 ;
        RECT 28.896 34.368 28.920 34.560 ;
    END
  END q[435]
  PIN q[436]
    DIRECTION OUTPUT ;
    USE SIGNAL ;
    PORT
      LAYER M3 ;
        RECT 28.977 34.368 29.001 34.560 ;
    END
  END q[436]
  PIN q[437]
    DIRECTION OUTPUT ;
    USE SIGNAL ;
    PORT
      LAYER M5 ;
        RECT 29.040 34.368 29.064 34.560 ;
    END
  END q[437]
  PIN q[438]
    DIRECTION OUTPUT ;
    USE SIGNAL ;
    PORT
      LAYER M3 ;
        RECT 29.085 34.368 29.109 34.560 ;
    END
  END q[438]
  PIN q[439]
    DIRECTION OUTPUT ;
    USE SIGNAL ;
    PORT
      LAYER M5 ;
        RECT 29.136 34.368 29.160 34.560 ;
    END
  END q[439]
  PIN q[440]
    DIRECTION OUTPUT ;
    USE SIGNAL ;
    PORT
      LAYER M3 ;
        RECT 29.229 34.368 29.253 34.560 ;
    END
  END q[440]
  PIN q[441]
    DIRECTION OUTPUT ;
    USE SIGNAL ;
    PORT
      LAYER M5 ;
        RECT 29.280 34.368 29.304 34.560 ;
    END
  END q[441]
  PIN q[442]
    DIRECTION OUTPUT ;
    USE SIGNAL ;
    PORT
      LAYER M3 ;
        RECT 29.337 34.368 29.361 34.560 ;
    END
  END q[442]
  PIN q[443]
    DIRECTION OUTPUT ;
    USE SIGNAL ;
    PORT
      LAYER M5 ;
        RECT 29.424 34.368 29.448 34.560 ;
    END
  END q[443]
  PIN q[444]
    DIRECTION OUTPUT ;
    USE SIGNAL ;
    PORT
      LAYER M3 ;
        RECT 29.481 34.368 29.505 34.560 ;
    END
  END q[444]
  PIN q[445]
    DIRECTION OUTPUT ;
    USE SIGNAL ;
    PORT
      LAYER M5 ;
        RECT 29.568 34.368 29.592 34.560 ;
    END
  END q[445]
  PIN q[446]
    DIRECTION OUTPUT ;
    USE SIGNAL ;
    PORT
      LAYER M3 ;
        RECT 29.625 34.368 29.649 34.560 ;
    END
  END q[446]
  PIN q[447]
    DIRECTION OUTPUT ;
    USE SIGNAL ;
    PORT
      LAYER M5 ;
        RECT 29.664 34.368 29.688 34.560 ;
    END
  END q[447]
  PIN q[448]
    DIRECTION OUTPUT ;
    USE SIGNAL ;
    PORT
      LAYER M3 ;
        RECT 29.733 34.368 29.757 34.560 ;
    END
  END q[448]
  PIN q[449]
    DIRECTION OUTPUT ;
    USE SIGNAL ;
    PORT
      LAYER M5 ;
        RECT 29.808 34.368 29.832 34.560 ;
    END
  END q[449]
  PIN q[450]
    DIRECTION OUTPUT ;
    USE SIGNAL ;
    PORT
      LAYER M3 ;
        RECT 29.877 34.368 29.901 34.560 ;
    END
  END q[450]
  PIN q[451]
    DIRECTION OUTPUT ;
    USE SIGNAL ;
    PORT
      LAYER M5 ;
        RECT 29.952 34.368 29.976 34.560 ;
    END
  END q[451]
  PIN q[452]
    DIRECTION OUTPUT ;
    USE SIGNAL ;
    PORT
      LAYER M3 ;
        RECT 29.985 34.368 30.009 34.560 ;
    END
  END q[452]
  PIN q[453]
    DIRECTION OUTPUT ;
    USE SIGNAL ;
    PORT
      LAYER M5 ;
        RECT 30.048 34.368 30.072 34.560 ;
    END
  END q[453]
  PIN q[454]
    DIRECTION OUTPUT ;
    USE SIGNAL ;
    PORT
      LAYER M3 ;
        RECT 30.129 34.368 30.153 34.560 ;
    END
  END q[454]
  PIN q[455]
    DIRECTION OUTPUT ;
    USE SIGNAL ;
    PORT
      LAYER M5 ;
        RECT 30.192 34.368 30.216 34.560 ;
    END
  END q[455]
  PIN q[456]
    DIRECTION OUTPUT ;
    USE SIGNAL ;
    PORT
      LAYER M3 ;
        RECT 30.273 34.368 30.297 34.560 ;
    END
  END q[456]
  PIN q[457]
    DIRECTION OUTPUT ;
    USE SIGNAL ;
    PORT
      LAYER M5 ;
        RECT 30.336 34.368 30.360 34.560 ;
    END
  END q[457]
  PIN q[458]
    DIRECTION OUTPUT ;
    USE SIGNAL ;
    PORT
      LAYER M3 ;
        RECT 30.381 34.368 30.405 34.560 ;
    END
  END q[458]
  PIN q[459]
    DIRECTION OUTPUT ;
    USE SIGNAL ;
    PORT
      LAYER M5 ;
        RECT 30.480 34.368 30.504 34.560 ;
    END
  END q[459]
  PIN q[460]
    DIRECTION OUTPUT ;
    USE SIGNAL ;
    PORT
      LAYER M3 ;
        RECT 30.525 34.368 30.549 34.560 ;
    END
  END q[460]
  PIN q[461]
    DIRECTION OUTPUT ;
    USE SIGNAL ;
    PORT
      LAYER M5 ;
        RECT 30.576 34.368 30.600 34.560 ;
    END
  END q[461]
  PIN q[462]
    DIRECTION OUTPUT ;
    USE SIGNAL ;
    PORT
      LAYER M3 ;
        RECT 30.669 34.368 30.693 34.560 ;
    END
  END q[462]
  PIN q[463]
    DIRECTION OUTPUT ;
    USE SIGNAL ;
    PORT
      LAYER M5 ;
        RECT 30.720 34.368 30.744 34.560 ;
    END
  END q[463]
  PIN q[464]
    DIRECTION OUTPUT ;
    USE SIGNAL ;
    PORT
      LAYER M3 ;
        RECT 30.777 34.368 30.801 34.560 ;
    END
  END q[464]
  PIN q[465]
    DIRECTION OUTPUT ;
    USE SIGNAL ;
    PORT
      LAYER M5 ;
        RECT 30.864 34.368 30.888 34.560 ;
    END
  END q[465]
  PIN q[466]
    DIRECTION OUTPUT ;
    USE SIGNAL ;
    PORT
      LAYER M3 ;
        RECT 30.921 34.368 30.945 34.560 ;
    END
  END q[466]
  PIN q[467]
    DIRECTION OUTPUT ;
    USE SIGNAL ;
    PORT
      LAYER M5 ;
        RECT 30.960 34.368 30.984 34.560 ;
    END
  END q[467]
  PIN q[468]
    DIRECTION OUTPUT ;
    USE SIGNAL ;
    PORT
      LAYER M3 ;
        RECT 31.029 34.368 31.053 34.560 ;
    END
  END q[468]
  PIN q[469]
    DIRECTION OUTPUT ;
    USE SIGNAL ;
    PORT
      LAYER M5 ;
        RECT 31.104 34.368 31.128 34.560 ;
    END
  END q[469]
  PIN q[470]
    DIRECTION OUTPUT ;
    USE SIGNAL ;
    PORT
      LAYER M3 ;
        RECT 31.173 34.368 31.197 34.560 ;
    END
  END q[470]
  PIN q[471]
    DIRECTION OUTPUT ;
    USE SIGNAL ;
    PORT
      LAYER M5 ;
        RECT 31.248 34.368 31.272 34.560 ;
    END
  END q[471]
  PIN q[472]
    DIRECTION OUTPUT ;
    USE SIGNAL ;
    PORT
      LAYER M3 ;
        RECT 31.317 34.368 31.341 34.560 ;
    END
  END q[472]
  PIN q[473]
    DIRECTION OUTPUT ;
    USE SIGNAL ;
    PORT
      LAYER M5 ;
        RECT 31.392 34.368 31.416 34.560 ;
    END
  END q[473]
  PIN q[474]
    DIRECTION OUTPUT ;
    USE SIGNAL ;
    PORT
      LAYER M3 ;
        RECT 31.425 34.368 31.449 34.560 ;
    END
  END q[474]
  PIN q[475]
    DIRECTION OUTPUT ;
    USE SIGNAL ;
    PORT
      LAYER M5 ;
        RECT 31.488 34.368 31.512 34.560 ;
    END
  END q[475]
  PIN q[476]
    DIRECTION OUTPUT ;
    USE SIGNAL ;
    PORT
      LAYER M3 ;
        RECT 31.569 34.368 31.593 34.560 ;
    END
  END q[476]
  PIN q[477]
    DIRECTION OUTPUT ;
    USE SIGNAL ;
    PORT
      LAYER M5 ;
        RECT 31.632 34.368 31.656 34.560 ;
    END
  END q[477]
  PIN q[478]
    DIRECTION OUTPUT ;
    USE SIGNAL ;
    PORT
      LAYER M3 ;
        RECT 31.713 34.368 31.737 34.560 ;
    END
  END q[478]
  PIN q[479]
    DIRECTION OUTPUT ;
    USE SIGNAL ;
    PORT
      LAYER M5 ;
        RECT 31.776 34.368 31.800 34.560 ;
    END
  END q[479]
  PIN q[480]
    DIRECTION OUTPUT ;
    USE SIGNAL ;
    PORT
      LAYER M3 ;
        RECT 31.821 34.368 31.845 34.560 ;
    END
  END q[480]
  PIN q[481]
    DIRECTION OUTPUT ;
    USE SIGNAL ;
    PORT
      LAYER M5 ;
        RECT 31.872 34.368 31.896 34.560 ;
    END
  END q[481]
  PIN q[482]
    DIRECTION OUTPUT ;
    USE SIGNAL ;
    PORT
      LAYER M3 ;
        RECT 31.965 34.368 31.989 34.560 ;
    END
  END q[482]
  PIN q[483]
    DIRECTION OUTPUT ;
    USE SIGNAL ;
    PORT
      LAYER M5 ;
        RECT 32.016 34.368 32.040 34.560 ;
    END
  END q[483]
  PIN q[484]
    DIRECTION OUTPUT ;
    USE SIGNAL ;
    PORT
      LAYER M3 ;
        RECT 32.073 34.368 32.097 34.560 ;
    END
  END q[484]
  PIN q[485]
    DIRECTION OUTPUT ;
    USE SIGNAL ;
    PORT
      LAYER M5 ;
        RECT 32.160 34.368 32.184 34.560 ;
    END
  END q[485]
  PIN q[486]
    DIRECTION OUTPUT ;
    USE SIGNAL ;
    PORT
      LAYER M3 ;
        RECT 32.217 34.368 32.241 34.560 ;
    END
  END q[486]
  PIN q[487]
    DIRECTION OUTPUT ;
    USE SIGNAL ;
    PORT
      LAYER M5 ;
        RECT 32.304 34.368 32.328 34.560 ;
    END
  END q[487]
  PIN q[488]
    DIRECTION OUTPUT ;
    USE SIGNAL ;
    PORT
      LAYER M3 ;
        RECT 32.361 34.368 32.385 34.560 ;
    END
  END q[488]
  PIN q[489]
    DIRECTION OUTPUT ;
    USE SIGNAL ;
    PORT
      LAYER M5 ;
        RECT 32.400 34.368 32.424 34.560 ;
    END
  END q[489]
  PIN q[490]
    DIRECTION OUTPUT ;
    USE SIGNAL ;
    PORT
      LAYER M3 ;
        RECT 32.469 34.368 32.493 34.560 ;
    END
  END q[490]
  PIN q[491]
    DIRECTION OUTPUT ;
    USE SIGNAL ;
    PORT
      LAYER M5 ;
        RECT 32.544 34.368 32.568 34.560 ;
    END
  END q[491]
  PIN q[492]
    DIRECTION OUTPUT ;
    USE SIGNAL ;
    PORT
      LAYER M3 ;
        RECT 32.613 34.368 32.637 34.560 ;
    END
  END q[492]
  PIN q[493]
    DIRECTION OUTPUT ;
    USE SIGNAL ;
    PORT
      LAYER M5 ;
        RECT 32.688 34.368 32.712 34.560 ;
    END
  END q[493]
  PIN q[494]
    DIRECTION OUTPUT ;
    USE SIGNAL ;
    PORT
      LAYER M3 ;
        RECT 32.721 34.368 32.745 34.560 ;
    END
  END q[494]
  PIN q[495]
    DIRECTION OUTPUT ;
    USE SIGNAL ;
    PORT
      LAYER M5 ;
        RECT 32.784 34.368 32.808 34.560 ;
    END
  END q[495]
  PIN q[496]
    DIRECTION OUTPUT ;
    USE SIGNAL ;
    PORT
      LAYER M3 ;
        RECT 32.865 34.368 32.889 34.560 ;
    END
  END q[496]
  PIN q[497]
    DIRECTION OUTPUT ;
    USE SIGNAL ;
    PORT
      LAYER M5 ;
        RECT 32.928 34.368 32.952 34.560 ;
    END
  END q[497]
  PIN q[498]
    DIRECTION OUTPUT ;
    USE SIGNAL ;
    PORT
      LAYER M3 ;
        RECT 33.009 34.368 33.033 34.560 ;
    END
  END q[498]
  PIN q[499]
    DIRECTION OUTPUT ;
    USE SIGNAL ;
    PORT
      LAYER M5 ;
        RECT 33.072 34.368 33.096 34.560 ;
    END
  END q[499]
  PIN q[500]
    DIRECTION OUTPUT ;
    USE SIGNAL ;
    PORT
      LAYER M3 ;
        RECT 33.117 34.368 33.141 34.560 ;
    END
  END q[500]
  PIN q[501]
    DIRECTION OUTPUT ;
    USE SIGNAL ;
    PORT
      LAYER M5 ;
        RECT 33.216 34.368 33.240 34.560 ;
    END
  END q[501]
  PIN q[502]
    DIRECTION OUTPUT ;
    USE SIGNAL ;
    PORT
      LAYER M3 ;
        RECT 33.261 34.368 33.285 34.560 ;
    END
  END q[502]
  PIN q[503]
    DIRECTION OUTPUT ;
    USE SIGNAL ;
    PORT
      LAYER M5 ;
        RECT 33.312 34.368 33.336 34.560 ;
    END
  END q[503]
  PIN q[504]
    DIRECTION OUTPUT ;
    USE SIGNAL ;
    PORT
      LAYER M3 ;
        RECT 33.405 34.368 33.429 34.560 ;
    END
  END q[504]
  PIN q[505]
    DIRECTION OUTPUT ;
    USE SIGNAL ;
    PORT
      LAYER M5 ;
        RECT 33.456 34.368 33.480 34.560 ;
    END
  END q[505]
  PIN q[506]
    DIRECTION OUTPUT ;
    USE SIGNAL ;
    PORT
      LAYER M3 ;
        RECT 33.513 34.368 33.537 34.560 ;
    END
  END q[506]
  PIN q[507]
    DIRECTION OUTPUT ;
    USE SIGNAL ;
    PORT
      LAYER M5 ;
        RECT 33.600 34.368 33.624 34.560 ;
    END
  END q[507]
  PIN q[508]
    DIRECTION OUTPUT ;
    USE SIGNAL ;
    PORT
      LAYER M3 ;
        RECT 33.657 34.368 33.681 34.560 ;
    END
  END q[508]
  PIN q[509]
    DIRECTION OUTPUT ;
    USE SIGNAL ;
    PORT
      LAYER M5 ;
        RECT 33.696 34.368 33.720 34.560 ;
    END
  END q[509]
  PIN q[510]
    DIRECTION OUTPUT ;
    USE SIGNAL ;
    PORT
      LAYER M3 ;
        RECT 33.765 34.368 33.789 34.560 ;
    END
  END q[510]
  PIN q[511]
    DIRECTION OUTPUT ;
    USE SIGNAL ;
    PORT
      LAYER M5 ;
        RECT 33.840 34.368 33.864 34.560 ;
    END
  END q[511]
  PIN q[512]
    DIRECTION OUTPUT ;
    USE SIGNAL ;
    PORT
      LAYER M3 ;
        RECT 33.909 34.368 33.933 34.560 ;
    END
  END q[512]
  PIN q[513]
    DIRECTION OUTPUT ;
    USE SIGNAL ;
    PORT
      LAYER M5 ;
        RECT 33.984 34.368 34.008 34.560 ;
    END
  END q[513]
  PIN VDD
    DIRECTION INOUT ;
    USE POWER ;
    PORT
      LAYER M5 ;
        RECT 2.460 0.500 2.580 34.060 ;
        RECT 7.860 0.500 7.980 34.060 ;
        RECT 13.260 0.500 13.380 34.060 ;
        RECT 18.660 0.500 18.780 34.060 ;
        RECT 24.060 0.500 24.180 34.060 ;
        RECT 29.460 0.500 29.580 34.060 ;
    END
  END VDD
  PIN VSS
    DIRECTION INOUT ;
    USE GROUND ;
    PORT
      LAYER M5 ;
        RECT 2.652 0.500 2.772 34.060 ;
        RECT 8.052 0.500 8.172 34.060 ;
        RECT 13.452 0.500 13.572 34.060 ;
        RECT 18.852 0.500 18.972 34.060 ;
        RECT 24.252 0.500 24.372 34.060 ;
        RECT 29.652 0.500 29.772 34.060 ;
    END
  END VSS
  OBS
    LAYER M1 ;
      RECT 0.500 0.500 34.060 34.060 ;
    LAYER M2 ;
      RECT 0.500 0.500 34.060 34.060 ;
    LAYER M3 ;
      RECT 0.500 0.500 34.060 34.060 ;
    LAYER M4 ;
      RECT 0.500 0.500 34.060 34.060 ;
    LAYER M5 ;
      RECT 0.500 0.900 2.460 33.660 ;
      RECT 2.580 0.900 2.652 33.660 ;
      RECT 2.772 0.900 7.860 33.660 ;
      RECT 7.980 0.900 8.052 33.660 ;
      RECT 8.172 0.900 13.260 33.660 ;
      RECT 13.380 0.900 13.452 33.660 ;
      RECT 13.572 0.900 18.660 33.660 ;
      RECT 18.780 0.900 18.852 33.660 ;
      RECT 18.972 0.900 24.060 33.660 ;
      RECT 24.180 0.900 24.252 33.660 ;
      RECT 24.372 0.900 29.460 33.660 ;
      RECT 29.580 0.900 29.652 33.660 ;
      RECT 29.772 0.900 34.060 33.660 ;
  END
END qfd_c_stn514
END LIBRARY
